VERSION 5.8 ;
BUSBITCHARS "[]" ;
DIVIDERCHAR "/" ;
UNITS
    DATABASE MICRONS 1000 ;
END UNITS

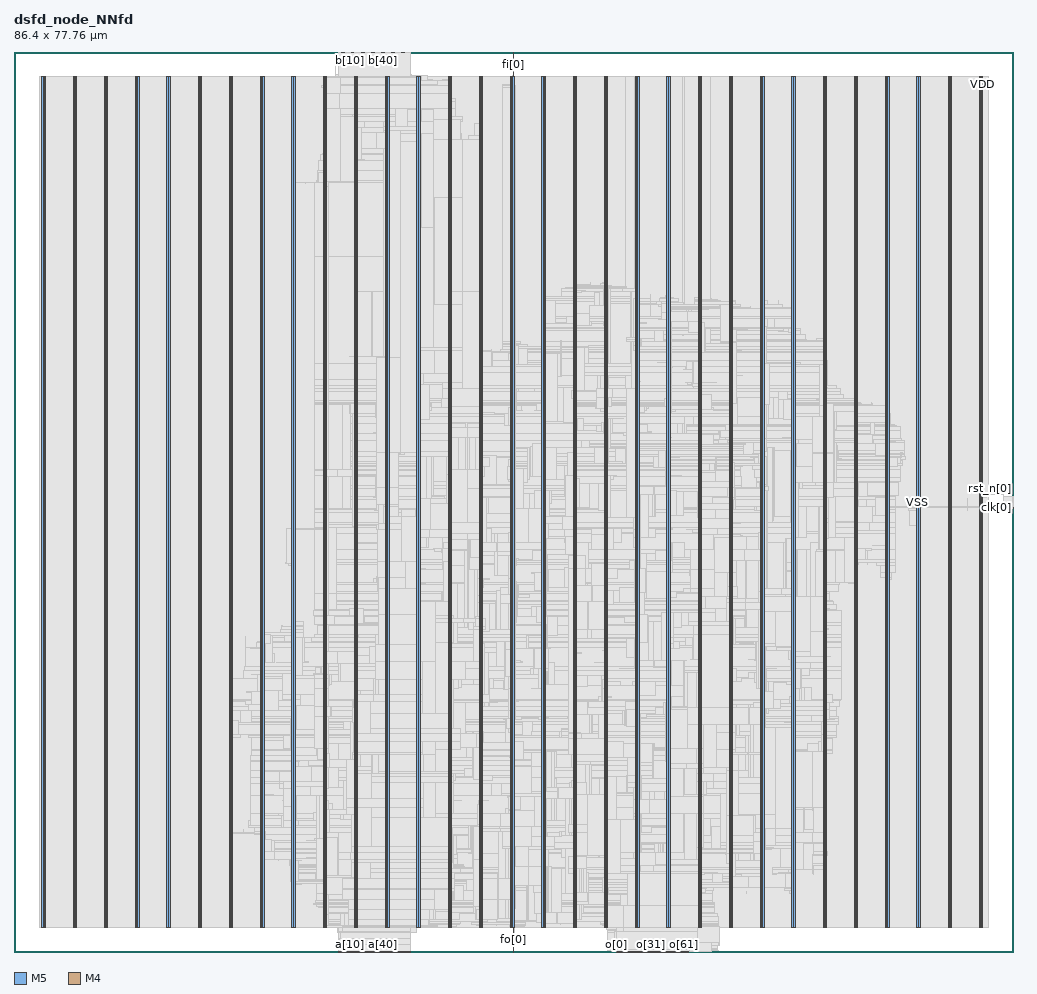
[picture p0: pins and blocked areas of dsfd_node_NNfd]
MACRO dsfd_node_NNfd
  FOREIGN dsfd_node_NNfd 0 0 ;
  CLASS BLOCK ;
  SIZE 86.4 BY 77.76 ;
  PIN a[0]
    DIRECTION INPUT ;
    USE SIGNAL ;
    PORT
      LAYER M5 ;
        RECT  28.032 0 28.056 0.084 ;
    END
  END a[0]
  PIN a[10]
    DIRECTION INPUT ;
    USE SIGNAL ;
    PORT
      LAYER M5 ;
        RECT  28.992 0 29.016 0.084 ;
    END
  END a[10]
  PIN a[11]
    DIRECTION INPUT ;
    USE SIGNAL ;
    PORT
      LAYER M5 ;
        RECT  29.088 0 29.112 0.084 ;
    END
  END a[11]
  PIN a[12]
    DIRECTION INPUT ;
    USE SIGNAL ;
    PORT
      LAYER M5 ;
        RECT  29.184 0 29.208 0.084 ;
    END
  END a[12]
  PIN a[13]
    DIRECTION INPUT ;
    USE SIGNAL ;
    PORT
      LAYER M5 ;
        RECT  29.28 0 29.304 0.084 ;
    END
  END a[13]
  PIN a[14]
    DIRECTION INPUT ;
    USE SIGNAL ;
    PORT
      LAYER M5 ;
        RECT  29.376 0 29.4 0.084 ;
    END
  END a[14]
  PIN a[15]
    DIRECTION INPUT ;
    USE SIGNAL ;
    PORT
      LAYER M5 ;
        RECT  29.472 0 29.496 0.084 ;
    END
  END a[15]
  PIN a[16]
    DIRECTION INPUT ;
    USE SIGNAL ;
    PORT
      LAYER M5 ;
        RECT  29.568 0 29.592 0.084 ;
    END
  END a[16]
  PIN a[17]
    DIRECTION INPUT ;
    USE SIGNAL ;
    PORT
      LAYER M5 ;
        RECT  29.664 0 29.688 0.084 ;
    END
  END a[17]
  PIN a[18]
    DIRECTION INPUT ;
    USE SIGNAL ;
    PORT
      LAYER M5 ;
        RECT  29.76 0 29.784 0.084 ;
    END
  END a[18]
  PIN a[19]
    DIRECTION INPUT ;
    USE SIGNAL ;
    PORT
      LAYER M5 ;
        RECT  29.856 0 29.88 0.084 ;
    END
  END a[19]
  PIN a[1]
    DIRECTION INPUT ;
    USE SIGNAL ;
    PORT
      LAYER M5 ;
        RECT  28.128 0 28.152 0.084 ;
    END
  END a[1]
  PIN a[20]
    DIRECTION INPUT ;
    USE SIGNAL ;
    PORT
      LAYER M5 ;
        RECT  29.952 0 29.976 0.084 ;
    END
  END a[20]
  PIN a[21]
    DIRECTION INPUT ;
    USE SIGNAL ;
    PORT
      LAYER M5 ;
        RECT  30.048 0 30.072 0.084 ;
    END
  END a[21]
  PIN a[22]
    DIRECTION INPUT ;
    USE SIGNAL ;
    PORT
      LAYER M5 ;
        RECT  30.144 0 30.168 0.084 ;
    END
  END a[22]
  PIN a[23]
    DIRECTION INPUT ;
    USE SIGNAL ;
    PORT
      LAYER M5 ;
        RECT  30.24 0 30.264 0.084 ;
    END
  END a[23]
  PIN a[24]
    DIRECTION INPUT ;
    USE SIGNAL ;
    PORT
      LAYER M5 ;
        RECT  30.336 0 30.36 0.084 ;
    END
  END a[24]
  PIN a[25]
    DIRECTION INPUT ;
    USE SIGNAL ;
    PORT
      LAYER M5 ;
        RECT  30.432 0 30.456 0.084 ;
    END
  END a[25]
  PIN a[26]
    DIRECTION INPUT ;
    USE SIGNAL ;
    PORT
      LAYER M5 ;
        RECT  30.528 0 30.552 0.084 ;
    END
  END a[26]
  PIN a[27]
    DIRECTION INPUT ;
    USE SIGNAL ;
    PORT
      LAYER M5 ;
        RECT  30.624 0 30.648 0.084 ;
    END
  END a[27]
  PIN a[28]
    DIRECTION INPUT ;
    USE SIGNAL ;
    PORT
      LAYER M5 ;
        RECT  30.72 0 30.744 0.084 ;
    END
  END a[28]
  PIN a[29]
    DIRECTION INPUT ;
    USE SIGNAL ;
    PORT
      LAYER M5 ;
        RECT  30.816 0 30.84 0.084 ;
    END
  END a[29]
  PIN a[2]
    DIRECTION INPUT ;
    USE SIGNAL ;
    PORT
      LAYER M5 ;
        RECT  28.224 0 28.248 0.084 ;
    END
  END a[2]
  PIN a[30]
    DIRECTION INPUT ;
    USE SIGNAL ;
    PORT
      LAYER M5 ;
        RECT  30.912 0 30.936 0.084 ;
    END
  END a[30]
  PIN a[31]
    DIRECTION INPUT ;
    USE SIGNAL ;
    PORT
      LAYER M5 ;
        RECT  31.008 0 31.032 0.084 ;
    END
  END a[31]
  PIN a[32]
    DIRECTION INPUT ;
    USE SIGNAL ;
    PORT
      LAYER M5 ;
        RECT  31.104 0 31.128 0.084 ;
    END
  END a[32]
  PIN a[33]
    DIRECTION INPUT ;
    USE SIGNAL ;
    PORT
      LAYER M5 ;
        RECT  31.2 0 31.224 0.084 ;
    END
  END a[33]
  PIN a[34]
    DIRECTION INPUT ;
    USE SIGNAL ;
    PORT
      LAYER M5 ;
        RECT  31.296 0 31.32 0.084 ;
    END
  END a[34]
  PIN a[35]
    DIRECTION INPUT ;
    USE SIGNAL ;
    PORT
      LAYER M5 ;
        RECT  31.392 0 31.416 0.084 ;
    END
  END a[35]
  PIN a[36]
    DIRECTION INPUT ;
    USE SIGNAL ;
    PORT
      LAYER M5 ;
        RECT  31.488 0 31.512 0.084 ;
    END
  END a[36]
  PIN a[37]
    DIRECTION INPUT ;
    USE SIGNAL ;
    PORT
      LAYER M5 ;
        RECT  31.584 0 31.608 0.084 ;
    END
  END a[37]
  PIN a[38]
    DIRECTION INPUT ;
    USE SIGNAL ;
    PORT
      LAYER M5 ;
        RECT  31.68 0 31.704 0.084 ;
    END
  END a[38]
  PIN a[39]
    DIRECTION INPUT ;
    USE SIGNAL ;
    PORT
      LAYER M5 ;
        RECT  31.776 0 31.8 0.084 ;
    END
  END a[39]
  PIN a[3]
    DIRECTION INPUT ;
    USE SIGNAL ;
    PORT
      LAYER M5 ;
        RECT  28.32 0 28.344 0.084 ;
    END
  END a[3]
  PIN a[40]
    DIRECTION INPUT ;
    USE SIGNAL ;
    PORT
      LAYER M5 ;
        RECT  31.872 0 31.896 0.084 ;
    END
  END a[40]
  PIN a[41]
    DIRECTION INPUT ;
    USE SIGNAL ;
    PORT
      LAYER M5 ;
        RECT  31.968 0 31.992 0.084 ;
    END
  END a[41]
  PIN a[42]
    DIRECTION INPUT ;
    USE SIGNAL ;
    PORT
      LAYER M5 ;
        RECT  32.064 0 32.088 0.084 ;
    END
  END a[42]
  PIN a[43]
    DIRECTION INPUT ;
    USE SIGNAL ;
    PORT
      LAYER M5 ;
        RECT  32.16 0 32.184 0.084 ;
    END
  END a[43]
  PIN a[44]
    DIRECTION INPUT ;
    USE SIGNAL ;
    PORT
      LAYER M5 ;
        RECT  32.256 0 32.28 0.084 ;
    END
  END a[44]
  PIN a[45]
    DIRECTION INPUT ;
    USE SIGNAL ;
    PORT
      LAYER M5 ;
        RECT  32.352 0 32.376 0.084 ;
    END
  END a[45]
  PIN a[46]
    DIRECTION INPUT ;
    USE SIGNAL ;
    PORT
      LAYER M5 ;
        RECT  32.448 0 32.472 0.084 ;
    END
  END a[46]
  PIN a[47]
    DIRECTION INPUT ;
    USE SIGNAL ;
    PORT
      LAYER M5 ;
        RECT  32.544 0 32.568 0.084 ;
    END
  END a[47]
  PIN a[48]
    DIRECTION INPUT ;
    USE SIGNAL ;
    PORT
      LAYER M5 ;
        RECT  32.64 0 32.664 0.084 ;
    END
  END a[48]
  PIN a[49]
    DIRECTION INPUT ;
    USE SIGNAL ;
    PORT
      LAYER M5 ;
        RECT  32.736 0 32.76 0.084 ;
    END
  END a[49]
  PIN a[4]
    DIRECTION INPUT ;
    USE SIGNAL ;
    PORT
      LAYER M5 ;
        RECT  28.416 0 28.44 0.084 ;
    END
  END a[4]
  PIN a[50]
    DIRECTION INPUT ;
    USE SIGNAL ;
    PORT
      LAYER M5 ;
        RECT  32.832 0 32.856 0.084 ;
    END
  END a[50]
  PIN a[51]
    DIRECTION INPUT ;
    USE SIGNAL ;
    PORT
      LAYER M5 ;
        RECT  32.928 0 32.952 0.084 ;
    END
  END a[51]
  PIN a[52]
    DIRECTION INPUT ;
    USE SIGNAL ;
    PORT
      LAYER M5 ;
        RECT  33.024 0 33.048 0.084 ;
    END
  END a[52]
  PIN a[53]
    DIRECTION INPUT ;
    USE SIGNAL ;
    PORT
      LAYER M5 ;
        RECT  33.12 0 33.144 0.084 ;
    END
  END a[53]
  PIN a[54]
    DIRECTION INPUT ;
    USE SIGNAL ;
    PORT
      LAYER M5 ;
        RECT  33.216 0 33.24 0.084 ;
    END
  END a[54]
  PIN a[55]
    DIRECTION INPUT ;
    USE SIGNAL ;
    PORT
      LAYER M5 ;
        RECT  33.312 0 33.336 0.084 ;
    END
  END a[55]
  PIN a[56]
    DIRECTION INPUT ;
    USE SIGNAL ;
    PORT
      LAYER M5 ;
        RECT  33.408 0 33.432 0.084 ;
    END
  END a[56]
  PIN a[57]
    DIRECTION INPUT ;
    USE SIGNAL ;
    PORT
      LAYER M5 ;
        RECT  33.504 0 33.528 0.084 ;
    END
  END a[57]
  PIN a[58]
    DIRECTION INPUT ;
    USE SIGNAL ;
    PORT
      LAYER M5 ;
        RECT  33.6 0 33.624 0.084 ;
    END
  END a[58]
  PIN a[59]
    DIRECTION INPUT ;
    USE SIGNAL ;
    PORT
      LAYER M5 ;
        RECT  33.696 0 33.72 0.084 ;
    END
  END a[59]
  PIN a[5]
    DIRECTION INPUT ;
    USE SIGNAL ;
    PORT
      LAYER M5 ;
        RECT  28.512 0 28.536 0.084 ;
    END
  END a[5]
  PIN a[60]
    DIRECTION INPUT ;
    USE SIGNAL ;
    PORT
      LAYER M5 ;
        RECT  33.792 0 33.816 0.084 ;
    END
  END a[60]
  PIN a[61]
    DIRECTION INPUT ;
    USE SIGNAL ;
    PORT
      LAYER M5 ;
        RECT  33.888 0 33.912 0.084 ;
    END
  END a[61]
  PIN a[62]
    DIRECTION INPUT ;
    USE SIGNAL ;
    PORT
      LAYER M5 ;
        RECT  33.984 0 34.008 0.084 ;
    END
  END a[62]
  PIN a[63]
    DIRECTION INPUT ;
    USE SIGNAL ;
    PORT
      LAYER M5 ;
        RECT  34.08 0 34.104 0.084 ;
    END
  END a[63]
  PIN a[64]
    DIRECTION INPUT ;
    USE SIGNAL ;
    PORT
      LAYER M5 ;
        RECT  34.176 0 34.2 0.084 ;
    END
  END a[64]
  PIN a[65]
    DIRECTION INPUT ;
    USE SIGNAL ;
    PORT
      LAYER M5 ;
        RECT  34.272 0 34.296 0.084 ;
    END
  END a[65]
  PIN a[6]
    DIRECTION INPUT ;
    USE SIGNAL ;
    PORT
      LAYER M5 ;
        RECT  28.608 0 28.632 0.084 ;
    END
  END a[6]
  PIN a[7]
    DIRECTION INPUT ;
    USE SIGNAL ;
    PORT
      LAYER M5 ;
        RECT  28.704 0 28.728 0.084 ;
    END
  END a[7]
  PIN a[8]
    DIRECTION INPUT ;
    USE SIGNAL ;
    PORT
      LAYER M5 ;
        RECT  28.8 0 28.824 0.084 ;
    END
  END a[8]
  PIN a[9]
    DIRECTION INPUT ;
    USE SIGNAL ;
    PORT
      LAYER M5 ;
        RECT  28.896 0 28.92 0.084 ;
    END
  END a[9]
  PIN b[0]
    DIRECTION INPUT ;
    USE SIGNAL ;
    PORT
      LAYER M5 ;
        RECT  28.032 77.676 28.056 77.76 ;
    END
  END b[0]
  PIN b[10]
    DIRECTION INPUT ;
    USE SIGNAL ;
    PORT
      LAYER M5 ;
        RECT  28.992 77.676 29.016 77.76 ;
    END
  END b[10]
  PIN b[11]
    DIRECTION INPUT ;
    USE SIGNAL ;
    PORT
      LAYER M5 ;
        RECT  29.088 77.676 29.112 77.76 ;
    END
  END b[11]
  PIN b[12]
    DIRECTION INPUT ;
    USE SIGNAL ;
    PORT
      LAYER M5 ;
        RECT  29.184 77.676 29.208 77.76 ;
    END
  END b[12]
  PIN b[13]
    DIRECTION INPUT ;
    USE SIGNAL ;
    PORT
      LAYER M5 ;
        RECT  29.28 77.676 29.304 77.76 ;
    END
  END b[13]
  PIN b[14]
    DIRECTION INPUT ;
    USE SIGNAL ;
    PORT
      LAYER M5 ;
        RECT  29.376 77.676 29.4 77.76 ;
    END
  END b[14]
  PIN b[15]
    DIRECTION INPUT ;
    USE SIGNAL ;
    PORT
      LAYER M5 ;
        RECT  29.472 77.676 29.496 77.76 ;
    END
  END b[15]
  PIN b[16]
    DIRECTION INPUT ;
    USE SIGNAL ;
    PORT
      LAYER M5 ;
        RECT  29.568 77.676 29.592 77.76 ;
    END
  END b[16]
  PIN b[17]
    DIRECTION INPUT ;
    USE SIGNAL ;
    PORT
      LAYER M5 ;
        RECT  29.664 77.676 29.688 77.76 ;
    END
  END b[17]
  PIN b[18]
    DIRECTION INPUT ;
    USE SIGNAL ;
    PORT
      LAYER M5 ;
        RECT  29.76 77.676 29.784 77.76 ;
    END
  END b[18]
  PIN b[19]
    DIRECTION INPUT ;
    USE SIGNAL ;
    PORT
      LAYER M5 ;
        RECT  29.856 77.676 29.88 77.76 ;
    END
  END b[19]
  PIN b[1]
    DIRECTION INPUT ;
    USE SIGNAL ;
    PORT
      LAYER M5 ;
        RECT  28.128 77.676 28.152 77.76 ;
    END
  END b[1]
  PIN b[20]
    DIRECTION INPUT ;
    USE SIGNAL ;
    PORT
      LAYER M5 ;
        RECT  29.952 77.676 29.976 77.76 ;
    END
  END b[20]
  PIN b[21]
    DIRECTION INPUT ;
    USE SIGNAL ;
    PORT
      LAYER M5 ;
        RECT  30.048 77.676 30.072 77.76 ;
    END
  END b[21]
  PIN b[22]
    DIRECTION INPUT ;
    USE SIGNAL ;
    PORT
      LAYER M5 ;
        RECT  30.144 77.676 30.168 77.76 ;
    END
  END b[22]
  PIN b[23]
    DIRECTION INPUT ;
    USE SIGNAL ;
    PORT
      LAYER M5 ;
        RECT  30.24 77.676 30.264 77.76 ;
    END
  END b[23]
  PIN b[24]
    DIRECTION INPUT ;
    USE SIGNAL ;
    PORT
      LAYER M5 ;
        RECT  30.336 77.676 30.36 77.76 ;
    END
  END b[24]
  PIN b[25]
    DIRECTION INPUT ;
    USE SIGNAL ;
    PORT
      LAYER M5 ;
        RECT  30.432 77.676 30.456 77.76 ;
    END
  END b[25]
  PIN b[26]
    DIRECTION INPUT ;
    USE SIGNAL ;
    PORT
      LAYER M5 ;
        RECT  30.528 77.676 30.552 77.76 ;
    END
  END b[26]
  PIN b[27]
    DIRECTION INPUT ;
    USE SIGNAL ;
    PORT
      LAYER M5 ;
        RECT  30.624 77.676 30.648 77.76 ;
    END
  END b[27]
  PIN b[28]
    DIRECTION INPUT ;
    USE SIGNAL ;
    PORT
      LAYER M5 ;
        RECT  30.72 77.676 30.744 77.76 ;
    END
  END b[28]
  PIN b[29]
    DIRECTION INPUT ;
    USE SIGNAL ;
    PORT
      LAYER M5 ;
        RECT  30.816 77.676 30.84 77.76 ;
    END
  END b[29]
  PIN b[2]
    DIRECTION INPUT ;
    USE SIGNAL ;
    PORT
      LAYER M5 ;
        RECT  28.224 77.676 28.248 77.76 ;
    END
  END b[2]
  PIN b[30]
    DIRECTION INPUT ;
    USE SIGNAL ;
    PORT
      LAYER M5 ;
        RECT  30.912 77.676 30.936 77.76 ;
    END
  END b[30]
  PIN b[31]
    DIRECTION INPUT ;
    USE SIGNAL ;
    PORT
      LAYER M5 ;
        RECT  31.008 77.676 31.032 77.76 ;
    END
  END b[31]
  PIN b[32]
    DIRECTION INPUT ;
    USE SIGNAL ;
    PORT
      LAYER M5 ;
        RECT  31.104 77.676 31.128 77.76 ;
    END
  END b[32]
  PIN b[33]
    DIRECTION INPUT ;
    USE SIGNAL ;
    PORT
      LAYER M5 ;
        RECT  31.2 77.676 31.224 77.76 ;
    END
  END b[33]
  PIN b[34]
    DIRECTION INPUT ;
    USE SIGNAL ;
    PORT
      LAYER M5 ;
        RECT  31.296 77.676 31.32 77.76 ;
    END
  END b[34]
  PIN b[35]
    DIRECTION INPUT ;
    USE SIGNAL ;
    PORT
      LAYER M5 ;
        RECT  31.392 77.676 31.416 77.76 ;
    END
  END b[35]
  PIN b[36]
    DIRECTION INPUT ;
    USE SIGNAL ;
    PORT
      LAYER M5 ;
        RECT  31.488 77.676 31.512 77.76 ;
    END
  END b[36]
  PIN b[37]
    DIRECTION INPUT ;
    USE SIGNAL ;
    PORT
      LAYER M5 ;
        RECT  31.584 77.676 31.608 77.76 ;
    END
  END b[37]
  PIN b[38]
    DIRECTION INPUT ;
    USE SIGNAL ;
    PORT
      LAYER M5 ;
        RECT  31.68 77.676 31.704 77.76 ;
    END
  END b[38]
  PIN b[39]
    DIRECTION INPUT ;
    USE SIGNAL ;
    PORT
      LAYER M5 ;
        RECT  31.776 77.676 31.8 77.76 ;
    END
  END b[39]
  PIN b[3]
    DIRECTION INPUT ;
    USE SIGNAL ;
    PORT
      LAYER M5 ;
        RECT  28.32 77.676 28.344 77.76 ;
    END
  END b[3]
  PIN b[40]
    DIRECTION INPUT ;
    USE SIGNAL ;
    PORT
      LAYER M5 ;
        RECT  31.872 77.676 31.896 77.76 ;
    END
  END b[40]
  PIN b[41]
    DIRECTION INPUT ;
    USE SIGNAL ;
    PORT
      LAYER M5 ;
        RECT  31.968 77.676 31.992 77.76 ;
    END
  END b[41]
  PIN b[42]
    DIRECTION INPUT ;
    USE SIGNAL ;
    PORT
      LAYER M5 ;
        RECT  32.064 77.676 32.088 77.76 ;
    END
  END b[42]
  PIN b[43]
    DIRECTION INPUT ;
    USE SIGNAL ;
    PORT
      LAYER M5 ;
        RECT  32.16 77.676 32.184 77.76 ;
    END
  END b[43]
  PIN b[44]
    DIRECTION INPUT ;
    USE SIGNAL ;
    PORT
      LAYER M5 ;
        RECT  32.256 77.676 32.28 77.76 ;
    END
  END b[44]
  PIN b[45]
    DIRECTION INPUT ;
    USE SIGNAL ;
    PORT
      LAYER M5 ;
        RECT  32.352 77.676 32.376 77.76 ;
    END
  END b[45]
  PIN b[46]
    DIRECTION INPUT ;
    USE SIGNAL ;
    PORT
      LAYER M5 ;
        RECT  32.448 77.676 32.472 77.76 ;
    END
  END b[46]
  PIN b[47]
    DIRECTION INPUT ;
    USE SIGNAL ;
    PORT
      LAYER M5 ;
        RECT  32.544 77.676 32.568 77.76 ;
    END
  END b[47]
  PIN b[48]
    DIRECTION INPUT ;
    USE SIGNAL ;
    PORT
      LAYER M5 ;
        RECT  32.64 77.676 32.664 77.76 ;
    END
  END b[48]
  PIN b[49]
    DIRECTION INPUT ;
    USE SIGNAL ;
    PORT
      LAYER M5 ;
        RECT  32.736 77.676 32.76 77.76 ;
    END
  END b[49]
  PIN b[4]
    DIRECTION INPUT ;
    USE SIGNAL ;
    PORT
      LAYER M5 ;
        RECT  28.416 77.676 28.44 77.76 ;
    END
  END b[4]
  PIN b[50]
    DIRECTION INPUT ;
    USE SIGNAL ;
    PORT
      LAYER M5 ;
        RECT  32.832 77.676 32.856 77.76 ;
    END
  END b[50]
  PIN b[51]
    DIRECTION INPUT ;
    USE SIGNAL ;
    PORT
      LAYER M5 ;
        RECT  32.928 77.676 32.952 77.76 ;
    END
  END b[51]
  PIN b[52]
    DIRECTION INPUT ;
    USE SIGNAL ;
    PORT
      LAYER M5 ;
        RECT  33.024 77.676 33.048 77.76 ;
    END
  END b[52]
  PIN b[53]
    DIRECTION INPUT ;
    USE SIGNAL ;
    PORT
      LAYER M5 ;
        RECT  33.12 77.676 33.144 77.76 ;
    END
  END b[53]
  PIN b[54]
    DIRECTION INPUT ;
    USE SIGNAL ;
    PORT
      LAYER M5 ;
        RECT  33.216 77.676 33.24 77.76 ;
    END
  END b[54]
  PIN b[55]
    DIRECTION INPUT ;
    USE SIGNAL ;
    PORT
      LAYER M5 ;
        RECT  33.312 77.676 33.336 77.76 ;
    END
  END b[55]
  PIN b[56]
    DIRECTION INPUT ;
    USE SIGNAL ;
    PORT
      LAYER M5 ;
        RECT  33.408 77.676 33.432 77.76 ;
    END
  END b[56]
  PIN b[57]
    DIRECTION INPUT ;
    USE SIGNAL ;
    PORT
      LAYER M5 ;
        RECT  33.504 77.676 33.528 77.76 ;
    END
  END b[57]
  PIN b[58]
    DIRECTION INPUT ;
    USE SIGNAL ;
    PORT
      LAYER M5 ;
        RECT  33.6 77.676 33.624 77.76 ;
    END
  END b[58]
  PIN b[59]
    DIRECTION INPUT ;
    USE SIGNAL ;
    PORT
      LAYER M5 ;
        RECT  33.696 77.676 33.72 77.76 ;
    END
  END b[59]
  PIN b[5]
    DIRECTION INPUT ;
    USE SIGNAL ;
    PORT
      LAYER M5 ;
        RECT  28.512 77.676 28.536 77.76 ;
    END
  END b[5]
  PIN b[60]
    DIRECTION INPUT ;
    USE SIGNAL ;
    PORT
      LAYER M5 ;
        RECT  33.792 77.676 33.816 77.76 ;
    END
  END b[60]
  PIN b[61]
    DIRECTION INPUT ;
    USE SIGNAL ;
    PORT
      LAYER M5 ;
        RECT  33.888 77.676 33.912 77.76 ;
    END
  END b[61]
  PIN b[62]
    DIRECTION INPUT ;
    USE SIGNAL ;
    PORT
      LAYER M5 ;
        RECT  33.984 77.676 34.008 77.76 ;
    END
  END b[62]
  PIN b[63]
    DIRECTION INPUT ;
    USE SIGNAL ;
    PORT
      LAYER M5 ;
        RECT  34.08 77.676 34.104 77.76 ;
    END
  END b[63]
  PIN b[64]
    DIRECTION INPUT ;
    USE SIGNAL ;
    PORT
      LAYER M5 ;
        RECT  34.176 77.676 34.2 77.76 ;
    END
  END b[64]
  PIN b[65]
    DIRECTION INPUT ;
    USE SIGNAL ;
    PORT
      LAYER M5 ;
        RECT  34.272 77.676 34.296 77.76 ;
    END
  END b[65]
  PIN b[6]
    DIRECTION INPUT ;
    USE SIGNAL ;
    PORT
      LAYER M5 ;
        RECT  28.608 77.676 28.632 77.76 ;
    END
  END b[6]
  PIN b[7]
    DIRECTION INPUT ;
    USE SIGNAL ;
    PORT
      LAYER M5 ;
        RECT  28.704 77.676 28.728 77.76 ;
    END
  END b[7]
  PIN b[8]
    DIRECTION INPUT ;
    USE SIGNAL ;
    PORT
      LAYER M5 ;
        RECT  28.8 77.676 28.824 77.76 ;
    END
  END b[8]
  PIN b[9]
    DIRECTION INPUT ;
    USE SIGNAL ;
    PORT
      LAYER M5 ;
        RECT  28.896 77.676 28.92 77.76 ;
    END
  END b[9]
  PIN clk[0]
    DIRECTION INPUT ;
    USE SIGNAL ;
    PORT
      LAYER M4 ;
        RECT  86.316 38.352 86.4 38.376 ;
    END
    PORT
      LAYER M4 ;
        RECT  86.321 38.352 86.364 38.376 ;
    END
  END clk[0]
  PIN fi[0]
    DIRECTION INPUT ;
    USE SIGNAL ;
    PORT
      LAYER M5 ;
        RECT  43.152 77.676 43.176 77.76 ;
    END
    PORT
      LAYER M5 ;
        RECT  43.152 75.623 43.176 77.712 ;
    END
  END fi[0]
  PIN fo[0]
    DIRECTION OUTPUT ;
    USE SIGNAL ;
    PORT
      LAYER M5 ;
        RECT  43.152 0 43.176 0.084 ;
    END
    PORT
      LAYER M5 ;
        RECT  43.152 0.016 43.176 2.137 ;
    END
  END fo[0]
  PIN o[0]
    DIRECTION OUTPUT ;
    USE SIGNAL ;
    PORT
      LAYER M5 ;
        RECT  52.032 0 52.056 0.084 ;
    END
  END o[0]
  PIN o[10]
    DIRECTION OUTPUT ;
    USE SIGNAL ;
    PORT
      LAYER M5 ;
        RECT  52.992 0 53.016 0.084 ;
    END
  END o[10]
  PIN o[11]
    DIRECTION OUTPUT ;
    USE SIGNAL ;
    PORT
      LAYER M5 ;
        RECT  53.088 0 53.112 0.084 ;
    END
  END o[11]
  PIN o[12]
    DIRECTION OUTPUT ;
    USE SIGNAL ;
    PORT
      LAYER M5 ;
        RECT  53.184 0 53.208 0.084 ;
    END
  END o[12]
  PIN o[13]
    DIRECTION OUTPUT ;
    USE SIGNAL ;
    PORT
      LAYER M5 ;
        RECT  53.28 0 53.304 0.084 ;
    END
  END o[13]
  PIN o[14]
    DIRECTION OUTPUT ;
    USE SIGNAL ;
    PORT
      LAYER M5 ;
        RECT  53.376 0 53.4 0.084 ;
    END
  END o[14]
  PIN o[15]
    DIRECTION OUTPUT ;
    USE SIGNAL ;
    PORT
      LAYER M5 ;
        RECT  53.472 0 53.496 0.084 ;
    END
  END o[15]
  PIN o[16]
    DIRECTION OUTPUT ;
    USE SIGNAL ;
    PORT
      LAYER M5 ;
        RECT  53.568 0 53.592 0.084 ;
    END
  END o[16]
  PIN o[17]
    DIRECTION OUTPUT ;
    USE SIGNAL ;
    PORT
      LAYER M5 ;
        RECT  53.664 0 53.688 0.084 ;
    END
  END o[17]
  PIN o[18]
    DIRECTION OUTPUT ;
    USE SIGNAL ;
    PORT
      LAYER M5 ;
        RECT  53.76 0 53.784 0.084 ;
    END
  END o[18]
  PIN o[19]
    DIRECTION OUTPUT ;
    USE SIGNAL ;
    PORT
      LAYER M5 ;
        RECT  53.856 0 53.88 0.084 ;
    END
  END o[19]
  PIN o[1]
    DIRECTION OUTPUT ;
    USE SIGNAL ;
    PORT
      LAYER M5 ;
        RECT  52.128 0 52.152 0.084 ;
    END
  END o[1]
  PIN o[20]
    DIRECTION OUTPUT ;
    USE SIGNAL ;
    PORT
      LAYER M5 ;
        RECT  53.952 0 53.976 0.084 ;
    END
  END o[20]
  PIN o[21]
    DIRECTION OUTPUT ;
    USE SIGNAL ;
    PORT
      LAYER M5 ;
        RECT  54.048 0 54.072 0.084 ;
    END
  END o[21]
  PIN o[22]
    DIRECTION OUTPUT ;
    USE SIGNAL ;
    PORT
      LAYER M5 ;
        RECT  54.144 0 54.168 0.084 ;
    END
  END o[22]
  PIN o[23]
    DIRECTION OUTPUT ;
    USE SIGNAL ;
    PORT
      LAYER M5 ;
        RECT  54.24 0 54.264 0.084 ;
    END
  END o[23]
  PIN o[24]
    DIRECTION OUTPUT ;
    USE SIGNAL ;
    PORT
      LAYER M5 ;
        RECT  54.336 0 54.36 0.084 ;
    END
  END o[24]
  PIN o[25]
    DIRECTION OUTPUT ;
    USE SIGNAL ;
    PORT
      LAYER M5 ;
        RECT  54.432 0 54.456 0.084 ;
    END
  END o[25]
  PIN o[26]
    DIRECTION OUTPUT ;
    USE SIGNAL ;
    PORT
      LAYER M5 ;
        RECT  54.528 0 54.552 0.084 ;
    END
  END o[26]
  PIN o[27]
    DIRECTION OUTPUT ;
    USE SIGNAL ;
    PORT
      LAYER M5 ;
        RECT  54.624 0 54.648 0.084 ;
    END
  END o[27]
  PIN o[28]
    DIRECTION OUTPUT ;
    USE SIGNAL ;
    PORT
      LAYER M5 ;
        RECT  54.72 0 54.744 0.084 ;
    END
  END o[28]
  PIN o[29]
    DIRECTION OUTPUT ;
    USE SIGNAL ;
    PORT
      LAYER M5 ;
        RECT  54.816 0 54.84 0.084 ;
    END
  END o[29]
  PIN o[2]
    DIRECTION OUTPUT ;
    USE SIGNAL ;
    PORT
      LAYER M5 ;
        RECT  52.224 0 52.248 0.084 ;
    END
  END o[2]
  PIN o[30]
    DIRECTION OUTPUT ;
    USE SIGNAL ;
    PORT
      LAYER M5 ;
        RECT  54.912 0 54.936 0.084 ;
    END
  END o[30]
  PIN o[31]
    DIRECTION OUTPUT ;
    USE SIGNAL ;
    PORT
      LAYER M5 ;
        RECT  55.008 0 55.032 0.084 ;
    END
  END o[31]
  PIN o[32]
    DIRECTION OUTPUT ;
    USE SIGNAL ;
    PORT
      LAYER M5 ;
        RECT  55.104 0 55.128 0.084 ;
    END
  END o[32]
  PIN o[33]
    DIRECTION OUTPUT ;
    USE SIGNAL ;
    PORT
      LAYER M5 ;
        RECT  55.2 0 55.224 0.084 ;
    END
  END o[33]
  PIN o[34]
    DIRECTION OUTPUT ;
    USE SIGNAL ;
    PORT
      LAYER M5 ;
        RECT  55.296 0 55.32 0.084 ;
    END
  END o[34]
  PIN o[35]
    DIRECTION OUTPUT ;
    USE SIGNAL ;
    PORT
      LAYER M5 ;
        RECT  55.392 0 55.416 0.084 ;
    END
  END o[35]
  PIN o[36]
    DIRECTION OUTPUT ;
    USE SIGNAL ;
    PORT
      LAYER M5 ;
        RECT  55.488 0 55.512 0.084 ;
    END
  END o[36]
  PIN o[37]
    DIRECTION OUTPUT ;
    USE SIGNAL ;
    PORT
      LAYER M5 ;
        RECT  55.584 0 55.608 0.084 ;
    END
  END o[37]
  PIN o[38]
    DIRECTION OUTPUT ;
    USE SIGNAL ;
    PORT
      LAYER M5 ;
        RECT  55.68 0 55.704 0.084 ;
    END
  END o[38]
  PIN o[39]
    DIRECTION OUTPUT ;
    USE SIGNAL ;
    PORT
      LAYER M5 ;
        RECT  55.776 0 55.8 0.084 ;
    END
  END o[39]
  PIN o[3]
    DIRECTION OUTPUT ;
    USE SIGNAL ;
    PORT
      LAYER M5 ;
        RECT  52.32 0 52.344 0.084 ;
    END
  END o[3]
  PIN o[40]
    DIRECTION OUTPUT ;
    USE SIGNAL ;
    PORT
      LAYER M5 ;
        RECT  55.872 0 55.896 0.084 ;
    END
  END o[40]
  PIN o[41]
    DIRECTION OUTPUT ;
    USE SIGNAL ;
    PORT
      LAYER M5 ;
        RECT  55.968 0 55.992 0.084 ;
    END
  END o[41]
  PIN o[42]
    DIRECTION OUTPUT ;
    USE SIGNAL ;
    PORT
      LAYER M5 ;
        RECT  56.064 0 56.088 0.084 ;
    END
  END o[42]
  PIN o[43]
    DIRECTION OUTPUT ;
    USE SIGNAL ;
    PORT
      LAYER M5 ;
        RECT  56.16 0 56.184 0.084 ;
    END
  END o[43]
  PIN o[44]
    DIRECTION OUTPUT ;
    USE SIGNAL ;
    PORT
      LAYER M5 ;
        RECT  56.256 0 56.28 0.084 ;
    END
  END o[44]
  PIN o[45]
    DIRECTION OUTPUT ;
    USE SIGNAL ;
    PORT
      LAYER M5 ;
        RECT  56.352 0 56.376 0.084 ;
    END
  END o[45]
  PIN o[46]
    DIRECTION OUTPUT ;
    USE SIGNAL ;
    PORT
      LAYER M5 ;
        RECT  56.448 0 56.472 0.084 ;
    END
  END o[46]
  PIN o[47]
    DIRECTION OUTPUT ;
    USE SIGNAL ;
    PORT
      LAYER M5 ;
        RECT  56.544 0 56.568 0.084 ;
    END
  END o[47]
  PIN o[48]
    DIRECTION OUTPUT ;
    USE SIGNAL ;
    PORT
      LAYER M5 ;
        RECT  56.64 0 56.664 0.084 ;
    END
  END o[48]
  PIN o[49]
    DIRECTION OUTPUT ;
    USE SIGNAL ;
    PORT
      LAYER M5 ;
        RECT  56.736 0 56.76 0.084 ;
    END
  END o[49]
  PIN o[4]
    DIRECTION OUTPUT ;
    USE SIGNAL ;
    PORT
      LAYER M5 ;
        RECT  52.416 0 52.44 0.084 ;
    END
  END o[4]
  PIN o[50]
    DIRECTION OUTPUT ;
    USE SIGNAL ;
    PORT
      LAYER M5 ;
        RECT  56.832 0 56.856 0.084 ;
    END
  END o[50]
  PIN o[51]
    DIRECTION OUTPUT ;
    USE SIGNAL ;
    PORT
      LAYER M5 ;
        RECT  56.928 0 56.952 0.084 ;
    END
  END o[51]
  PIN o[52]
    DIRECTION OUTPUT ;
    USE SIGNAL ;
    PORT
      LAYER M5 ;
        RECT  57.024 0 57.048 0.084 ;
    END
  END o[52]
  PIN o[53]
    DIRECTION OUTPUT ;
    USE SIGNAL ;
    PORT
      LAYER M5 ;
        RECT  57.12 0 57.144 0.084 ;
    END
  END o[53]
  PIN o[54]
    DIRECTION OUTPUT ;
    USE SIGNAL ;
    PORT
      LAYER M5 ;
        RECT  57.216 0 57.24 0.084 ;
    END
  END o[54]
  PIN o[55]
    DIRECTION OUTPUT ;
    USE SIGNAL ;
    PORT
      LAYER M5 ;
        RECT  57.312 0 57.336 0.084 ;
    END
  END o[55]
  PIN o[56]
    DIRECTION OUTPUT ;
    USE SIGNAL ;
    PORT
      LAYER M5 ;
        RECT  57.408 0 57.432 0.084 ;
    END
  END o[56]
  PIN o[57]
    DIRECTION OUTPUT ;
    USE SIGNAL ;
    PORT
      LAYER M5 ;
        RECT  57.504 0 57.528 0.084 ;
    END
  END o[57]
  PIN o[58]
    DIRECTION OUTPUT ;
    USE SIGNAL ;
    PORT
      LAYER M5 ;
        RECT  57.6 0 57.624 0.084 ;
    END
  END o[58]
  PIN o[59]
    DIRECTION OUTPUT ;
    USE SIGNAL ;
    PORT
      LAYER M5 ;
        RECT  57.696 0 57.72 0.084 ;
    END
  END o[59]
  PIN o[5]
    DIRECTION OUTPUT ;
    USE SIGNAL ;
    PORT
      LAYER M5 ;
        RECT  52.512 0 52.536 0.084 ;
    END
  END o[5]
  PIN o[60]
    DIRECTION OUTPUT ;
    USE SIGNAL ;
    PORT
      LAYER M5 ;
        RECT  57.792 0 57.816 0.084 ;
    END
  END o[60]
  PIN o[61]
    DIRECTION OUTPUT ;
    USE SIGNAL ;
    PORT
      LAYER M5 ;
        RECT  57.888 0 57.912 0.084 ;
    END
  END o[61]
  PIN o[62]
    DIRECTION OUTPUT ;
    USE SIGNAL ;
    PORT
      LAYER M5 ;
        RECT  57.984 0 58.008 0.084 ;
    END
  END o[62]
  PIN o[63]
    DIRECTION OUTPUT ;
    USE SIGNAL ;
    PORT
      LAYER M5 ;
        RECT  58.08 0 58.104 0.084 ;
    END
  END o[63]
  PIN o[64]
    DIRECTION OUTPUT ;
    USE SIGNAL ;
    PORT
      LAYER M5 ;
        RECT  58.176 0 58.2 0.084 ;
    END
  END o[64]
  PIN o[65]
    DIRECTION OUTPUT ;
    USE SIGNAL ;
    PORT
      LAYER M5 ;
        RECT  58.272 0 58.296 0.084 ;
    END
  END o[65]
  PIN o[6]
    DIRECTION OUTPUT ;
    USE SIGNAL ;
    PORT
      LAYER M5 ;
        RECT  52.608 0 52.632 0.084 ;
    END
  END o[6]
  PIN o[7]
    DIRECTION OUTPUT ;
    USE SIGNAL ;
    PORT
      LAYER M5 ;
        RECT  52.704 0 52.728 0.084 ;
    END
  END o[7]
  PIN o[8]
    DIRECTION OUTPUT ;
    USE SIGNAL ;
    PORT
      LAYER M5 ;
        RECT  52.8 0 52.824 0.084 ;
    END
  END o[8]
  PIN o[9]
    DIRECTION OUTPUT ;
    USE SIGNAL ;
    PORT
      LAYER M5 ;
        RECT  52.896 0 52.92 0.084 ;
    END
  END o[9]
  PIN rst_n[0]
    DIRECTION INPUT ;
    USE SIGNAL ;
    PORT
      LAYER M4 ;
        RECT  86.316 39.36 86.4 39.384 ;
    END
    PORT
      LAYER M4 ;
        RECT  86.321 39.36 86.364 39.384 ;
    END
  END rst_n[0]
  PIN VDD
    DIRECTION INOUT ;
    USE POWER ;
    PORT
      LAYER M5 ;
        RECT  83.592 2.151 83.712 75.609 ;
        RECT  80.892 2.151 81.012 75.609 ;
        RECT  78.192 2.151 78.312 75.609 ;
        RECT  75.492 2.151 75.612 75.609 ;
        RECT  72.792 2.151 72.912 75.609 ;
        RECT  70.092 2.151 70.212 75.609 ;
        RECT  67.392 2.151 67.512 75.609 ;
        RECT  64.692 2.151 64.812 75.609 ;
        RECT  61.992 2.151 62.112 75.609 ;
        RECT  59.292 2.151 59.412 75.609 ;
        RECT  56.592 2.151 56.712 75.609 ;
        RECT  53.892 2.151 54.012 75.609 ;
        RECT  51.192 2.151 51.312 75.609 ;
        RECT  48.492 2.151 48.612 75.609 ;
        RECT  45.792 2.151 45.912 75.609 ;
        RECT  43.092 2.151 43.212 75.609 ;
        RECT  40.392 2.151 40.512 75.609 ;
        RECT  37.692 2.151 37.812 75.609 ;
        RECT  34.992 2.151 35.112 75.609 ;
        RECT  32.292 2.151 32.412 75.609 ;
        RECT  29.592 2.151 29.712 75.609 ;
        RECT  26.892 2.151 27.012 75.609 ;
        RECT  24.192 2.151 24.312 75.609 ;
        RECT  21.492 2.151 21.612 75.609 ;
        RECT  18.792 2.151 18.912 75.609 ;
        RECT  16.092 2.151 16.212 75.609 ;
        RECT  13.392 2.151 13.512 75.609 ;
        RECT  10.692 2.151 10.812 75.609 ;
        RECT  7.992 2.151 8.112 75.609 ;
        RECT  5.292 2.151 5.412 75.609 ;
        RECT  2.592 2.151 2.712 75.609 ;
    END
  END VDD
  PIN VSS
    DIRECTION INOUT ;
    USE GROUND ;
    PORT
      LAYER M5 ;
        RECT  83.4 2.137 83.52 75.623 ;
        RECT  80.7 2.137 80.82 75.623 ;
        RECT  78 2.137 78.12 75.623 ;
        RECT  75.3 2.137 75.42 75.623 ;
        RECT  72.6 2.137 72.72 75.623 ;
        RECT  69.9 2.137 70.02 75.623 ;
        RECT  67.2 2.137 67.32 75.623 ;
        RECT  64.5 2.137 64.62 75.623 ;
        RECT  61.8 2.137 61.92 75.623 ;
        RECT  59.1 2.137 59.22 75.623 ;
        RECT  56.4 2.137 56.52 75.623 ;
        RECT  53.7 2.137 53.82 75.623 ;
        RECT  51 2.137 51.12 75.623 ;
        RECT  48.3 2.137 48.42 75.623 ;
        RECT  45.6 2.137 45.72 75.623 ;
        RECT  42.9 2.137 43.02 75.623 ;
        RECT  40.2 2.137 40.32 75.623 ;
        RECT  37.5 2.137 37.62 75.623 ;
        RECT  34.8 2.137 34.92 75.623 ;
        RECT  32.1 2.137 32.22 75.623 ;
        RECT  29.4 2.137 29.52 75.623 ;
        RECT  26.7 2.137 26.82 75.623 ;
        RECT  24 2.137 24.12 75.623 ;
        RECT  21.3 2.137 21.42 75.623 ;
        RECT  18.6 2.137 18.72 75.623 ;
        RECT  15.9 2.137 16.02 75.623 ;
        RECT  13.2 2.137 13.32 75.623 ;
        RECT  10.5 2.137 10.62 75.623 ;
        RECT  7.8 2.137 7.92 75.623 ;
        RECT  5.1 2.137 5.22 75.623 ;
        RECT  2.4 2.137 2.52 75.623 ;
    END
  END VSS
  # OT_OBS_CLOSED layer=M5 d_um=1.536 added=231
  OBS
    LAYER RVTN ;
     RECT  2.16 2.16 84.24 2.295 ;
     RECT  2.16 2.565 84.24 2.835 ;
     RECT  2.16 3.105 84.24 3.375 ;
     RECT  2.16 3.645 84.24 3.915 ;
     RECT  2.16 4.185 84.24 4.455 ;
     RECT  2.16 4.725 84.24 4.995 ;
     RECT  2.16 5.265 84.24 5.535 ;
     RECT  2.16 5.805 84.24 6.075 ;
     RECT  2.16 6.345 84.24 6.615 ;
     RECT  2.16 6.885 84.24 7.155 ;
     RECT  2.16 7.425 84.24 7.695 ;
     RECT  2.16 7.965 84.24 8.235 ;
     RECT  2.16 8.505 84.24 8.775 ;
     RECT  2.16 9.045 84.24 9.315 ;
     RECT  2.16 9.585 84.24 9.855 ;
     RECT  2.16 10.125 84.24 10.395 ;
     RECT  2.16 10.665 84.24 10.935 ;
     RECT  2.16 11.205 84.24 11.475 ;
     RECT  2.16 11.745 84.24 12.015 ;
     RECT  2.16 12.285 84.24 12.555 ;
     RECT  2.16 12.825 84.24 13.095 ;
     RECT  2.16 13.365 84.24 13.635 ;
     RECT  2.16 13.905 84.24 14.175 ;
     RECT  2.16 14.445 84.24 14.715 ;
     RECT  2.16 14.985 84.24 15.255 ;
     RECT  2.16 15.525 84.24 15.795 ;
     RECT  2.16 16.065 84.24 16.335 ;
     RECT  2.16 16.605 84.24 16.875 ;
     RECT  2.16 17.145 84.24 17.415 ;
     RECT  2.16 17.685 84.24 17.955 ;
     RECT  2.16 18.225 84.24 18.495 ;
     RECT  2.16 18.765 84.24 19.035 ;
     RECT  2.16 19.305 84.24 19.575 ;
     RECT  2.16 19.845 84.24 20.115 ;
     RECT  2.16 20.385 84.24 20.655 ;
     RECT  2.16 20.925 84.24 21.195 ;
     RECT  2.16 21.465 84.24 21.735 ;
     RECT  2.16 22.005 84.24 22.275 ;
     RECT  2.16 22.545 84.24 22.815 ;
     RECT  2.16 23.085 84.24 23.355 ;
     RECT  2.16 23.625 84.24 23.895 ;
     RECT  2.16 24.165 84.24 24.435 ;
     RECT  2.16 24.705 84.24 24.975 ;
     RECT  2.16 25.245 84.24 25.515 ;
     RECT  2.16 25.785 84.24 26.055 ;
     RECT  2.16 26.325 84.24 26.595 ;
     RECT  2.16 26.865 84.24 27.135 ;
     RECT  2.16 27.405 84.24 27.675 ;
     RECT  2.16 27.945 84.24 28.215 ;
     RECT  2.16 28.485 84.24 28.755 ;
     RECT  2.16 29.025 84.24 29.295 ;
     RECT  2.16 29.565 84.24 29.835 ;
     RECT  2.16 30.105 84.24 30.375 ;
     RECT  2.16 30.645 84.24 30.915 ;
     RECT  2.16 31.185 84.24 31.455 ;
     RECT  2.16 31.725 84.24 31.995 ;
     RECT  2.16 32.265 84.24 32.535 ;
     RECT  2.16 32.805 84.24 33.075 ;
     RECT  2.16 33.345 84.24 33.615 ;
     RECT  2.16 33.885 84.24 34.155 ;
     RECT  2.16 34.425 84.24 34.695 ;
     RECT  2.16 34.965 84.24 35.235 ;
     RECT  2.16 35.505 84.24 35.775 ;
     RECT  2.16 36.045 84.24 36.315 ;
     RECT  2.16 36.585 84.24 36.855 ;
     RECT  2.16 37.125 84.24 37.395 ;
     RECT  2.16 37.665 84.24 37.935 ;
     RECT  2.16 38.205 84.24 38.475 ;
     RECT  2.16 38.745 84.24 39.015 ;
     RECT  2.16 39.285 84.24 39.555 ;
     RECT  2.16 39.825 84.24 40.095 ;
     RECT  2.16 40.365 84.24 40.635 ;
     RECT  2.16 40.905 84.24 41.175 ;
     RECT  2.16 41.445 84.24 41.715 ;
     RECT  2.16 41.985 84.24 42.255 ;
     RECT  2.16 42.525 84.24 42.795 ;
     RECT  2.16 43.065 84.24 43.335 ;
     RECT  2.16 43.605 84.24 43.875 ;
     RECT  2.16 44.145 84.24 44.415 ;
     RECT  2.16 44.685 84.24 44.955 ;
     RECT  2.16 45.225 84.24 45.495 ;
     RECT  2.16 45.765 84.24 46.035 ;
     RECT  2.16 46.305 84.24 46.575 ;
     RECT  2.16 46.845 84.24 47.115 ;
     RECT  2.16 47.385 84.24 47.655 ;
     RECT  2.16 47.925 84.24 48.195 ;
     RECT  2.16 48.465 84.24 48.735 ;
     RECT  2.16 49.005 84.24 49.275 ;
     RECT  2.16 49.545 84.24 49.815 ;
     RECT  2.16 50.085 84.24 50.355 ;
     RECT  2.16 50.625 84.24 50.895 ;
     RECT  2.16 51.165 84.24 51.435 ;
     RECT  2.16 51.705 84.24 51.975 ;
     RECT  2.16 52.245 84.24 52.515 ;
     RECT  2.16 52.785 84.24 53.055 ;
     RECT  2.16 53.325 84.24 53.595 ;
     RECT  2.16 53.865 84.24 54.135 ;
     RECT  2.16 54.405 84.24 54.675 ;
     RECT  2.16 54.945 84.24 55.215 ;
     RECT  2.16 55.485 84.24 55.755 ;
     RECT  2.16 56.025 84.24 56.295 ;
     RECT  2.16 56.565 84.24 56.835 ;
     RECT  2.16 57.105 84.24 57.375 ;
     RECT  2.16 57.645 84.24 57.915 ;
     RECT  2.16 58.185 84.24 58.455 ;
     RECT  2.16 58.725 84.24 58.995 ;
     RECT  2.16 59.265 84.24 59.535 ;
     RECT  2.16 59.805 84.24 60.075 ;
     RECT  2.16 60.345 84.24 60.615 ;
     RECT  2.16 60.885 84.24 61.155 ;
     RECT  2.16 61.425 84.24 61.695 ;
     RECT  2.16 61.965 84.24 62.235 ;
     RECT  2.16 62.505 84.24 62.775 ;
     RECT  2.16 63.045 84.24 63.315 ;
     RECT  2.16 63.585 84.24 63.855 ;
     RECT  2.16 64.125 84.24 64.395 ;
     RECT  2.16 64.665 84.24 64.935 ;
     RECT  2.16 65.205 84.24 65.475 ;
     RECT  2.16 65.745 84.24 66.015 ;
     RECT  2.16 66.285 84.24 66.555 ;
     RECT  2.16 66.825 84.24 67.095 ;
     RECT  2.16 67.365 84.24 67.635 ;
     RECT  2.16 67.905 84.24 68.175 ;
     RECT  2.16 68.445 84.24 68.715 ;
     RECT  2.16 68.985 84.24 69.255 ;
     RECT  2.16 69.525 84.24 69.795 ;
     RECT  2.16 70.065 84.24 70.335 ;
     RECT  2.16 70.605 84.24 70.875 ;
     RECT  2.16 71.145 84.24 71.415 ;
     RECT  2.16 71.685 84.24 71.955 ;
     RECT  2.16 72.225 84.24 72.495 ;
     RECT  2.16 72.765 84.24 73.035 ;
     RECT  2.16 73.305 84.24 73.575 ;
     RECT  2.16 73.845 84.24 74.115 ;
     RECT  2.16 74.385 84.24 74.655 ;
     RECT  2.16 74.925 84.24 75.195 ;
     RECT  2.16 75.465 84.24 75.6 ;
    LAYER RVTP ;
     RECT  2.16 2.295 84.24 2.565 ;
     RECT  2.16 2.835 84.24 3.105 ;
     RECT  2.16 3.375 84.24 3.645 ;
     RECT  2.16 3.915 84.24 4.185 ;
     RECT  2.16 4.455 84.24 4.725 ;
     RECT  2.16 4.995 84.24 5.265 ;
     RECT  2.16 5.535 84.24 5.805 ;
     RECT  2.16 6.075 84.24 6.345 ;
     RECT  2.16 6.615 84.24 6.885 ;
     RECT  2.16 7.155 84.24 7.425 ;
     RECT  2.16 7.695 84.24 7.965 ;
     RECT  2.16 8.235 84.24 8.505 ;
     RECT  2.16 8.775 84.24 9.045 ;
     RECT  2.16 9.315 84.24 9.585 ;
     RECT  2.16 9.855 84.24 10.125 ;
     RECT  2.16 10.395 84.24 10.665 ;
     RECT  2.16 10.935 84.24 11.205 ;
     RECT  2.16 11.475 84.24 11.745 ;
     RECT  2.16 12.015 84.24 12.285 ;
     RECT  2.16 12.555 84.24 12.825 ;
     RECT  2.16 13.095 84.24 13.365 ;
     RECT  2.16 13.635 84.24 13.905 ;
     RECT  2.16 14.175 84.24 14.445 ;
     RECT  2.16 14.715 84.24 14.985 ;
     RECT  2.16 15.255 84.24 15.525 ;
     RECT  2.16 15.795 84.24 16.065 ;
     RECT  2.16 16.335 84.24 16.605 ;
     RECT  2.16 16.875 84.24 17.145 ;
     RECT  2.16 17.415 84.24 17.685 ;
     RECT  2.16 17.955 84.24 18.225 ;
     RECT  2.16 18.495 84.24 18.765 ;
     RECT  2.16 19.035 84.24 19.305 ;
     RECT  2.16 19.575 84.24 19.845 ;
     RECT  2.16 20.115 84.24 20.385 ;
     RECT  2.16 20.655 84.24 20.925 ;
     RECT  2.16 21.195 84.24 21.465 ;
     RECT  2.16 21.735 84.24 22.005 ;
     RECT  2.16 22.275 84.24 22.545 ;
     RECT  2.16 22.815 84.24 23.085 ;
     RECT  2.16 23.355 84.24 23.625 ;
     RECT  2.16 23.895 84.24 24.165 ;
     RECT  2.16 24.435 84.24 24.705 ;
     RECT  2.16 24.975 84.24 25.245 ;
     RECT  2.16 25.515 84.24 25.785 ;
     RECT  2.16 26.055 84.24 26.325 ;
     RECT  2.16 26.595 84.24 26.865 ;
     RECT  2.16 27.135 84.24 27.405 ;
     RECT  2.16 27.675 84.24 27.945 ;
     RECT  2.16 28.215 84.24 28.485 ;
     RECT  2.16 28.755 84.24 29.025 ;
     RECT  2.16 29.295 84.24 29.565 ;
     RECT  2.16 29.835 84.24 30.105 ;
     RECT  2.16 30.375 84.24 30.645 ;
     RECT  2.16 30.915 84.24 31.185 ;
     RECT  2.16 31.455 84.24 31.725 ;
     RECT  2.16 31.995 84.24 32.265 ;
     RECT  2.16 32.535 84.24 32.805 ;
     RECT  2.16 33.075 84.24 33.345 ;
     RECT  2.16 33.615 84.24 33.885 ;
     RECT  2.16 34.155 84.24 34.425 ;
     RECT  2.16 34.695 84.24 34.965 ;
     RECT  2.16 35.235 84.24 35.505 ;
     RECT  2.16 35.775 84.24 36.045 ;
     RECT  2.16 36.315 84.24 36.585 ;
     RECT  2.16 36.855 84.24 37.125 ;
     RECT  2.16 37.395 84.24 37.665 ;
     RECT  2.16 37.935 84.24 38.205 ;
     RECT  2.16 38.475 84.24 38.745 ;
     RECT  2.16 39.015 84.24 39.285 ;
     RECT  2.16 39.555 84.24 39.825 ;
     RECT  2.16 40.095 84.24 40.365 ;
     RECT  2.16 40.635 84.24 40.905 ;
     RECT  2.16 41.175 84.24 41.445 ;
     RECT  2.16 41.715 84.24 41.985 ;
     RECT  2.16 42.255 84.24 42.525 ;
     RECT  2.16 42.795 84.24 43.065 ;
     RECT  2.16 43.335 84.24 43.605 ;
     RECT  2.16 43.875 84.24 44.145 ;
     RECT  2.16 44.415 84.24 44.685 ;
     RECT  2.16 44.955 84.24 45.225 ;
     RECT  2.16 45.495 84.24 45.765 ;
     RECT  2.16 46.035 84.24 46.305 ;
     RECT  2.16 46.575 84.24 46.845 ;
     RECT  2.16 47.115 84.24 47.385 ;
     RECT  2.16 47.655 84.24 47.925 ;
     RECT  2.16 48.195 84.24 48.465 ;
     RECT  2.16 48.735 84.24 49.005 ;
     RECT  2.16 49.275 84.24 49.545 ;
     RECT  2.16 49.815 84.24 50.085 ;
     RECT  2.16 50.355 84.24 50.625 ;
     RECT  2.16 50.895 84.24 51.165 ;
     RECT  2.16 51.435 84.24 51.705 ;
     RECT  2.16 51.975 84.24 52.245 ;
     RECT  2.16 52.515 84.24 52.785 ;
     RECT  2.16 53.055 84.24 53.325 ;
     RECT  2.16 53.595 84.24 53.865 ;
     RECT  2.16 54.135 84.24 54.405 ;
     RECT  2.16 54.675 84.24 54.945 ;
     RECT  2.16 55.215 84.24 55.485 ;
     RECT  2.16 55.755 84.24 56.025 ;
     RECT  2.16 56.295 84.24 56.565 ;
     RECT  2.16 56.835 84.24 57.105 ;
     RECT  2.16 57.375 84.24 57.645 ;
     RECT  2.16 57.915 84.24 58.185 ;
     RECT  2.16 58.455 84.24 58.725 ;
     RECT  2.16 58.995 84.24 59.265 ;
     RECT  2.16 59.535 84.24 59.805 ;
     RECT  2.16 60.075 84.24 60.345 ;
     RECT  2.16 60.615 84.24 60.885 ;
     RECT  2.16 61.155 84.24 61.425 ;
     RECT  2.16 61.695 84.24 61.965 ;
     RECT  2.16 62.235 84.24 62.505 ;
     RECT  2.16 62.775 84.24 63.045 ;
     RECT  2.16 63.315 84.24 63.585 ;
     RECT  2.16 63.855 84.24 64.125 ;
     RECT  2.16 64.395 84.24 64.665 ;
     RECT  2.16 64.935 84.24 65.205 ;
     RECT  2.16 65.475 84.24 65.745 ;
     RECT  2.16 66.015 84.24 66.285 ;
     RECT  2.16 66.555 84.24 66.825 ;
     RECT  2.16 67.095 84.24 67.365 ;
     RECT  2.16 67.635 84.24 67.905 ;
     RECT  2.16 68.175 84.24 68.445 ;
     RECT  2.16 68.715 84.24 68.985 ;
     RECT  2.16 69.255 84.24 69.525 ;
     RECT  2.16 69.795 84.24 70.065 ;
     RECT  2.16 70.335 84.24 70.605 ;
     RECT  2.16 70.875 84.24 71.145 ;
     RECT  2.16 71.415 84.24 71.685 ;
     RECT  2.16 71.955 84.24 72.225 ;
     RECT  2.16 72.495 84.24 72.765 ;
     RECT  2.16 73.035 84.24 73.305 ;
     RECT  2.16 73.575 84.24 73.845 ;
     RECT  2.16 74.115 84.24 74.385 ;
     RECT  2.16 74.655 84.24 74.925 ;
     RECT  2.16 75.195 84.24 75.465 ;
    LAYER M1 ;
     RECT  2.16 2.151 84.24 75.609 ;
    LAYER M2 ;
     RECT  2.16 2.151 51.151 75.609 ;
     RECT  51.151 1.962 52.835 75.609 ;
     RECT  52.835 2.034 53.591 75.609 ;
     RECT  56.551 0.216 56.659 0.234 ;
     RECT  56.659 0.216 57.703 0.549 ;
     RECT  53.591 2.151 57.739 75.609 ;
     RECT  57.703 0.18 57.811 0.549 ;
     RECT  57.739 1.728 57.947 75.609 ;
     RECT  57.947 2.151 59.287 75.609 ;
     RECT  57.811 0.108 59.639 0.549 ;
     RECT  59.639 0.108 60.035 0.279 ;
     RECT  59.287 2.106 60.215 75.609 ;
     RECT  60.035 0.108 60.827 0.126 ;
     RECT  60.215 2.151 84.24 75.609 ;
     RECT  84.24 39.528 85.487 39.546 ;
    LAYER M3 ;
     RECT  57.744 0.091 57.762 0.103 ;
     RECT  60.264 0.043 60.282 0.103 ;
     RECT  29.916 0.091 29.934 0.139 ;
     RECT  51.3 0.091 51.318 0.139 ;
     RECT  57.744 0.103 57.834 0.139 ;
     RECT  59.472 0.091 59.49 0.139 ;
     RECT  60.264 0.103 60.822 0.139 ;
     RECT  57.744 0.139 57.87 0.175 ;
     RECT  29.916 0.139 30.078 0.187 ;
     RECT  51.3 0.139 51.606 0.187 ;
     RECT  57.708 0.175 57.978 0.187 ;
     RECT  57.06 0.187 57.978 0.211 ;
     RECT  56.556 0.211 57.978 0.235 ;
     RECT  59.472 0.139 60.822 0.235 ;
     RECT  29.916 0.187 30.15 0.269 ;
     RECT  56.556 0.235 60.822 0.284 ;
     RECT  30.06 0.269 30.15 0.317 ;
     RECT  30.132 0.317 30.15 0.365 ;
     RECT  28.692 0.475 28.71 0.523 ;
     RECT  51.3 0.187 51.858 0.523 ;
     RECT  52.776 0.475 52.794 0.523 ;
     RECT  56.556 0.284 56.682 0.523 ;
     RECT  57.744 0.284 60.822 0.523 ;
     RECT  56.34 0.523 56.682 0.557 ;
     RECT  28.692 0.523 28.998 0.571 ;
     RECT  51.3 0.523 52.794 0.571 ;
     RECT  56.34 0.557 56.358 0.701 ;
     RECT  28.008 0.571 28.998 1.675 ;
     RECT  51.3 0.571 53.01 1.675 ;
     RECT  54.036 1.147 54.054 1.675 ;
     RECT  27.972 1.675 28.998 1.723 ;
     RECT  32.724 0.091 32.742 1.723 ;
     RECT  33.552 0.187 33.57 1.723 ;
     RECT  51.3 1.675 54.054 1.723 ;
     RECT  27.972 1.723 29.322 1.771 ;
     RECT  30.096 1.723 30.402 1.771 ;
     RECT  31.212 1.723 33.75 1.771 ;
     RECT  56.124 1.723 56.142 1.771 ;
     RECT  51.3 1.723 55.242 1.819 ;
     RECT  51.3 1.819 55.314 1.957 ;
     RECT  34.704 1.723 34.722 2.143 ;
     RECT  43.236 1.723 43.254 2.143 ;
     RECT  51.156 1.957 55.314 2.143 ;
     RECT  56.052 1.771 56.142 2.143 ;
     RECT  27.972 1.771 33.966 2.191 ;
     RECT  34.704 2.143 34.905 2.191 ;
     RECT  42.915 2.143 43.254 2.191 ;
     RECT  51.015 2.143 55.314 2.191 ;
     RECT  56.052 2.143 56.505 2.191 ;
     RECT  57.744 0.523 60.966 2.191 ;
     RECT  57.672 2.191 60.966 2.219 ;
     RECT  36.54 2.191 36.558 2.227 ;
     RECT  37.515 2.143 37.605 2.227 ;
     RECT  42.915 2.191 44.082 2.227 ;
     RECT  51.015 2.191 56.754 2.251 ;
     RECT  27.936 2.191 34.905 2.263 ;
     RECT  35.892 2.227 36.558 2.263 ;
     RECT  40.215 2.143 40.305 2.263 ;
     RECT  42.84 2.227 44.082 2.263 ;
     RECT  51.015 2.251 56.898 2.263 ;
     RECT  57.672 2.219 60.894 2.263 ;
     RECT  37.515 2.227 38.25 2.335 ;
     RECT  41.652 2.263 41.67 2.335 ;
     RECT  27.936 2.263 36.558 2.371 ;
     RECT  37.296 2.335 38.502 2.371 ;
     RECT  39.924 2.263 40.305 2.371 ;
     RECT  41.652 2.335 41.778 2.371 ;
     RECT  42.84 2.263 44.154 2.371 ;
     RECT  50.868 2.263 60.894 2.371 ;
     RECT  2.415 2.143 2.505 2.413 ;
     RECT  5.115 2.143 5.205 2.413 ;
     RECT  7.815 2.143 7.905 2.413 ;
     RECT  10.515 2.143 10.605 2.413 ;
     RECT  13.215 2.143 13.305 2.413 ;
     RECT  15.915 2.143 16.005 2.413 ;
     RECT  18.615 2.143 18.705 2.413 ;
     RECT  21.315 2.143 21.405 2.413 ;
     RECT  24.015 2.143 24.105 2.413 ;
     RECT  26.715 2.143 26.805 2.413 ;
     RECT  27.54 2.371 38.502 2.413 ;
     RECT  45.615 2.143 45.705 2.413 ;
     RECT  48.315 2.143 48.405 2.413 ;
     RECT  61.815 2.143 61.905 2.413 ;
     RECT  64.515 2.143 64.605 2.413 ;
     RECT  67.215 2.143 67.305 2.413 ;
     RECT  69.915 2.143 70.005 2.413 ;
     RECT  72.615 2.143 72.705 2.413 ;
     RECT  75.315 2.143 75.405 2.413 ;
     RECT  78.015 2.143 78.105 2.413 ;
     RECT  80.715 2.143 80.805 2.413 ;
     RECT  83.415 2.143 83.505 2.413 ;
     RECT  26.715 2.413 38.502 2.461 ;
     RECT  47.232 2.371 47.25 2.488 ;
     RECT  50.688 2.371 60.894 2.489 ;
     RECT  45.615 2.413 45.897 2.491 ;
     RECT  39.492 2.371 44.154 2.525 ;
     RECT  45.615 2.491 46.422 2.569 ;
     RECT  45.432 2.569 46.422 2.605 ;
     RECT  48.315 2.413 48.597 2.605 ;
     RECT  50.688 2.489 60.858 2.605 ;
     RECT  26.715 2.461 38.574 2.641 ;
     RECT  39.492 2.525 40.914 2.641 ;
     RECT  41.724 2.525 44.154 2.641 ;
     RECT  45.216 2.605 46.422 2.641 ;
     RECT  47.232 2.488 47.502 2.641 ;
     RECT  48.315 2.605 48.762 2.641 ;
     RECT  50.256 2.605 60.858 2.641 ;
     RECT  41.724 2.641 60.858 3.029 ;
     RECT  41.724 3.029 60.822 3.299 ;
     RECT  41.724 3.299 60.75 3.335 ;
     RECT  26.715 2.641 40.914 3.379 ;
     RECT  41.724 3.335 60.498 3.379 ;
     RECT  26.715 3.379 60.498 3.811 ;
     RECT  26.352 3.811 60.498 3.955 ;
     RECT  26.1 3.955 60.498 4.081 ;
     RECT  25.92 4.081 60.498 4.157 ;
     RECT  26.064 4.157 60.498 4.253 ;
     RECT  26.064 4.253 60.318 4.451 ;
     RECT  67.215 2.413 67.497 4.999 ;
     RECT  67.215 4.999 67.554 5.035 ;
     RECT  26.1 4.451 60.318 5.069 ;
     RECT  63.288 5.071 63.306 5.189 ;
     RECT  67.032 5.035 67.554 5.305 ;
     RECT  39.924 5.069 60.318 5.341 ;
     RECT  66.6 5.305 67.554 5.459 ;
     RECT  39.924 5.341 60.462 5.539 ;
     RECT  39.924 5.539 60.93 5.575 ;
     RECT  66.6 5.459 67.497 5.597 ;
     RECT  39.924 5.575 61.002 5.611 ;
     RECT  61.815 2.413 62.097 5.611 ;
     RECT  39.924 5.611 62.097 5.809 ;
     RECT  24.015 2.413 24.297 5.845 ;
     RECT  24.015 5.845 24.822 5.881 ;
     RECT  26.1 5.069 39.078 5.881 ;
     RECT  64.515 2.413 64.797 5.881 ;
     RECT  39.924 5.809 62.442 5.999 ;
     RECT  24.015 5.881 39.078 6.091 ;
     RECT  61.2 5.999 62.442 6.115 ;
     RECT  64.26 5.881 64.797 6.115 ;
     RECT  23.868 6.091 39.078 6.179 ;
     RECT  24.015 6.179 39.078 6.241 ;
     RECT  39.924 5.999 60.318 6.241 ;
     RECT  61.2 6.115 62.586 6.313 ;
     RECT  61.2 6.313 63.09 6.523 ;
     RECT  64.116 6.115 64.797 6.523 ;
     RECT  24.015 6.241 60.318 6.781 ;
     RECT  61.2 6.523 64.797 6.781 ;
     RECT  65.556 6.691 65.898 6.781 ;
     RECT  66.636 5.597 67.497 6.781 ;
     RECT  69.048 6.691 69.066 6.817 ;
     RECT  65.556 6.781 67.497 7.087 ;
     RECT  24.015 6.781 64.797 7.123 ;
     RECT  65.556 7.087 68.022 7.133 ;
     RECT  23.904 7.123 64.797 7.259 ;
     RECT  65.556 7.133 67.497 7.259 ;
     RECT  23.904 7.259 38.934 7.421 ;
     RECT  23.904 7.421 38.826 7.435 ;
     RECT  68.976 6.817 69.066 7.501 ;
     RECT  69.915 2.413 70.197 7.501 ;
     RECT  23.832 7.435 38.826 7.529 ;
     RECT  68.976 7.501 70.197 7.619 ;
     RECT  22.86 7.897 22.878 8.041 ;
     RECT  23.832 7.529 38.358 8.041 ;
     RECT  69.012 7.619 70.197 8.311 ;
     RECT  69.012 8.311 70.254 8.429 ;
     RECT  21.315 2.413 21.597 8.437 ;
     RECT  39.672 7.259 64.797 8.491 ;
     RECT  21.315 8.437 21.87 8.509 ;
     RECT  22.86 8.041 38.358 8.509 ;
     RECT  39.564 8.491 64.797 8.545 ;
     RECT  21.315 8.509 38.358 8.581 ;
     RECT  39.312 8.545 64.797 8.581 ;
     RECT  69.084 8.429 70.254 8.699 ;
     RECT  21.315 8.581 64.797 8.815 ;
     RECT  21.315 8.815 65.322 8.851 ;
     RECT  21.315 8.851 65.43 8.941 ;
     RECT  66.204 7.259 67.497 8.941 ;
     RECT  21.315 8.941 67.497 8.969 ;
     RECT  61.02 8.969 67.497 9.239 ;
     RECT  68.22 7.231 68.238 9.391 ;
     RECT  69.084 8.699 70.197 9.391 ;
     RECT  21.315 8.969 60.282 9.419 ;
     RECT  61.02 9.239 64.962 9.419 ;
     RECT  65.772 9.239 67.497 9.451 ;
     RECT  68.22 9.391 70.197 9.451 ;
     RECT  58.716 9.419 60.282 10.049 ;
     RECT  61.815 9.419 64.962 10.049 ;
     RECT  65.772 9.451 70.197 10.049 ;
     RECT  21.315 9.419 57.978 10.165 ;
     RECT  58.716 10.049 59.454 10.165 ;
     RECT  68.22 10.049 70.197 10.589 ;
     RECT  19.8 10.267 19.818 10.625 ;
     RECT  20.772 10.165 59.454 10.741 ;
     RECT  69.048 10.589 70.197 10.829 ;
     RECT  60.192 10.049 60.282 10.831 ;
     RECT  61.02 9.419 61.038 10.831 ;
     RECT  20.268 10.741 59.454 10.895 ;
     RECT  20.268 10.895 20.466 11.399 ;
     RECT  21.315 10.895 59.454 11.551 ;
     RECT  60.192 10.831 61.038 11.551 ;
     RECT  20.448 11.399 20.466 11.947 ;
     RECT  21.315 11.551 61.038 11.947 ;
     RECT  69.084 10.829 70.197 12.187 ;
     RECT  68.22 10.589 68.274 12.28 ;
     RECT  69.012 12.187 70.197 12.28 ;
     RECT  68.22 12.28 70.197 12.317 ;
     RECT  69.012 12.317 70.197 12.557 ;
     RECT  20.448 11.947 61.038 13.559 ;
     RECT  42.084 13.559 61.038 13.711 ;
     RECT  61.815 10.049 64.797 13.711 ;
     RECT  20.448 13.559 41.274 14.521 ;
     RECT  42.084 13.711 64.797 14.521 ;
     RECT  20.448 14.521 64.797 15.061 ;
     RECT  65.772 10.049 67.497 15.061 ;
     RECT  20.448 15.061 67.497 15.719 ;
     RECT  25.452 15.719 67.497 16.105 ;
     RECT  68.22 12.317 68.274 16.105 ;
     RECT  20.448 15.719 24.606 16.501 ;
     RECT  20.448 16.501 24.678 16.573 ;
     RECT  25.452 16.105 68.274 16.573 ;
     RECT  20.448 16.573 68.274 16.979 ;
     RECT  69.084 12.557 70.197 17.113 ;
     RECT  20.556 16.979 68.274 17.383 ;
     RECT  69.084 17.113 70.686 17.383 ;
     RECT  20.556 17.383 70.686 17.491 ;
     RECT  20.556 17.491 70.722 18.499 ;
     RECT  18.615 2.413 18.897 18.535 ;
     RECT  20.34 18.499 70.722 18.535 ;
     RECT  18.615 18.535 19.386 18.571 ;
     RECT  20.34 18.535 71.046 18.571 ;
     RECT  20.268 18.571 71.046 18.689 ;
     RECT  18.615 18.571 19.53 18.763 ;
     RECT  20.268 18.689 43.902 18.763 ;
     RECT  44.748 18.689 71.046 19.031 ;
     RECT  44.784 19.031 71.046 19.615 ;
     RECT  18.615 18.763 43.902 19.651 ;
     RECT  18.615 19.651 43.938 19.805 ;
     RECT  20.34 19.805 43.938 19.841 ;
     RECT  20.484 19.841 43.938 19.921 ;
     RECT  44.784 19.615 71.226 19.921 ;
     RECT  20.484 19.921 71.226 20.147 ;
     RECT  20.52 20.147 71.226 20.345 ;
     RECT  18.615 19.805 19.602 20.875 ;
     RECT  20.52 20.345 71.046 20.875 ;
     RECT  18.615 20.875 71.046 21.235 ;
     RECT  18.615 21.235 71.334 21.739 ;
     RECT  18.615 21.739 71.442 21.775 ;
     RECT  18.615 21.775 71.478 23.657 ;
     RECT  19.836 23.657 71.478 24.359 ;
     RECT  19.908 24.359 71.478 24.629 ;
     RECT  20.016 24.629 71.478 26.291 ;
     RECT  20.952 26.291 71.478 26.699 ;
     RECT  21.06 26.699 71.478 26.789 ;
     RECT  21.315 26.789 71.478 27.203 ;
     RECT  20.016 26.291 20.034 27.239 ;
     RECT  25.92 27.203 71.478 27.473 ;
     RECT  21.315 27.203 25.002 27.599 ;
     RECT  21.315 27.599 22.194 27.635 ;
     RECT  22.968 27.599 25.002 27.635 ;
     RECT  23.04 27.635 25.002 27.905 ;
     RECT  23.148 27.905 25.002 28.139 ;
     RECT  23.148 28.139 23.166 28.175 ;
     RECT  26.208 27.473 71.478 28.175 ;
     RECT  23.94 28.139 25.002 28.211 ;
     RECT  26.208 28.175 68.058 28.255 ;
     RECT  68.796 28.175 71.478 28.493 ;
     RECT  24.015 28.211 25.002 28.517 ;
     RECT  24.015 28.517 24.39 28.553 ;
     RECT  25.992 28.255 68.058 28.957 ;
     RECT  25.992 28.957 68.274 29.035 ;
     RECT  69.012 28.493 71.478 29.489 ;
     RECT  25.848 29.035 68.274 29.525 ;
     RECT  25.992 29.525 68.274 29.561 ;
     RECT  27.864 29.561 68.274 29.605 ;
     RECT  69.012 29.489 71.046 29.605 ;
     RECT  27.864 29.605 71.046 30.029 ;
     RECT  27.864 30.029 70.83 30.299 ;
     RECT  27.864 30.299 70.722 30.335 ;
     RECT  27.864 30.335 70.506 30.407 ;
     RECT  25.992 29.561 26.997 30.955 ;
     RECT  27.864 30.407 70.434 30.955 ;
     RECT  25.992 30.955 70.434 30.992 ;
     RECT  27.864 30.992 70.434 31.153 ;
     RECT  27.864 31.153 70.83 31.189 ;
     RECT  27.864 31.189 71.226 31.765 ;
     RECT  72.615 2.413 72.897 31.801 ;
     RECT  27.864 31.765 71.334 31.963 ;
     RECT  72.108 31.801 72.897 31.963 ;
     RECT  75.315 2.413 75.597 32.161 ;
     RECT  75.315 32.161 75.834 32.341 ;
     RECT  74.844 32.341 75.834 32.773 ;
     RECT  74.844 32.773 76.122 33.385 ;
     RECT  24.015 28.553 24.354 33.421 ;
     RECT  27.864 31.963 72.897 33.511 ;
     RECT  23.688 33.421 24.354 33.539 ;
     RECT  23.688 33.539 24.297 33.583 ;
     RECT  73.728 33.511 73.746 33.619 ;
     RECT  74.52 33.385 76.122 33.619 ;
     RECT  23.508 33.583 24.297 33.629 ;
     RECT  27.864 33.511 72.99 33.655 ;
     RECT  73.728 33.619 76.122 33.655 ;
     RECT  27.864 33.655 76.122 33.917 ;
     RECT  27.864 33.917 72.897 34.795 ;
     RECT  73.728 33.917 76.122 34.795 ;
     RECT  27.864 34.795 76.122 36.121 ;
     RECT  25.992 30.992 26.997 36.523 ;
     RECT  25.992 36.523 27.018 36.661 ;
     RECT  27.864 36.121 76.158 36.661 ;
     RECT  78.015 2.413 78.297 36.859 ;
     RECT  25.992 36.661 76.158 37.085 ;
     RECT  25.992 37.085 72.954 38.011 ;
     RECT  73.728 37.085 76.158 38.011 ;
     RECT  77.364 36.859 78.297 38.173 ;
     RECT  25.992 38.011 76.158 38.201 ;
     RECT  25.992 38.201 72.954 38.309 ;
     RECT  77.292 38.173 78.297 38.309 ;
     RECT  86.292 38.347 86.31 38.477 ;
     RECT  29.088 38.309 72.954 39.091 ;
     RECT  73.692 38.201 76.158 39.091 ;
     RECT  82.404 38.137 82.422 39.209 ;
     RECT  83.415 2.413 83.697 39.289 ;
     RECT  29.088 39.091 76.158 39.389 ;
     RECT  73.728 39.389 76.158 39.451 ;
     RECT  83.415 39.289 84.042 39.479 ;
     RECT  85.464 39.355 85.482 39.551 ;
     RECT  29.088 39.389 72.954 40.019 ;
     RECT  29.088 40.019 62.874 40.289 ;
     RECT  64.116 40.019 72.954 40.531 ;
     RECT  73.728 39.451 76.446 40.531 ;
     RECT  64.116 40.531 76.446 40.675 ;
     RECT  64.116 40.675 76.626 40.981 ;
     RECT  29.088 40.289 62.838 41.099 ;
     RECT  25.992 38.309 28.35 41.605 ;
     RECT  29.088 41.099 62.73 41.605 ;
     RECT  25.992 41.605 62.73 41.645 ;
     RECT  64.008 40.981 76.626 41.683 ;
     RECT  29.088 41.645 62.73 41.989 ;
     RECT  29.088 41.989 62.946 42.061 ;
     RECT  63.792 41.683 76.626 42.061 ;
     RECT  29.088 42.061 76.77 42.179 ;
     RECT  29.088 42.179 52.542 42.359 ;
     RECT  53.28 42.179 76.77 42.485 ;
     RECT  53.316 42.485 76.77 42.565 ;
     RECT  53.316 42.565 76.986 42.791 ;
     RECT  29.088 42.359 52.002 42.827 ;
     RECT  53.316 42.791 76.95 42.989 ;
     RECT  63.792 42.989 76.95 43.061 ;
     RECT  29.088 42.827 51.966 43.277 ;
     RECT  53.316 42.989 63.054 43.291 ;
     RECT  63.936 43.061 76.95 43.367 ;
     RECT  52.884 43.291 63.054 43.531 ;
     RECT  49.752 43.277 51.966 43.645 ;
     RECT  52.848 43.531 63.054 43.645 ;
     RECT  49.752 43.645 63.054 43.879 ;
     RECT  49.752 43.879 63.162 43.943 ;
     RECT  61.668 43.943 63.162 44.041 ;
     RECT  63.936 43.367 76.914 44.041 ;
     RECT  61.668 44.041 76.914 44.213 ;
     RECT  29.088 43.277 49.014 44.221 ;
     RECT  49.752 43.943 60.894 44.221 ;
     RECT  61.668 44.213 76.698 44.339 ;
     RECT  29.088 44.221 60.894 44.789 ;
     RECT  58.104 44.789 60.894 45.019 ;
     RECT  61.668 44.339 76.554 45.019 ;
     RECT  58.104 45.019 76.554 45.419 ;
     RECT  58.104 45.419 76.23 45.491 ;
     RECT  58.104 45.491 76.086 45.563 ;
     RECT  58.716 45.563 76.086 45.599 ;
     RECT  29.088 44.789 57.33 45.661 ;
     RECT  29.088 45.661 57.942 46.309 ;
     RECT  58.716 45.599 75.69 46.309 ;
     RECT  29.088 46.309 75.69 46.499 ;
     RECT  29.088 46.499 75.597 47.183 ;
     RECT  29.088 47.183 74.214 47.309 ;
     RECT  25.992 41.645 28.35 47.323 ;
     RECT  29.088 47.309 74.178 47.323 ;
     RECT  25.992 47.323 74.178 47.345 ;
     RECT  74.088 47.345 74.178 47.381 ;
     RECT  25.992 47.345 73.242 47.417 ;
     RECT  25.992 47.417 73.17 47.453 ;
     RECT  74.088 47.381 74.106 47.453 ;
     RECT  25.992 47.453 72.897 47.687 ;
     RECT  66.816 47.687 72.897 47.849 ;
     RECT  66.816 47.849 71.694 48.155 ;
     RECT  25.992 47.687 66.078 48.469 ;
     RECT  66.816 48.155 71.442 48.469 ;
     RECT  25.992 48.469 71.442 48.659 ;
     RECT  25.992 48.659 71.082 48.929 ;
     RECT  25.992 48.929 70.29 48.965 ;
     RECT  25.992 48.965 38.43 49.469 ;
     RECT  39.24 48.965 70.29 50.045 ;
     RECT  39.24 50.045 70.254 50.621 ;
     RECT  25.992 49.469 38.394 50.819 ;
     RECT  41.364 50.621 70.254 51.089 ;
     RECT  41.364 51.089 70.197 51.835 ;
     RECT  41.22 51.835 70.197 51.899 ;
     RECT  41.22 51.899 41.238 52.013 ;
     RECT  42.012 51.899 70.197 52.043 ;
     RECT  42.192 52.043 70.197 52.349 ;
     RECT  42.192 52.349 44.334 52.475 ;
     RECT  42.192 52.475 43.794 52.547 ;
     RECT  42.192 52.547 43.722 52.709 ;
     RECT  45.615 52.349 70.197 52.709 ;
     RECT  56.124 52.709 70.197 52.853 ;
     RECT  56.124 52.853 68.454 52.889 ;
     RECT  69.3 52.853 70.197 53.015 ;
     RECT  56.124 52.889 68.382 53.321 ;
     RECT  56.124 53.321 68.094 53.393 ;
     RECT  45.615 52.709 55.314 53.671 ;
     RECT  56.124 53.393 67.95 53.671 ;
     RECT  45.615 53.671 67.95 53.897 ;
     RECT  45.615 53.897 67.554 53.933 ;
     RECT  65.736 53.933 67.554 53.969 ;
     RECT  45.615 53.933 64.926 54.715 ;
     RECT  65.736 53.969 67.497 54.715 ;
     RECT  45.615 54.715 67.497 54.905 ;
     RECT  55.944 54.905 67.497 55.589 ;
     RECT  34.632 50.819 38.394 55.679 ;
     RECT  64.515 55.589 67.497 55.679 ;
     RECT  55.944 55.589 63.666 55.715 ;
     RECT  55.944 55.715 62.73 55.759 ;
     RECT  63.648 55.715 63.666 55.787 ;
     RECT  55.908 55.759 62.73 55.795 ;
     RECT  55.728 55.795 62.73 55.949 ;
     RECT  64.515 55.679 66.438 55.949 ;
     RECT  64.515 55.949 66.042 55.985 ;
     RECT  55.728 55.949 57.834 56.129 ;
     RECT  45.615 54.905 54.99 56.191 ;
     RECT  55.728 56.129 57.438 56.191 ;
     RECT  58.824 55.949 62.298 56.219 ;
     RECT  45.615 56.191 57.438 56.237 ;
     RECT  58.824 56.219 61.074 56.327 ;
     RECT  61.815 56.219 62.298 56.327 ;
     RECT  64.515 55.985 65.07 56.327 ;
     RECT  66.024 55.985 66.042 56.327 ;
     RECT  58.824 56.327 60.786 56.363 ;
     RECT  45.615 56.237 54.99 56.489 ;
     RECT  55.8 56.237 57.438 56.489 ;
     RECT  60.264 56.363 60.282 56.489 ;
     RECT  55.872 56.489 56.97 56.525 ;
     RECT  58.824 56.363 59.397 56.525 ;
     RECT  45.615 56.489 54.054 56.633 ;
     RECT  56.304 56.525 56.697 56.759 ;
     RECT  54.972 56.489 54.99 56.795 ;
     RECT  34.632 55.679 38.286 56.875 ;
     RECT  39.24 50.621 40.497 56.875 ;
     RECT  47.268 56.633 54.054 57.065 ;
     RECT  47.268 57.065 53.997 57.299 ;
     RECT  47.664 57.299 52.902 57.371 ;
     RECT  53.676 57.299 53.997 57.371 ;
     RECT  34.632 56.875 40.497 57.389 ;
     RECT  48.315 57.371 52.902 57.479 ;
     RECT  48.315 57.479 51.606 57.569 ;
     RECT  48.315 57.569 51.354 57.605 ;
     RECT  48.315 57.605 49.842 57.641 ;
     RECT  48.315 57.641 49.806 57.713 ;
     RECT  50.688 57.605 51.297 57.749 ;
     RECT  49.788 57.713 49.806 57.839 ;
     RECT  50.832 57.749 51.297 57.839 ;
     RECT  25.992 50.819 33.894 60.115 ;
     RECT  34.632 57.389 38.178 60.115 ;
     RECT  25.2 66.361 25.218 66.451 ;
     RECT  25.056 66.451 25.218 66.479 ;
     RECT  25.992 60.115 38.178 66.479 ;
     RECT  25.056 66.479 25.074 66.509 ;
     RECT  26.136 66.479 38.178 66.659 ;
     RECT  26.208 66.659 38.178 67.559 ;
     RECT  26.316 67.559 38.178 68.369 ;
     RECT  26.496 68.369 38.178 68.909 ;
     RECT  26.676 68.909 38.178 68.981 ;
     RECT  26.715 68.981 38.178 70.367 ;
     RECT  27.756 70.367 38.178 70.403 ;
     RECT  39.24 57.389 40.497 70.529 ;
     RECT  39.78 70.529 40.497 71.609 ;
     RECT  28.26 70.403 38.178 71.645 ;
     RECT  33.552 71.645 38.178 71.725 ;
     RECT  33.552 71.725 38.538 71.761 ;
     RECT  28.26 71.645 32.814 71.803 ;
     RECT  33.552 71.761 38.718 72.149 ;
     RECT  28.188 71.803 32.814 72.265 ;
     RECT  28.008 72.265 32.814 72.841 ;
     RECT  33.552 72.149 38.178 72.841 ;
     RECT  28.008 72.841 38.178 73.471 ;
     RECT  26.715 70.367 26.997 73.483 ;
     RECT  27.9 73.471 38.178 73.483 ;
     RECT  26.715 73.483 38.178 73.769 ;
     RECT  26.715 73.769 37.797 74.683 ;
     RECT  42.192 52.709 43.197 74.683 ;
     RECT  26.568 74.683 37.797 74.849 ;
     RECT  42.192 74.683 43.29 74.849 ;
     RECT  42.192 74.849 43.254 74.921 ;
     RECT  26.715 74.849 37.797 75.155 ;
     RECT  27.792 75.155 37.797 75.227 ;
     RECT  2.415 2.413 2.697 75.347 ;
     RECT  5.115 2.413 5.397 75.347 ;
     RECT  7.815 2.413 8.097 75.347 ;
     RECT  10.515 2.413 10.797 75.347 ;
     RECT  13.215 2.413 13.497 75.347 ;
     RECT  15.915 2.413 16.197 75.347 ;
     RECT  18.615 23.657 18.897 75.347 ;
     RECT  21.315 27.635 21.597 75.347 ;
     RECT  24.015 33.629 24.297 75.347 ;
     RECT  26.715 75.155 26.997 75.347 ;
     RECT  27.792 75.227 36.162 75.347 ;
     RECT  37.008 75.227 37.797 75.347 ;
     RECT  40.215 71.609 40.497 75.347 ;
     RECT  45.615 56.633 45.897 75.347 ;
     RECT  48.315 57.713 48.597 75.347 ;
     RECT  51.015 57.839 51.297 75.347 ;
     RECT  53.715 57.371 53.997 75.347 ;
     RECT  56.415 56.759 56.697 75.347 ;
     RECT  59.115 56.525 59.397 75.347 ;
     RECT  61.815 56.327 62.097 75.347 ;
     RECT  64.515 56.327 64.797 75.347 ;
     RECT  67.215 55.679 67.497 75.347 ;
     RECT  69.915 53.015 70.197 75.347 ;
     RECT  72.615 47.849 72.897 75.347 ;
     RECT  75.315 47.183 75.597 75.347 ;
     RECT  78.015 38.309 78.297 75.347 ;
     RECT  80.715 2.413 80.997 75.347 ;
     RECT  83.415 39.479 83.697 75.347 ;
     RECT  26.715 75.347 26.874 75.389 ;
     RECT  27.792 75.347 34.905 75.389 ;
     RECT  35.676 75.347 36.162 75.389 ;
     RECT  37.008 75.347 37.605 75.389 ;
     RECT  42.915 74.921 43.254 75.389 ;
     RECT  35.676 75.389 36.018 75.425 ;
     RECT  33.768 75.389 34.905 75.569 ;
     RECT  2.415 75.347 2.505 75.617 ;
     RECT  5.115 75.347 5.205 75.617 ;
     RECT  7.815 75.347 7.905 75.617 ;
     RECT  10.515 75.347 10.605 75.617 ;
     RECT  13.215 75.347 13.305 75.617 ;
     RECT  15.915 75.347 16.005 75.617 ;
     RECT  18.615 75.347 18.705 75.617 ;
     RECT  21.315 75.347 21.405 75.617 ;
     RECT  24.015 75.347 24.105 75.617 ;
     RECT  26.715 75.389 26.805 75.617 ;
     RECT  33.948 75.569 34.905 75.617 ;
     RECT  37.515 75.389 37.605 75.617 ;
     RECT  40.215 75.347 40.305 75.617 ;
     RECT  42.915 75.389 43.074 75.617 ;
     RECT  45.615 75.347 45.705 75.617 ;
     RECT  48.315 75.347 48.405 75.617 ;
     RECT  51.015 75.347 51.105 75.617 ;
     RECT  53.715 75.347 53.805 75.617 ;
     RECT  56.415 75.347 56.505 75.617 ;
     RECT  59.115 75.347 59.205 75.617 ;
     RECT  61.815 75.347 61.905 75.617 ;
     RECT  64.515 75.347 64.605 75.617 ;
     RECT  67.215 75.347 67.305 75.617 ;
     RECT  69.915 75.347 70.005 75.617 ;
     RECT  72.615 75.347 72.705 75.617 ;
     RECT  75.315 75.347 75.405 75.617 ;
     RECT  78.015 75.347 78.105 75.617 ;
     RECT  80.715 75.347 80.805 75.617 ;
     RECT  83.415 75.347 83.505 75.617 ;
     RECT  35.676 75.425 35.694 75.725 ;
     RECT  43.056 75.617 43.074 75.725 ;
     RECT  27.792 75.389 32.922 75.773 ;
     RECT  27.792 75.773 29.214 75.821 ;
     RECT  29.988 75.773 31.698 75.821 ;
     RECT  32.436 75.773 32.922 75.821 ;
     RECT  33.948 75.617 34.29 75.821 ;
     RECT  32.472 75.821 32.922 75.917 ;
     RECT  27.792 75.821 27.81 77.645 ;
     RECT  32.904 75.917 32.922 77.645 ;
     RECT  33.984 75.821 34.002 77.645 ;
    LAYER M4 ;
     RECT  2.408 2.148 2.512 75.612 ;
     RECT  2.512 2.418 2.704 75.342 ;
     RECT  5.108 2.148 5.212 75.612 ;
     RECT  5.212 2.418 5.404 75.342 ;
     RECT  7.808 2.148 7.912 75.612 ;
     RECT  7.912 2.418 8.104 75.342 ;
     RECT  10.508 2.148 10.612 75.612 ;
     RECT  10.612 2.418 10.804 75.342 ;
     RECT  13.208 2.148 13.312 75.612 ;
     RECT  13.312 2.418 13.504 75.342 ;
     RECT  15.908 2.148 16.012 75.612 ;
     RECT  16.012 2.418 16.204 75.342 ;
     RECT  18.608 2.148 18.712 75.612 ;
     RECT  18.712 2.418 18.904 75.342 ;
     RECT  18.904 19.968 19.397 19.992 ;
     RECT  18.904 21.648 19.969 21.672 ;
     RECT  19.969 21.36 20.009 21.672 ;
     RECT  20.009 21.36 20.293 21.384 ;
     RECT  18.904 10.272 20.761 10.296 ;
     RECT  20.761 10.272 21.308 10.392 ;
     RECT  18.904 18.768 21.308 18.792 ;
     RECT  20.293 20.88 21.308 21.384 ;
     RECT  20.113 22.464 21.308 22.488 ;
     RECT  20.545 23.952 21.308 23.976 ;
     RECT  20.437 26.256 21.308 26.28 ;
     RECT  21.308 2.148 21.412 75.612 ;
     RECT  21.412 2.418 21.604 75.342 ;
     RECT  21.604 7.968 21.737 10.392 ;
     RECT  21.604 25.056 22.313 27.384 ;
     RECT  21.604 13.584 22.421 13.608 ;
     RECT  22.313 25.056 22.529 25.752 ;
     RECT  21.737 7.968 22.547 9.672 ;
     RECT  21.604 20.88 22.817 22.584 ;
     RECT  21.604 15.552 22.844 15.576 ;
     RECT  21.604 11.808 22.853 11.928 ;
     RECT  22.817 21.696 22.885 22.584 ;
     RECT  22.547 7.968 22.889 7.992 ;
     RECT  22.844 14.784 22.921 15.576 ;
     RECT  22.921 14.112 22.931 15.576 ;
     RECT  22.669 10.752 23.137 10.776 ;
     RECT  22.853 11.808 23.137 11.832 ;
     RECT  21.604 23.808 23.18 24.024 ;
     RECT  21.604 18.24 23.281 18.264 ;
     RECT  22.313 27.36 23.353 27.384 ;
     RECT  23.281 17.616 23.852 18.696 ;
     RECT  23.857 6.096 23.893 6.12 ;
     RECT  23.821 7.44 23.893 7.464 ;
     RECT  23.852 17.568 23.893 18.696 ;
     RECT  23.893 20.064 24.001 20.088 ;
     RECT  22.885 21.696 24.001 22.632 ;
     RECT  23.893 6.096 24.008 7.464 ;
     RECT  23.785 8.448 24.008 8.472 ;
     RECT  22.547 9.648 24.008 9.672 ;
     RECT  23.137 10.752 24.008 11.832 ;
     RECT  23.173 13.056 24.008 13.08 ;
     RECT  22.931 14.112 24.008 14.136 ;
     RECT  22.931 15.552 24.008 15.576 ;
     RECT  23.893 17.472 24.008 18.696 ;
     RECT  24.001 20.064 24.008 22.632 ;
     RECT  23.18 23.76 24.008 24.024 ;
     RECT  22.705 25.008 24.008 25.032 ;
     RECT  23.353 26.832 24.008 27.384 ;
     RECT  23.497 33.6 24.008 33.624 ;
     RECT  23.557 36.528 24.008 36.552 ;
     RECT  24.008 2.148 24.112 75.612 ;
     RECT  24.112 2.418 24.304 75.342 ;
     RECT  24.304 12.576 24.419 14.136 ;
     RECT  24.304 19.248 24.419 22.248 ;
     RECT  24.304 6.096 24.545 7.944 ;
     RECT  24.545 6.096 24.581 6.888 ;
     RECT  24.304 10.896 24.581 11.4 ;
     RECT  24.419 20.064 24.725 22.248 ;
     RECT  24.725 21.312 24.803 22.248 ;
     RECT  24.545 7.92 24.833 7.944 ;
     RECT  24.725 20.064 24.833 20.088 ;
     RECT  24.304 23.904 24.941 27.192 ;
     RECT  24.941 25.056 25.085 27.192 ;
     RECT  25.085 25.056 25.409 25.08 ;
     RECT  24.419 13.536 25.573 14.136 ;
     RECT  25.573 13.536 25.669 14.328 ;
     RECT  25.085 26.736 25.697 27.192 ;
     RECT  24.304 15.984 25.715 16.008 ;
     RECT  24.581 11.376 25.909 11.4 ;
     RECT  25.729 19.296 25.909 19.32 ;
     RECT  24.941 23.904 25.909 23.928 ;
     RECT  25.297 9.6 25.945 9.624 ;
     RECT  24.803 22.224 26.053 22.248 ;
     RECT  25.909 23.904 26.053 24.072 ;
     RECT  24.581 6.864 26.089 6.888 ;
     RECT  25.945 9.6 26.125 9.768 ;
     RECT  25.909 11.376 26.125 12.024 ;
     RECT  25.669 13.536 26.125 14.808 ;
     RECT  24.304 16.992 26.125 17.64 ;
     RECT  24.304 66.48 26.125 66.504 ;
     RECT  26.089 6.24 26.149 6.888 ;
     RECT  25.297 8.16 26.149 8.184 ;
     RECT  26.125 9.6 26.149 14.808 ;
     RECT  26.125 16.992 26.233 17.976 ;
     RECT  26.125 66.48 26.305 66.6 ;
     RECT  25.909 19.248 26.341 19.32 ;
     RECT  25.909 20.592 26.341 20.616 ;
     RECT  26.149 9.504 26.377 14.808 ;
     RECT  26.053 22.128 26.449 22.248 ;
     RECT  26.053 23.904 26.485 24.6 ;
     RECT  26.449 21.84 26.593 22.248 ;
     RECT  26.485 23.904 26.593 24.696 ;
     RECT  25.909 4.128 26.708 4.152 ;
     RECT  26.149 6.24 26.708 8.184 ;
     RECT  26.377 9.504 26.708 15.336 ;
     RECT  26.233 16.608 26.708 17.976 ;
     RECT  26.341 19.248 26.708 20.616 ;
     RECT  26.593 21.84 26.708 24.696 ;
     RECT  25.697 26.832 26.708 26.856 ;
     RECT  25.837 29.04 26.708 29.064 ;
     RECT  24.304 36.528 26.708 36.552 ;
     RECT  26.089 41.136 26.708 41.16 ;
     RECT  26.305 66.48 26.708 67.32 ;
     RECT  26.557 74.688 26.708 74.712 ;
     RECT  26.708 2.148 26.812 75.612 ;
     RECT  26.812 2.418 27.004 75.342 ;
     RECT  27.004 36.528 27.029 36.936 ;
     RECT  27.004 9.936 27.065 10.632 ;
     RECT  27.004 66.144 27.065 67.32 ;
     RECT  27.004 2.832 27.155 8.76 ;
     RECT  27.004 14.112 27.155 17.976 ;
     RECT  27.004 24.96 27.155 26.856 ;
     RECT  27.065 66.144 27.155 66.6 ;
     RECT  27.004 12.288 27.173 13.08 ;
     RECT  27.004 22.224 27.209 23.976 ;
     RECT  27.155 24.96 27.209 26.808 ;
     RECT  27.209 23.04 27.245 23.976 ;
     RECT  27.004 20.352 27.395 21.192 ;
     RECT  27.245 23.136 27.461 23.976 ;
     RECT  27.173 12.288 27.533 12.792 ;
     RECT  27.004 28.272 27.731 29.064 ;
     RECT  27.209 24.96 27.923 25.944 ;
     RECT  27.004 41.136 27.923 41.64 ;
     RECT  27.004 74.688 27.925 75.342 ;
     RECT  27.155 4.944 27.997 8.76 ;
     RECT  27.065 9.936 27.997 10.296 ;
     RECT  27.925 74.688 28.033 75.576 ;
     RECT  27.155 14.208 28.037 17.976 ;
     RECT  27.997 4.944 28.045 10.296 ;
     RECT  27.461 23.376 28.069 23.976 ;
     RECT  27.923 24.96 28.069 25.56 ;
     RECT  27.004 73.488 28.076 73.512 ;
     RECT  27.997 0.576 28.105 0.6 ;
     RECT  27.961 1.68 28.105 1.704 ;
     RECT  28.076 72.912 28.117 73.512 ;
     RECT  28.033 74.688 28.117 75.624 ;
     RECT  28.117 72.912 28.124 75.624 ;
     RECT  28.124 72.576 28.133 75.624 ;
     RECT  28.105 0.576 28.141 1.704 ;
     RECT  27.781 77.616 28.163 77.64 ;
     RECT  28.141 0.576 28.177 1.752 ;
     RECT  27.155 2.832 28.177 3.288 ;
     RECT  28.069 23.376 28.181 25.56 ;
     RECT  28.133 71.808 28.205 75.624 ;
     RECT  27.155 66.576 28.211 66.6 ;
     RECT  28.045 4.944 28.213 10.2 ;
     RECT  28.205 71.808 28.217 75.816 ;
     RECT  27.533 12.288 28.249 12.312 ;
     RECT  28.213 4.752 28.253 10.2 ;
     RECT  28.253 4.752 28.364 10.152 ;
     RECT  28.037 14.208 28.429 14.856 ;
     RECT  27.004 19.248 28.465 19.368 ;
     RECT  28.249 11.424 28.501 12.312 ;
     RECT  28.429 13.296 28.501 14.856 ;
     RECT  28.177 0.576 28.585 3.288 ;
     RECT  27.923 41.136 28.933 41.256 ;
     RECT  27.731 29.04 28.969 29.064 ;
     RECT  28.681 0.48 29.027 0.552 ;
     RECT  28.609 47.328 29.029 47.352 ;
     RECT  28.037 15.984 29.077 17.976 ;
     RECT  28.465 19.248 29.077 19.896 ;
     RECT  28.585 1.728 29.113 3.288 ;
     RECT  28.364 4.512 29.113 10.152 ;
     RECT  29.125 77.52 29.221 77.544 ;
     RECT  28.501 21.696 29.269 21.72 ;
     RECT  27.029 36.912 29.269 36.936 ;
     RECT  28.217 72.336 29.269 75.816 ;
     RECT  29.077 15.984 29.365 19.896 ;
     RECT  29.269 21.12 29.365 21.72 ;
     RECT  29.113 1.728 29.408 10.152 ;
     RECT  28.501 11.424 29.408 14.856 ;
     RECT  29.365 15.984 29.408 21.72 ;
     RECT  28.181 23.376 29.408 24.936 ;
     RECT  29.329 27.168 29.408 27.192 ;
     RECT  28.969 29.04 29.408 29.64 ;
     RECT  27.004 30.96 29.408 30.984 ;
     RECT  29.269 36.816 29.408 36.936 ;
     RECT  28.933 41.136 29.408 41.64 ;
     RECT  29.029 46.512 29.408 47.352 ;
     RECT  29.005 51.456 29.408 51.48 ;
     RECT  27.004 68.88 29.408 68.904 ;
     RECT  28.825 70.656 29.408 70.68 ;
     RECT  29.269 72.24 29.408 75.816 ;
     RECT  29.221 77.52 29.507 77.592 ;
     RECT  29.027 0.48 29.699 0.504 ;
     RECT  29.408 1.728 29.704 75.816 ;
     RECT  29.704 27.168 29.765 27.432 ;
     RECT  29.704 75.696 29.795 75.816 ;
     RECT  29.749 0.288 29.845 0.36 ;
     RECT  29.845 0.192 29.89 0.36 ;
     RECT  29.704 16.032 29.945 22.584 ;
     RECT  29.89 0.096 29.989 0.36 ;
     RECT  29.704 69.744 30.089 69.864 ;
     RECT  29.989 0.144 30.122 0.36 ;
     RECT  30.122 0.192 30.161 0.36 ;
     RECT  30.161 0.192 30.179 0.312 ;
     RECT  30.179 0.192 30.205 0.216 ;
     RECT  29.704 28.416 30.233 29.64 ;
     RECT  29.704 68.448 30.269 68.472 ;
     RECT  29.704 70.992 30.275 74.616 ;
     RECT  30.233 28.416 30.305 28.968 ;
     RECT  29.507 77.568 30.563 77.592 ;
     RECT  29.704 24.912 30.697 25.656 ;
     RECT  29.704 11.328 30.701 14.808 ;
     RECT  30.275 71.76 30.757 74.616 ;
     RECT  30.757 71.76 30.809 74.712 ;
     RECT  30.701 11.328 30.845 14.136 ;
     RECT  29.945 16.032 30.869 19.416 ;
     RECT  30.86 56.112 30.901 56.136 ;
     RECT  30.901 56.112 30.947 57.048 ;
     RECT  30.809 71.808 30.949 74.712 ;
     RECT  29.795 75.744 30.949 75.816 ;
     RECT  29.704 1.728 30.985 10.296 ;
     RECT  30.845 11.328 30.985 13.656 ;
     RECT  30.869 15.408 30.995 19.416 ;
     RECT  29.945 20.64 31.021 22.584 ;
     RECT  29.704 23.616 31.021 23.64 ;
     RECT  29.704 31.92 31.057 31.944 ;
     RECT  30.995 18.768 31.061 19.416 ;
     RECT  31.021 20.64 31.065 23.64 ;
     RECT  30.697 70.272 31.093 70.296 ;
     RECT  29.704 35.328 31.165 35.352 ;
     RECT  30.697 24.912 31.237 26.376 ;
     RECT  29.765 27.408 31.237 27.432 ;
     RECT  31.093 39.312 31.237 39.336 ;
     RECT  29.704 41.136 31.237 41.256 ;
     RECT  29.704 46.512 31.237 47.304 ;
     RECT  31.093 69.456 31.285 70.296 ;
     RECT  31.129 38.16 31.333 38.184 ;
     RECT  31.237 39.312 31.333 41.256 ;
     RECT  29.704 36.816 31.34 36.936 ;
     RECT  31.057 31.92 31.343 32.28 ;
     RECT  31.333 38.16 31.345 41.256 ;
     RECT  31.343 31.92 31.381 32.424 ;
     RECT  31.165 35.328 31.417 35.4 ;
     RECT  30.305 28.416 31.453 28.488 ;
     RECT  31.417 34.368 31.453 35.4 ;
     RECT  31.34 36.48 31.484 36.936 ;
     RECT  31.484 36.48 31.489 37.032 ;
     RECT  31.345 38.16 31.489 41.4 ;
     RECT  31.381 31.152 31.561 32.424 ;
     RECT  31.237 24.912 31.717 27.432 ;
     RECT  31.453 28.416 31.717 29.16 ;
     RECT  30.985 1.728 31.813 13.656 ;
     RECT  31.621 0.144 31.909 0.168 ;
     RECT  31.285 69.456 31.909 70.776 ;
     RECT  30.949 71.808 31.909 75.816 ;
     RECT  31.561 31.152 31.957 32.52 ;
     RECT  31.021 44.784 31.957 44.904 ;
     RECT  31.237 46.176 31.957 47.304 ;
     RECT  31.453 34.176 32.029 35.4 ;
     RECT  31.813 1.728 32.108 14.04 ;
     RECT  30.995 15.408 32.108 17.688 ;
     RECT  31.061 18.768 32.108 19.32 ;
     RECT  31.065 20.544 32.108 23.64 ;
     RECT  31.717 24.912 32.108 29.16 ;
     RECT  31.957 30.576 32.108 32.52 ;
     RECT  32.029 33.552 32.108 35.4 ;
     RECT  31.489 36.48 32.108 41.4 ;
     RECT  31.957 42.816 32.108 42.84 ;
     RECT  31.957 43.824 32.108 44.904 ;
     RECT  31.957 46.032 32.108 47.304 ;
     RECT  31.633 49.008 32.108 49.032 ;
     RECT  31.909 50.304 32.108 50.328 ;
     RECT  29.704 51.456 32.108 51.48 ;
     RECT  30.947 57.024 32.108 57.048 ;
     RECT  31.909 69.456 32.108 75.816 ;
     RECT  32.108 1.728 32.149 75.816 ;
     RECT  31.909 0.144 32.195 0.264 ;
     RECT  32.195 0.144 32.341 0.216 ;
     RECT  31.909 77.568 32.341 77.592 ;
     RECT  32.149 1.728 32.404 75.912 ;
     RECT  32.404 15.456 32.465 19.368 ;
     RECT  32.404 36.528 32.465 43.032 ;
     RECT  32.404 69.984 32.465 75.912 ;
     RECT  32.465 70.992 32.501 75.912 ;
     RECT  32.465 36.528 32.537 41.16 ;
     RECT  32.404 20.64 32.609 31.8 ;
     RECT  32.465 69.984 32.609 70.008 ;
     RECT  32.609 29.76 32.681 31.8 ;
     RECT  32.537 38.64 32.681 41.16 ;
     RECT  32.341 0.096 32.753 0.216 ;
     RECT  32.681 29.76 32.753 30.6 ;
     RECT  32.609 20.64 32.789 28.44 ;
     RECT  32.404 33.072 32.897 35.304 ;
     RECT  32.681 39.312 32.915 41.16 ;
     RECT  32.465 42.192 33.005 43.032 ;
     RECT  32.465 15.504 33.011 19.368 ;
     RECT  32.897 33.072 33.077 34.776 ;
     RECT  32.341 77.568 33.109 77.64 ;
     RECT  32.915 39.312 33.149 39.336 ;
     RECT  32.404 14.16 33.221 14.184 ;
     RECT  32.404 50.832 33.229 51.336 ;
     RECT  33.077 34.752 33.293 34.776 ;
     RECT  32.404 45.792 33.293 46.056 ;
     RECT  33.109 77.424 33.347 77.64 ;
     RECT  33.347 77.568 33.395 77.64 ;
     RECT  33.005 43.008 33.397 43.032 ;
     RECT  33.011 15.504 33.437 19.32 ;
     RECT  33.437 15.504 33.469 17.688 ;
     RECT  32.537 36.528 33.505 37.656 ;
     RECT  32.753 0.144 33.581 0.216 ;
     RECT  33.581 0.144 33.683 0.168 ;
     RECT  32.501 70.992 33.685 75.288 ;
     RECT  33.469 15.456 33.689 17.688 ;
     RECT  33.397 43.008 33.725 43.176 ;
     RECT  32.789 20.976 33.781 28.44 ;
     RECT  33.781 20.976 33.829 29.064 ;
     RECT  32.753 30.576 33.829 30.6 ;
     RECT  32.404 1.728 33.833 13.08 ;
     RECT  33.685 70.992 33.932 75.576 ;
     RECT  33.077 33.072 33.937 33.768 ;
     RECT  33.932 70.416 33.937 75.576 ;
     RECT  33.689 15.456 33.973 17.64 ;
     RECT  33.395 77.616 34.013 77.64 ;
     RECT  33.829 20.976 34.021 30.6 ;
     RECT  32.681 31.728 34.021 31.8 ;
     RECT  33.937 70.416 34.076 75.816 ;
     RECT  33.437 18.864 34.117 19.32 ;
     RECT  34.021 20.976 34.117 31.8 ;
     RECT  34.117 18.864 34.261 19.944 ;
     RECT  34.117 20.928 34.261 31.8 ;
     RECT  34.076 70.08 34.345 75.816 ;
     RECT  34.261 18.864 34.405 31.8 ;
     RECT  33.973 14.64 34.453 17.64 ;
     RECT  33.505 36.528 34.657 38.232 ;
     RECT  33.725 43.152 34.657 43.176 ;
     RECT  34.453 14.208 34.729 17.64 ;
     RECT  33.833 1.728 34.733 11.448 ;
     RECT  34.733 2.148 34.808 11.448 ;
     RECT  33.833 12.48 34.808 13.08 ;
     RECT  34.729 14.208 34.808 17.688 ;
     RECT  34.405 18.816 34.808 31.8 ;
     RECT  33.937 33.024 34.808 33.768 ;
     RECT  34.657 36.336 34.808 38.232 ;
     RECT  32.915 41.136 34.808 41.16 ;
     RECT  34.657 43.152 34.808 44.184 ;
     RECT  33.293 46.032 34.808 46.056 ;
     RECT  34.477 47.904 34.808 48.456 ;
     RECT  33.229 50.832 34.808 50.856 ;
     RECT  33.829 65.184 34.808 65.208 ;
     RECT  34.345 70.08 34.808 75.72 ;
     RECT  34.808 2.148 34.912 75.72 ;
     RECT  34.912 2.256 35.104 75.72 ;
     RECT  35.104 33.024 35.129 33.288 ;
     RECT  35.104 62.64 35.219 62.664 ;
     RECT  35.104 70.704 35.219 75.72 ;
     RECT  35.104 2.256 35.273 12.792 ;
     RECT  35.104 25.104 35.273 26.808 ;
     RECT  35.273 2.256 35.309 12.312 ;
     RECT  35.104 48.432 35.363 49.608 ;
     RECT  35.104 50.736 35.363 50.856 ;
     RECT  35.104 52.176 35.363 52.2 ;
     RECT  35.104 27.888 35.417 28.488 ;
     RECT  35.104 20.544 35.453 23.688 ;
     RECT  35.104 14.64 35.489 19.512 ;
     RECT  35.273 25.392 35.489 26.808 ;
     RECT  35.309 2.256 35.525 11.928 ;
     RECT  35.104 31.776 35.525 31.8 ;
     RECT  35.129 33.024 35.525 33.144 ;
     RECT  35.525 2.256 35.555 10.344 ;
     RECT  35.104 34.944 35.633 42.792 ;
     RECT  35.219 71.04 35.705 75.72 ;
     RECT  35.705 71.04 35.795 75.288 ;
     RECT  35.633 34.944 35.813 38.088 ;
     RECT  35.104 44.16 35.813 44.184 ;
     RECT  35.104 46.032 35.891 47.112 ;
     RECT  35.363 49.008 35.891 49.608 ;
     RECT  35.555 2.256 35.921 8.616 ;
     RECT  35.891 46.128 35.932 47.112 ;
     RECT  35.555 9.696 35.957 10.344 ;
     RECT  35.489 14.64 35.957 16.392 ;
     RECT  35.813 35.856 35.957 38.088 ;
     RECT  35.957 36.528 35.987 38.088 ;
     RECT  35.489 17.616 36.029 19.512 ;
     RECT  35.987 36.816 36.029 38.088 ;
     RECT  35.633 39.168 36.029 42.792 ;
     RECT  35.932 46.752 36.097 47.112 ;
     RECT  35.957 16.32 36.101 16.392 ;
     RECT  36.097 46.752 36.101 47.448 ;
     RECT  35.921 2.832 36.209 8.616 ;
     RECT  36.029 39.456 36.245 42.792 ;
     RECT  35.891 49.584 36.277 49.608 ;
     RECT  35.795 71.04 36.323 72.408 ;
     RECT  36.277 34.8 36.349 34.824 ;
     RECT  35.957 14.64 36.353 14.664 ;
     RECT  36.209 2.832 36.389 7.8 ;
     RECT  36.349 30.24 36.457 30.264 ;
     RECT  35.957 9.696 36.467 9.72 ;
     RECT  35.489 25.392 36.493 26.76 ;
     RECT  36.493 25.392 36.529 26.856 ;
     RECT  36.593 66.72 36.62 66.744 ;
     RECT  36.62 52.944 36.661 52.968 ;
     RECT  35.104 54.624 36.661 54.648 ;
     RECT  35.453 20.544 36.673 23.64 ;
     RECT  36.529 25.344 36.673 26.856 ;
     RECT  36.101 16.368 36.805 16.392 ;
     RECT  36.029 17.616 36.805 19.32 ;
     RECT  35.525 11.616 36.853 11.928 ;
     RECT  36.457 29.52 36.925 30.264 ;
     RECT  36.349 34.608 36.925 34.824 ;
     RECT  35.417 28.464 36.961 28.488 ;
     RECT  36.925 29.52 36.961 31.176 ;
     RECT  36.101 47.088 36.961 47.448 ;
     RECT  36.277 49.584 37.004 50.04 ;
     RECT  36.673 20.544 37.033 26.856 ;
     RECT  36.961 28.464 37.033 31.176 ;
     RECT  35.525 33.024 37.045 33.048 ;
     RECT  36.925 34.56 37.045 34.824 ;
     RECT  37.045 33.024 37.093 34.824 ;
     RECT  36.853 10.704 37.105 11.928 ;
     RECT  36.805 16.368 37.141 19.32 ;
     RECT  37.033 20.544 37.141 31.176 ;
     RECT  37.093 33.024 37.141 35.4 ;
     RECT  36.245 39.456 37.177 39.48 ;
     RECT  35.104 55.92 37.249 55.944 ;
     RECT  36.457 13.296 37.321 13.32 ;
     RECT  36.853 9.072 37.357 9.24 ;
     RECT  37.177 38.736 37.381 39.48 ;
     RECT  36.245 40.656 37.381 42.792 ;
     RECT  37.093 15.072 37.465 15.096 ;
     RECT  36.389 2.832 37.508 3.48 ;
     RECT  36.389 4.512 37.508 7.8 ;
     RECT  37.357 9.024 37.508 9.24 ;
     RECT  37.105 10.704 37.508 11.976 ;
     RECT  37.321 13.056 37.508 13.32 ;
     RECT  37.465 14.4 37.508 15.096 ;
     RECT  37.141 16.368 37.508 31.176 ;
     RECT  37.141 32.208 37.508 35.4 ;
     RECT  36.029 36.816 37.508 37.08 ;
     RECT  37.381 38.736 37.508 42.792 ;
     RECT  36.961 47.088 37.508 47.88 ;
     RECT  37.004 49.152 37.508 50.04 ;
     RECT  36.661 51.984 37.508 52.968 ;
     RECT  36.661 54.336 37.508 54.648 ;
     RECT  37.249 55.92 37.508 56.904 ;
     RECT  35.104 65.184 37.508 65.208 ;
     RECT  36.62 66.72 37.508 66.936 ;
     RECT  36.323 71.04 37.508 72.12 ;
     RECT  35.795 73.488 37.508 75.288 ;
     RECT  37.508 2.148 37.612 75.612 ;
     RECT  37.612 2.418 37.804 75.342 ;
     RECT  37.804 4.416 37.865 10.728 ;
     RECT  37.865 4.416 37.955 10.056 ;
     RECT  37.804 11.952 37.955 11.976 ;
     RECT  37.804 12.96 37.955 13.08 ;
     RECT  37.804 14.4 37.973 15.432 ;
     RECT  37.804 18.768 38.009 25.08 ;
     RECT  37.955 4.416 38.051 7.368 ;
     RECT  38.051 6.864 38.153 7.368 ;
     RECT  37.973 14.832 38.153 15.432 ;
     RECT  37.955 8.448 38.189 10.056 ;
     RECT  37.804 26.64 38.297 31.848 ;
     RECT  38.009 22.8 38.369 25.08 ;
     RECT  37.804 38.256 38.369 44.472 ;
     RECT  38.369 38.256 38.441 38.28 ;
     RECT  37.804 36.144 38.483 37.08 ;
     RECT  37.804 2.832 38.513 3.432 ;
     RECT  37.804 70.128 38.627 70.68 ;
     RECT  37.804 71.904 38.627 71.928 ;
     RECT  38.153 6.864 38.657 7.224 ;
     RECT  37.955 13.056 38.657 13.08 ;
     RECT  38.369 22.848 38.657 25.08 ;
     RECT  37.804 56.88 38.693 57.384 ;
     RECT  38.693 57.024 38.723 57.384 ;
     RECT  38.627 70.128 38.723 70.152 ;
     RECT  38.723 57.024 38.771 57.048 ;
     RECT  38.051 4.416 38.801 5.784 ;
     RECT  38.153 15.168 38.905 15.432 ;
     RECT  38.297 28.08 38.905 31.848 ;
     RECT  37.804 33.36 38.905 34.728 ;
     RECT  37.804 45.744 38.977 45.768 ;
     RECT  38.009 18.768 38.981 21.576 ;
     RECT  38.483 36.96 39.013 37.08 ;
     RECT  38.369 39.456 39.049 44.472 ;
     RECT  38.977 45.696 39.049 45.768 ;
     RECT  37.804 16.848 39.085 17.688 ;
     RECT  38.981 18.768 39.085 19.08 ;
     RECT  38.905 28.08 39.157 34.728 ;
     RECT  39.049 39.456 39.161 45.768 ;
     RECT  39.161 39.456 39.203 45.72 ;
     RECT  39.157 28.08 39.265 35.64 ;
     RECT  38.189 8.928 39.301 10.056 ;
     RECT  39.203 39.456 39.337 44.472 ;
     RECT  39.301 8.928 39.481 10.92 ;
     RECT  39.481 8.832 39.553 10.92 ;
     RECT  38.905 15.168 39.589 15.864 ;
     RECT  39.085 16.848 39.589 19.08 ;
     RECT  38.657 6.864 39.644 7.176 ;
     RECT  39.553 8.496 39.644 10.92 ;
     RECT  39.589 15.168 39.661 19.08 ;
     RECT  38.513 3.312 39.692 3.432 ;
     RECT  38.801 4.416 39.692 5.352 ;
     RECT  38.657 23.088 39.733 25.08 ;
     RECT  38.297 26.64 39.733 26.664 ;
     RECT  39.265 27.888 39.805 35.64 ;
     RECT  39.013 36.96 39.877 37.656 ;
     RECT  39.337 38.736 39.877 44.472 ;
     RECT  39.692 3.312 39.887 5.352 ;
     RECT  39.887 2.832 39.973 5.352 ;
     RECT  39.644 6.864 40.021 10.92 ;
     RECT  40.021 6.864 40.049 10.968 ;
     RECT  40.049 12.72 40.093 12.744 ;
     RECT  39.973 2.832 40.208 5.784 ;
     RECT  40.049 6.864 40.208 11.4 ;
     RECT  40.093 12.72 40.208 13.128 ;
     RECT  39.661 14.928 40.208 19.08 ;
     RECT  38.981 20.064 40.208 21.576 ;
     RECT  39.733 23.088 40.208 26.664 ;
     RECT  39.805 27.888 40.208 35.736 ;
     RECT  39.877 36.96 40.208 44.472 ;
     RECT  39.203 45.696 40.208 45.72 ;
     RECT  37.804 47.136 40.208 48.696 ;
     RECT  37.804 51.984 40.208 52.008 ;
     RECT  40.208 2.148 40.312 75.612 ;
     RECT  40.312 2.418 40.504 75.342 ;
     RECT  40.504 31.488 40.565 32.232 ;
     RECT  40.504 18.144 40.601 19.08 ;
     RECT  40.504 21.216 40.673 26.664 ;
     RECT  40.504 35.328 40.781 39.288 ;
     RECT  40.781 37.872 40.961 39.288 ;
     RECT  40.504 13.104 40.997 13.128 ;
     RECT  40.673 21.216 41.033 25.896 ;
     RECT  41.033 21.216 41.069 23.64 ;
     RECT  40.504 27.696 41.069 30.12 ;
     RECT  40.565 32.208 41.069 32.232 ;
     RECT  41.069 21.552 41.113 23.64 ;
     RECT  40.781 35.328 41.213 36.6 ;
     RECT  40.504 51.84 41.249 52.008 ;
     RECT  40.504 50.592 41.267 50.616 ;
     RECT  40.504 14.784 41.357 15.288 ;
     RECT  41.113 22.8 41.393 23.64 ;
     RECT  40.504 33.552 41.497 34.248 ;
     RECT  41.213 35.328 41.497 36.12 ;
     RECT  41.497 33.552 41.533 36.12 ;
     RECT  40.504 46.464 41.537 46.632 ;
     RECT  41.069 27.888 41.569 30.12 ;
     RECT  41.569 27.888 41.677 30.36 ;
     RECT  41.249 51.84 41.681 51.864 ;
     RECT  41.033 24.672 41.713 25.896 ;
     RECT  40.504 40.368 41.717 42.888 ;
     RECT  41.533 32.496 41.747 36.12 ;
     RECT  40.504 2.832 41.753 5.496 ;
     RECT  41.113 21.552 41.753 21.672 ;
     RECT  41.753 2.88 41.797 5.496 ;
     RECT  40.504 6.816 41.797 6.84 ;
     RECT  41.797 2.88 41.857 6.84 ;
     RECT  40.504 8.496 41.857 10.92 ;
     RECT  41.785 11.952 41.857 11.976 ;
     RECT  41.677 27.888 42.001 31.224 ;
     RECT  41.393 22.8 42.253 23.448 ;
     RECT  41.537 46.464 42.397 46.536 ;
     RECT  42.253 22.704 42.408 23.448 ;
     RECT  41.713 24.672 42.408 26.808 ;
     RECT  41.857 2.88 42.433 11.976 ;
     RECT  40.601 18.144 42.476 18.984 ;
     RECT  42.325 20.112 42.476 20.136 ;
     RECT  41.747 35.328 42.685 36.12 ;
     RECT  42.613 51.12 42.721 51.144 ;
     RECT  42.433 2.88 42.757 12.36 ;
     RECT  42.649 13.392 42.757 13.416 ;
     RECT  42.001 27.888 42.757 31.512 ;
     RECT  41.747 32.496 42.757 34.248 ;
     RECT  42.397 45.504 42.757 46.536 ;
     RECT  40.504 16.896 42.793 16.92 ;
     RECT  42.757 2.88 42.908 13.416 ;
     RECT  41.357 15.264 42.908 15.288 ;
     RECT  42.793 16.8 42.908 16.92 ;
     RECT  42.476 18.144 42.908 20.136 ;
     RECT  41.753 21.648 42.908 21.672 ;
     RECT  42.408 22.704 42.908 26.808 ;
     RECT  42.757 27.888 42.908 34.248 ;
     RECT  42.685 35.328 42.908 36.216 ;
     RECT  40.961 37.872 42.908 39.24 ;
     RECT  41.717 40.368 42.908 42.744 ;
     RECT  42.757 45.504 42.908 47.064 ;
     RECT  40.504 48.672 42.908 48.696 ;
     RECT  42.721 51.12 42.908 51.672 ;
     RECT  42.908 2.148 43.045 75.612 ;
     RECT  43.045 2.148 43.141 75.72 ;
     RECT  43.141 1.728 43.187 75.72 ;
     RECT  43.187 1.728 43.204 75.342 ;
     RECT  43.204 23.28 43.229 23.976 ;
     RECT  43.204 1.728 43.265 5.304 ;
     RECT  43.204 20.112 43.331 21.672 ;
     RECT  43.204 74.688 43.345 74.712 ;
     RECT  43.204 28.464 43.373 32.04 ;
     RECT  43.204 6.816 43.379 12.264 ;
     RECT  43.204 46.752 43.379 48.696 ;
     RECT  43.373 28.944 43.409 31.752 ;
     RECT  43.204 33.36 43.409 33.96 ;
     RECT  43.409 28.992 43.517 31.752 ;
     RECT  43.409 33.84 43.553 33.96 ;
     RECT  43.204 50.784 43.553 52.44 ;
     RECT  43.331 21.648 43.589 21.672 ;
     RECT  43.517 30.672 43.589 31.704 ;
     RECT  43.379 48.432 43.625 48.696 ;
     RECT  43.204 25.056 43.733 25.224 ;
     RECT  43.204 13.392 43.763 13.656 ;
     RECT  43.379 8.832 43.805 12.264 ;
     RECT  43.331 20.112 43.877 20.328 ;
     RECT  43.379 46.752 43.877 47.256 ;
     RECT  43.733 25.056 43.913 25.08 ;
     RECT  43.877 46.752 43.949 46.776 ;
     RECT  43.204 38.16 43.985 41.736 ;
     RECT  43.204 16.656 44.021 18.216 ;
     RECT  43.379 6.816 44.197 7.704 ;
     RECT  43.265 2.688 44.305 5.304 ;
     RECT  44.197 6.528 44.305 7.704 ;
     RECT  43.204 26.208 44.305 26.808 ;
     RECT  43.204 35.424 44.341 35.88 ;
     RECT  43.204 37.008 44.341 37.08 ;
     RECT  44.305 2.688 44.345 7.704 ;
     RECT  43.985 40.608 44.377 41.736 ;
     RECT  43.204 43.536 44.377 43.56 ;
     RECT  44.345 2.688 44.381 7.416 ;
     RECT  44.377 40.608 44.381 43.56 ;
     RECT  43.553 50.784 44.381 52.152 ;
     RECT  43.204 15.264 44.413 15.288 ;
     RECT  44.381 2.688 44.483 7.224 ;
     RECT  44.341 35.424 44.483 37.08 ;
     RECT  43.763 13.488 44.489 13.656 ;
     RECT  44.305 26.208 44.489 27.336 ;
     RECT  44.483 35.712 44.521 37.08 ;
     RECT  43.985 38.16 44.521 39.624 ;
     RECT  43.589 30.672 44.525 30.888 ;
     RECT  44.381 40.848 44.525 43.56 ;
     RECT  43.229 23.952 44.629 23.976 ;
     RECT  44.525 41.088 44.665 43.56 ;
     RECT  44.413 15.264 44.677 15.432 ;
     RECT  44.021 16.656 44.677 17.208 ;
     RECT  43.517 28.992 44.701 29.64 ;
     RECT  43.553 33.84 44.809 33.864 ;
     RECT  44.665 41.088 44.809 43.704 ;
     RECT  44.629 23.952 44.917 24.504 ;
     RECT  44.489 26.208 44.917 26.232 ;
     RECT  44.737 32.736 44.953 32.76 ;
     RECT  44.521 35.712 44.989 39.624 ;
     RECT  43.625 48.672 44.989 48.696 ;
     RECT  44.483 2.688 45.157 7.176 ;
     RECT  44.489 13.488 45.169 13.512 ;
     RECT  44.701 28.992 45.169 29.88 ;
     RECT  44.953 46.8 45.169 46.824 ;
     RECT  43.877 20.304 45.313 20.328 ;
     RECT  44.737 22.752 45.313 22.776 ;
     RECT  44.917 23.952 45.313 26.232 ;
     RECT  43.805 8.832 45.349 11.976 ;
     RECT  45.169 13.008 45.349 13.512 ;
     RECT  44.489 27.312 45.601 27.336 ;
     RECT  45.169 28.512 45.601 29.88 ;
     RECT  45.157 2.592 45.608 7.176 ;
     RECT  45.349 8.832 45.608 13.512 ;
     RECT  44.677 15.264 45.608 17.208 ;
     RECT  45.313 20.112 45.608 20.328 ;
     RECT  45.313 22.752 45.608 26.232 ;
     RECT  45.601 27.312 45.608 29.88 ;
     RECT  44.953 31.2 45.608 32.76 ;
     RECT  44.809 33.84 45.608 34.728 ;
     RECT  44.989 35.712 45.608 39.864 ;
     RECT  44.809 41.088 45.608 43.896 ;
     RECT  45.169 46.8 45.608 47.352 ;
     RECT  44.989 48.432 45.608 48.696 ;
     RECT  44.381 50.784 45.608 50.952 ;
     RECT  44.381 52.128 45.608 52.152 ;
     RECT  45.608 2.148 45.712 75.612 ;
     RECT  45.712 2.418 45.904 75.342 ;
     RECT  45.904 2.496 45.965 17.352 ;
     RECT  45.904 23.136 46.019 29.016 ;
     RECT  45.904 35.376 46.045 35.928 ;
     RECT  45.965 2.496 46.109 10.344 ;
     RECT  46.019 23.136 46.109 28.968 ;
     RECT  45.904 31.2 46.109 34.344 ;
     RECT  46.045 35.712 46.163 35.928 ;
     RECT  46.109 2.496 46.181 9 ;
     RECT  46.109 23.136 46.181 26.232 ;
     RECT  46.109 31.2 46.181 33.048 ;
     RECT  45.904 20.304 46.217 20.328 ;
     RECT  45.904 37.008 46.253 39.864 ;
     RECT  46.181 26.208 46.325 26.232 ;
     RECT  46.181 2.496 46.397 7.416 ;
     RECT  46.253 38.784 46.433 39.864 ;
     RECT  45.965 11.376 46.469 17.352 ;
     RECT  46.469 11.376 46.721 17.304 ;
     RECT  46.181 23.136 46.721 24.984 ;
     RECT  46.181 8.832 46.739 9 ;
     RECT  45.904 54.336 46.757 56.328 ;
     RECT  46.721 15.984 46.829 17.304 ;
     RECT  46.721 11.376 46.865 14.952 ;
     RECT  45.904 40.848 46.865 43.56 ;
     RECT  46.109 27.312 46.937 28.968 ;
     RECT  45.904 45.84 46.937 51.72 ;
     RECT  46.109 9.984 47.113 10.344 ;
     RECT  46.937 49.728 47.221 51.72 ;
     RECT  47.185 52.848 47.221 52.872 ;
     RECT  47.149 18.576 47.261 19.032 ;
     RECT  47.221 49.728 47.261 52.872 ;
     RECT  46.397 2.496 47.297 7.176 ;
     RECT  47.261 49.776 47.297 52.872 ;
     RECT  46.739 8.832 47.329 8.904 ;
     RECT  47.261 19.008 47.329 19.032 ;
     RECT  47.113 9.984 47.333 10.392 ;
     RECT  47.329 19.008 47.333 19.272 ;
     RECT  47.297 49.776 47.333 52.296 ;
     RECT  46.163 35.808 47.413 35.928 ;
     RECT  46.253 37.008 47.413 37.704 ;
     RECT  46.937 45.84 47.437 48.744 ;
     RECT  46.181 31.488 47.545 33.048 ;
     RECT  46.433 39.504 47.545 39.864 ;
     RECT  46.865 40.848 47.545 42.024 ;
     RECT  47.545 39.504 47.581 42.024 ;
     RECT  47.413 35.808 47.605 37.704 ;
     RECT  47.297 5.04 47.617 7.176 ;
     RECT  47.329 8.16 47.617 8.904 ;
     RECT  47.333 10.08 47.617 10.392 ;
     RECT  46.865 11.376 47.617 14.232 ;
     RECT  47.605 35.376 47.689 37.704 ;
     RECT  46.757 54.336 47.725 54.36 ;
     RECT  47.689 35.376 47.845 38.232 ;
     RECT  47.581 39.36 47.845 42.024 ;
     RECT  47.545 31.488 47.869 33.24 ;
     RECT  46.721 23.136 47.941 24.36 ;
     RECT  47.617 10.08 48.013 14.232 ;
     RECT  47.833 20.256 48.121 20.28 ;
     RECT  48.013 10.08 48.157 14.664 ;
     RECT  46.829 15.984 48.181 17.064 ;
     RECT  47.333 19.248 48.181 19.272 ;
     RECT  48.121 20.256 48.181 20.904 ;
     RECT  48.181 19.248 48.265 20.904 ;
     RECT  48.265 19.248 48.301 21.192 ;
     RECT  47.297 2.496 48.308 3.96 ;
     RECT  47.617 5.04 48.308 8.904 ;
     RECT  48.157 10.08 48.308 14.856 ;
     RECT  48.181 15.984 48.308 18.024 ;
     RECT  48.301 19.248 48.308 21.528 ;
     RECT  47.941 23.04 48.308 24.36 ;
     RECT  46.937 28.224 48.308 28.968 ;
     RECT  47.869 30.96 48.308 33.24 ;
     RECT  46.109 34.32 48.308 34.344 ;
     RECT  47.845 35.376 48.308 42.024 ;
     RECT  46.865 43.056 48.308 43.56 ;
     RECT  47.437 45.792 48.308 48.744 ;
     RECT  47.333 49.776 48.308 51.24 ;
     RECT  47.333 52.224 48.308 52.296 ;
     RECT  47.725 54.336 48.308 54.888 ;
     RECT  46.757 56.064 48.308 56.328 ;
     RECT  48.308 2.148 48.412 75.612 ;
     RECT  48.412 2.418 48.604 75.342 ;
     RECT  48.604 45.024 48.665 46.104 ;
     RECT  48.604 38.448 48.845 40.872 ;
     RECT  48.604 2.784 48.899 7.224 ;
     RECT  48.899 2.832 48.989 7.224 ;
     RECT  48.604 42 48.989 42.024 ;
     RECT  48.604 57.024 48.989 57.144 ;
     RECT  48.604 25.824 49.025 25.848 ;
     RECT  48.989 3.36 49.169 7.224 ;
     RECT  48.665 45.024 49.169 46.056 ;
     RECT  49.169 45.024 49.205 45.816 ;
     RECT  48.604 48.48 49.277 52.248 ;
     RECT  48.989 57.12 49.385 57.144 ;
     RECT  49.169 4.128 49.475 7.224 ;
     RECT  48.604 8.208 49.493 11.976 ;
     RECT  48.604 22.944 49.565 23.928 ;
     RECT  48.604 27.072 49.573 29.736 ;
     RECT  48.604 30.96 49.573 31.8 ;
     RECT  49.475 4.128 49.601 6.84 ;
     RECT  49.601 4.128 49.637 5.16 ;
     RECT  49.601 6.384 49.637 6.84 ;
     RECT  48.604 33.12 49.637 35.4 ;
     RECT  49.277 50.832 49.637 52.248 ;
     RECT  49.637 52.224 49.669 52.248 ;
     RECT  49.637 4.128 49.673 4.968 ;
     RECT  48.845 38.448 49.705 40.44 ;
     RECT  48.604 54.096 49.705 55.128 ;
     RECT  48.604 13.584 49.744 21.672 ;
     RECT  49.705 54.096 49.745 55.896 ;
     RECT  49.673 4.752 49.853 4.968 ;
     RECT  49.573 27.072 49.853 31.8 ;
     RECT  49.745 54.096 49.853 54.456 ;
     RECT  49.637 34.752 49.885 35.4 ;
     RECT  48.604 36.48 49.885 36.552 ;
     RECT  49.853 28.944 49.921 31.8 ;
     RECT  49.637 33.12 49.921 33.576 ;
     RECT  49.744 13.584 49.925 21.72 ;
     RECT  49.885 34.752 49.925 36.552 ;
     RECT  49.925 16.224 49.997 21.72 ;
     RECT  48.604 43.056 50.137 43.56 ;
     RECT  49.745 55.872 50.137 55.896 ;
     RECT  48.604 47.136 50.252 47.16 ;
     RECT  49.205 45.024 50.353 45.528 ;
     RECT  50.252 46.944 50.389 47.16 ;
     RECT  49.277 48.48 50.389 49.848 ;
     RECT  49.493 8.208 50.461 8.712 ;
     RECT  49.493 9.744 50.461 11.976 ;
     RECT  49.997 19.632 50.497 21.72 ;
     RECT  49.705 38.352 50.497 40.44 ;
     RECT  50.461 8.208 50.569 11.976 ;
     RECT  49.925 13.584 50.569 15 ;
     RECT  50.137 55.872 50.605 56.952 ;
     RECT  50.389 46.944 50.713 49.848 ;
     RECT  50.353 44.976 50.749 45.528 ;
     RECT  50.497 19.632 50.785 22.056 ;
     RECT  49.565 23.04 50.785 23.928 ;
     RECT  49.853 4.944 50.857 4.968 ;
     RECT  49.637 6.384 50.857 6.408 ;
     RECT  49.853 54.336 50.893 54.456 ;
     RECT  50.605 55.872 50.893 57.096 ;
     RECT  50.749 44.976 50.965 45.72 ;
     RECT  50.857 4.944 51.008 6.408 ;
     RECT  50.569 8.208 51.008 15 ;
     RECT  49.997 16.224 51.008 18.408 ;
     RECT  50.785 19.632 51.008 23.928 ;
     RECT  50.137 25.008 51.008 25.032 ;
     RECT  50.857 26.064 51.008 26.088 ;
     RECT  49.853 27.072 51.008 27.912 ;
     RECT  49.921 28.944 51.008 33.576 ;
     RECT  49.925 34.752 51.008 34.776 ;
     RECT  49.925 36.096 51.008 36.552 ;
     RECT  50.497 38.16 51.008 40.44 ;
     RECT  50.137 42.192 51.008 43.56 ;
     RECT  50.965 44.88 51.008 45.72 ;
     RECT  50.713 46.704 51.008 49.848 ;
     RECT  49.637 50.832 51.008 51.24 ;
     RECT  49.669 52.224 51.008 52.44 ;
     RECT  50.893 54.096 51.008 54.456 ;
     RECT  50.893 55.872 51.008 57.336 ;
     RECT  51.008 2.148 51.112 75.612 ;
     RECT  51.112 2.148 51.304 75.342 ;
     RECT  51.304 42.192 51.329 46.104 ;
     RECT  51.304 50.832 51.329 57.432 ;
     RECT  51.304 4.944 51.365 5.496 ;
     RECT  51.304 8.544 51.401 9.384 ;
     RECT  51.304 47.136 51.401 49.8 ;
     RECT  51.401 9.072 51.473 9.384 ;
     RECT  51.329 50.832 51.509 57.336 ;
     RECT  51.304 37.584 51.545 41.16 ;
     RECT  51.329 42.192 51.545 42.216 ;
     RECT  51.329 43.536 51.545 46.104 ;
     RECT  51.289 0.096 51.577 0.12 ;
     RECT  51.304 22.032 51.581 22.056 ;
     RECT  51.401 47.136 51.581 48.696 ;
     RECT  51.581 47.904 51.683 48.696 ;
     RECT  51.577 0.096 51.685 0.168 ;
     RECT  51.683 48.432 51.689 48.696 ;
     RECT  51.545 44.832 51.725 46.104 ;
     RECT  51.545 40.848 51.761 41.16 ;
     RECT  51.304 30.048 51.833 31.224 ;
     RECT  51.304 34.752 51.833 36.552 ;
     RECT  51.685 0.096 51.901 1.128 ;
     RECT  51.761 41.136 52.049 41.16 ;
     RECT  51.304 10.368 52.085 15.192 ;
     RECT  51.304 32.304 52.157 33.096 ;
     RECT  51.833 30.192 52.333 31.224 ;
     RECT  51.365 4.944 52.369 4.968 ;
     RECT  51.304 23.04 52.373 23.352 ;
     RECT  51.304 7.392 52.405 7.416 ;
     RECT  51.833 35.424 52.445 36.552 ;
     RECT  52.405 6.816 52.481 7.416 ;
     RECT  52.481 6.816 52.489 6.84 ;
     RECT  51.473 9.312 52.553 9.384 ;
     RECT  51.509 57.072 52.553 57.336 ;
     RECT  51.304 19.632 52.585 20.616 ;
     RECT  51.901 0.096 52.643 1.752 ;
     RECT  51.304 16.8 52.661 18.168 ;
     RECT  51.725 46.08 52.661 46.104 ;
     RECT  51.725 44.832 52.693 44.856 ;
     RECT  51.304 28.944 52.729 28.968 ;
     RECT  52.585 19.632 52.765 20.904 ;
     RECT  52.765 19.536 52.796 20.904 ;
     RECT  52.796 19.536 52.837 21 ;
     RECT  51.545 43.536 52.844 43.56 ;
     RECT  51.689 48.624 52.873 48.696 ;
     RECT  51.401 49.68 52.873 49.8 ;
     RECT  52.085 13.824 52.909 15.192 ;
     RECT  52.837 19.536 52.909 21.672 ;
     RECT  51.304 27.072 52.909 27.096 ;
     RECT  52.643 1.728 52.981 1.752 ;
     RECT  52.369 3.984 52.981 4.968 ;
     RECT  52.909 13.824 53.017 15.288 ;
     RECT  52.643 0.096 53.123 0.6 ;
     RECT  52.157 33.024 53.197 33.096 ;
     RECT  52.885 46.608 53.233 46.824 ;
     RECT  51.509 50.832 53.233 55.992 ;
     RECT  52.553 57.072 53.233 57.096 ;
     RECT  52.981 3.984 53.269 5.208 ;
     RECT  52.873 48.624 53.377 49.8 ;
     RECT  53.233 50.832 53.377 57.096 ;
     RECT  53.123 0.144 53.411 0.6 ;
     RECT  52.373 23.04 53.449 23.064 ;
     RECT  52.693 44.592 53.449 44.856 ;
     RECT  52.445 36.288 53.485 36.552 ;
     RECT  52.981 1.728 53.549 2.712 ;
     RECT  53.269 3.888 53.549 5.208 ;
     RECT  53.017 13.824 53.549 15.672 ;
     RECT  52.981 8.016 53.557 8.04 ;
     RECT  52.553 9.312 53.557 9.336 ;
     RECT  53.557 8.016 53.593 9.336 ;
     RECT  52.297 24.48 53.593 24.504 ;
     RECT  52.909 25.488 53.593 27.096 ;
     RECT  52.333 30.192 53.629 31.464 ;
     RECT  53.197 33.024 53.629 33.864 ;
     RECT  53.549 1.728 53.665 5.208 ;
     RECT  52.085 10.368 53.665 12.504 ;
     RECT  53.549 13.776 53.665 15.672 ;
     RECT  53.485 34.992 53.665 36.552 ;
     RECT  51.545 37.584 53.665 39.864 ;
     RECT  53.665 1.68 53.708 5.208 ;
     RECT  53.593 8.016 53.708 9.384 ;
     RECT  53.665 10.368 53.708 15.672 ;
     RECT  52.661 16.8 53.708 18.024 ;
     RECT  52.909 19.488 53.708 21.672 ;
     RECT  53.449 23.04 53.708 23.4 ;
     RECT  53.593 24.48 53.708 27.096 ;
     RECT  52.729 28.512 53.708 28.968 ;
     RECT  53.629 30.192 53.708 33.864 ;
     RECT  53.665 34.992 53.708 39.864 ;
     RECT  53.269 42.288 53.708 42.312 ;
     RECT  52.844 43.296 53.708 43.56 ;
     RECT  53.449 44.592 53.708 45.528 ;
     RECT  53.233 46.608 53.708 47.352 ;
     RECT  53.377 48.624 53.708 57.096 ;
     RECT  53.708 1.68 53.812 75.612 ;
     RECT  53.812 1.68 54.004 75.342 ;
     RECT  54.004 1.68 54.025 5.736 ;
     RECT  54.004 52.416 54.029 53.064 ;
     RECT  54.004 16.368 54.101 20.568 ;
     RECT  54.025 1.152 54.109 5.736 ;
     RECT  53.411 0.144 54.131 0.168 ;
     RECT  54.004 30.576 54.131 39.864 ;
     RECT  54.004 49.296 54.137 49.32 ;
     RECT  54.004 6.864 54.145 7.464 ;
     RECT  54.101 16.368 54.145 19.08 ;
     RECT  54.004 8.64 54.173 9.336 ;
     RECT  54.004 10.368 54.173 15.288 ;
     RECT  54.173 11.952 54.179 15.288 ;
     RECT  54.029 52.416 54.179 53.016 ;
     RECT  54.179 52.848 54.217 53.016 ;
     RECT  54.109 1.728 54.461 5.736 ;
     RECT  54.004 46.608 54.461 47.16 ;
     RECT  54.461 5.088 54.604 5.736 ;
     RECT  54.004 54.336 54.605 54.36 ;
     RECT  54.101 20.304 54.641 20.568 ;
     RECT  54.461 46.8 54.641 47.16 ;
     RECT  54.131 30.576 54.649 34.392 ;
     RECT  54.004 44.928 54.749 45.576 ;
     RECT  54.131 35.808 54.785 39.864 ;
     RECT  54.004 25.008 54.796 29.112 ;
     RECT  54.641 46.944 54.857 47.16 ;
     RECT  54.179 11.952 54.94 13.896 ;
     RECT  54.145 6.864 54.965 6.984 ;
     RECT  54.749 44.928 55.073 44.952 ;
     RECT  54.173 10.368 55.109 10.872 ;
     RECT  54.179 14.976 55.177 15.288 ;
     RECT  54.145 16.368 55.177 18.024 ;
     RECT  54.785 37.632 55.177 39.864 ;
     RECT  54.796 25.008 55.213 28.536 ;
     RECT  55.177 14.976 55.253 18.024 ;
     RECT  54.004 42.288 55.285 42.792 ;
     RECT  54.94 12.48 55.325 13.896 ;
     RECT  54.217 52.992 55.325 53.016 ;
     RECT  55.177 37.632 55.331 40.248 ;
     RECT  54.173 9.312 55.357 9.336 ;
     RECT  55.253 17.616 55.361 18.024 ;
     RECT  54.641 20.544 55.393 20.568 ;
     RECT  54.649 33.84 55.393 34.392 ;
     RECT  54.785 35.808 55.397 36.552 ;
     RECT  55.331 37.632 55.397 39.864 ;
     RECT  54.004 22.128 55.433 23.4 ;
     RECT  55.397 36.432 55.433 36.552 ;
     RECT  54.461 1.728 55.537 4.008 ;
     RECT  54.004 55.968 55.537 55.992 ;
     RECT  55.237 7.44 55.717 7.464 ;
     RECT  55.357 8.544 55.717 9.336 ;
     RECT  55.285 41.904 55.717 42.792 ;
     RECT  55.093 0.096 55.765 0.12 ;
     RECT  54.604 5.136 55.813 5.736 ;
     RECT  55.717 7.44 55.825 9.336 ;
     RECT  55.537 1.728 55.861 4.056 ;
     RECT  55.645 54.672 55.933 54.696 ;
     RECT  55.537 55.968 55.933 56.232 ;
     RECT  55.861 1.248 55.957 4.056 ;
     RECT  55.213 24.624 55.969 28.536 ;
     RECT  55.813 5.136 56.041 6.312 ;
     RECT  55.825 7.44 56.041 9.384 ;
     RECT  55.957 1.152 56.053 4.056 ;
     RECT  56.041 5.136 56.053 9.384 ;
     RECT  55.393 20.544 56.077 21.096 ;
     RECT  55.765 0.096 56.149 0.168 ;
     RECT  56.053 1.152 56.149 9.384 ;
     RECT  56.149 0.096 56.153 9.384 ;
     RECT  55.325 12.48 56.185 13.848 ;
     RECT  54.857 47.136 56.221 47.16 ;
     RECT  55.361 17.616 56.293 17.64 ;
     RECT  54.145 19.056 56.293 19.08 ;
     RECT  56.077 20.544 56.293 21.528 ;
     RECT  55.717 41.904 56.293 43.368 ;
     RECT  56.153 2.148 56.408 9.384 ;
     RECT  55.109 10.848 56.408 10.872 ;
     RECT  56.185 11.952 56.408 13.848 ;
     RECT  55.253 14.976 56.408 16.536 ;
     RECT  56.293 17.568 56.408 17.64 ;
     RECT  56.293 19.056 56.408 21.528 ;
     RECT  55.433 23.04 56.408 23.4 ;
     RECT  55.969 24.624 56.408 29.352 ;
     RECT  54.649 30.576 56.408 32.856 ;
     RECT  55.393 33.84 56.408 34.728 ;
     RECT  55.433 36.528 56.408 36.552 ;
     RECT  55.397 38.256 56.408 39.864 ;
     RECT  56.293 41.424 56.408 43.368 ;
     RECT  56.221 47.136 56.408 47.784 ;
     RECT  55.609 50.928 56.408 50.952 ;
     RECT  55.933 54.672 56.408 56.232 ;
     RECT  56.408 2.148 56.512 75.612 ;
     RECT  56.512 2.256 56.704 75.342 ;
     RECT  56.704 44.448 56.801 44.472 ;
     RECT  56.704 50.544 56.801 51.48 ;
     RECT  56.704 20.976 56.819 22.056 ;
     RECT  56.704 46.56 56.819 47.16 ;
     RECT  56.704 23.04 56.837 25.224 ;
     RECT  56.819 46.56 56.837 46.872 ;
     RECT  56.801 50.544 56.837 50.952 ;
     RECT  56.704 54.144 56.845 55.512 ;
     RECT  56.704 32.832 56.909 35.352 ;
     RECT  56.704 36.528 56.909 36.552 ;
     RECT  56.837 50.544 56.909 50.568 ;
     RECT  56.704 26.256 57.011 29.352 ;
     RECT  56.704 19.776 57.017 19.8 ;
     RECT  56.704 2.256 57.059 9.384 ;
     RECT  56.704 11.424 57.089 13.608 ;
     RECT  56.837 46.704 57.125 46.872 ;
     RECT  56.704 30.672 57.197 31.128 ;
     RECT  56.704 37.68 57.197 39.912 ;
     RECT  57.011 26.256 57.521 26.856 ;
     RECT  56.704 42.768 57.521 42.792 ;
     RECT  57.089 11.424 57.539 13.416 ;
     RECT  57.011 28.08 57.629 29.352 ;
     RECT  56.704 41.184 57.629 41.208 ;
     RECT  56.704 15.36 57.773 16.152 ;
     RECT  57.197 31.104 57.805 31.128 ;
     RECT  57.197 37.68 57.809 39.816 ;
     RECT  57.059 2.832 57.817 9.384 ;
     RECT  57.817 5.088 57.836 9.384 ;
     RECT  56.819 21.216 57.841 22.056 ;
     RECT  56.837 23.04 57.841 25.176 ;
     RECT  57.809 38.16 57.881 39.816 ;
     RECT  57.769 53.232 57.881 53.256 ;
     RECT  56.704 17.616 57.913 18.792 ;
     RECT  57.841 21.216 57.917 25.176 ;
     RECT  57.836 5.088 57.923 10.296 ;
     RECT  56.909 34.08 57.953 35.352 ;
     RECT  57.817 2.832 58.021 4.104 ;
     RECT  58.021 2.256 58.025 4.104 ;
     RECT  57.521 26.496 58.057 26.856 ;
     RECT  57.877 50.304 58.057 50.328 ;
     RECT  57.917 25.152 58.061 25.176 ;
     RECT  58.025 2.256 58.108 4.008 ;
     RECT  57.773 15.84 58.117 16.152 ;
     RECT  56.845 54.672 58.124 55.512 ;
     RECT  58.057 50.304 58.129 50.568 ;
     RECT  57.917 21.216 58.165 24.12 ;
     RECT  57.985 49.2 58.165 49.224 ;
     RECT  58.124 54.48 58.309 55.512 ;
     RECT  56.909 32.832 58.345 33.048 ;
     RECT  56.153 0.096 58.357 0.84 ;
     RECT  57.805 31.104 58.417 31.416 ;
     RECT  58.345 32.496 58.417 33.048 ;
     RECT  58.417 31.104 58.453 33.048 ;
     RECT  57.953 34.08 58.453 34.776 ;
     RECT  57.539 11.424 58.525 13.128 ;
     RECT  58.165 49.056 58.561 49.224 ;
     RECT  58.561 48.96 58.605 49.224 ;
     RECT  58.489 25.248 58.633 25.272 ;
     RECT  58.057 26.496 58.633 27.144 ;
     RECT  58.129 36.48 58.633 36.504 ;
     RECT  58.605 48.912 58.633 49.224 ;
     RECT  58.129 50.304 58.633 51 ;
     RECT  58.633 25.248 58.693 27.144 ;
     RECT  57.629 28.224 58.693 29.352 ;
     RECT  58.633 48.912 58.741 51 ;
     RECT  58.604 19.968 58.981 19.992 ;
     RECT  58.165 21.12 58.981 24.12 ;
     RECT  57.881 38.448 59.065 39.816 ;
     RECT  58.108 2.688 59.108 4.008 ;
     RECT  57.923 5.088 59.108 8.904 ;
     RECT  58.525 11.424 59.108 13.608 ;
     RECT  57.949 14.832 59.108 14.856 ;
     RECT  58.117 15.84 59.108 16.248 ;
     RECT  57.913 17.472 59.108 18.792 ;
     RECT  58.981 19.968 59.108 24.12 ;
     RECT  58.693 25.248 59.108 29.352 ;
     RECT  58.453 31.104 59.108 34.776 ;
     RECT  58.633 36.288 59.108 36.504 ;
     RECT  59.065 37.584 59.108 39.816 ;
     RECT  57.125 46.848 59.108 46.872 ;
     RECT  58.741 48.672 59.108 51 ;
     RECT  58.309 53.52 59.108 55.512 ;
     RECT  59.108 2.148 59.212 75.612 ;
     RECT  59.212 2.418 59.404 75.342 ;
     RECT  59.404 9.072 59.555 9.096 ;
     RECT  59.404 6.672 59.645 6.84 ;
     RECT  59.404 51.84 59.681 54.36 ;
     RECT  59.681 51.84 59.717 53.832 ;
     RECT  59.404 5.184 59.753 5.496 ;
     RECT  59.753 5.472 59.825 5.496 ;
     RECT  59.404 13.584 59.825 16.296 ;
     RECT  59.404 11.952 59.897 11.976 ;
     RECT  59.404 55.488 60.041 55.512 ;
     RECT  59.717 52.56 60.185 53.832 ;
     RECT  59.404 46.848 60.257 48.168 ;
     RECT  58.357 0.048 60.293 0.84 ;
     RECT  60.257 48.144 60.293 48.168 ;
     RECT  59.404 18.192 60.365 25.464 ;
     RECT  60.365 18.192 60.397 20.568 ;
     RECT  59.404 37.584 60.397 39.816 ;
     RECT  60.257 46.848 60.397 47.016 ;
     RECT  60.397 46.752 60.401 47.016 ;
     RECT  60.397 17.904 60.419 20.568 ;
     RECT  59.404 31.104 60.428 34.776 ;
     RECT  60.397 37.584 60.433 39.912 ;
     RECT  60.433 37.584 60.437 40.056 ;
     RECT  59.404 43.872 60.437 44.712 ;
     RECT  59.825 14.112 60.467 16.296 ;
     RECT  60.428 31.104 60.469 35.352 ;
     RECT  59.404 36.528 60.469 36.552 ;
     RECT  60.365 21.696 60.505 25.464 ;
     RECT  59.404 26.544 60.505 29.496 ;
     RECT  60.419 17.904 60.509 19.944 ;
     RECT  60.469 30.72 60.515 36.552 ;
     RECT  60.437 39.888 60.524 40.056 ;
     RECT  59.404 41.28 60.524 42.216 ;
     RECT  60.515 35.856 60.572 36.552 ;
     RECT  60.437 37.584 60.572 38.472 ;
     RECT  60.467 15.984 60.577 16.296 ;
     RECT  60.524 39.888 60.581 42.216 ;
     RECT  60.505 21.696 60.611 29.688 ;
     RECT  60.581 40.032 60.611 42.216 ;
     RECT  60.611 41.52 60.649 42.216 ;
     RECT  60.611 21.696 60.653 29.496 ;
     RECT  60.572 35.856 60.659 38.472 ;
     RECT  60.653 21.936 60.689 29.496 ;
     RECT  60.649 41.52 60.689 42.744 ;
     RECT  60.577 15.984 60.707 16.68 ;
     RECT  60.689 21.936 60.707 22.968 ;
     RECT  59.404 49.2 60.725 49.224 ;
     RECT  59.645 6.816 60.761 6.84 ;
     RECT  60.293 0.528 60.869 0.84 ;
     RECT  60.869 0.528 60.977 0.552 ;
     RECT  60.437 44.304 60.997 44.712 ;
     RECT  60.997 44.304 61.513 45.048 ;
     RECT  61.441 8.448 61.549 8.472 ;
     RECT  60.467 14.112 61.549 14.808 ;
     RECT  60.509 17.904 61.549 19.848 ;
     RECT  61.549 7.632 61.573 8.472 ;
     RECT  60.515 30.72 61.573 34.824 ;
     RECT  60.707 16.272 61.669 16.68 ;
     RECT  61.549 17.664 61.669 19.848 ;
     RECT  60.707 21.936 61.669 22.536 ;
     RECT  60.689 24.24 61.669 29.496 ;
     RECT  60.659 38.208 61.669 38.472 ;
     RECT  60.611 40.032 61.669 40.152 ;
     RECT  61.573 7.632 61.808 8.52 ;
     RECT  61.549 14.112 61.808 14.952 ;
     RECT  61.669 16.272 61.808 19.848 ;
     RECT  61.669 21.936 61.808 29.496 ;
     RECT  61.573 30.576 61.808 34.824 ;
     RECT  60.659 35.856 61.808 36.552 ;
     RECT  61.669 38.208 61.808 40.152 ;
     RECT  60.689 41.52 61.808 41.592 ;
     RECT  60.689 42.72 61.808 42.744 ;
     RECT  61.513 44.304 61.808 45.576 ;
     RECT  60.401 46.752 61.808 46.872 ;
     RECT  60.185 52.56 61.808 52.872 ;
     RECT  60.901 54.72 61.808 54.744 ;
     RECT  60.997 55.872 61.808 55.896 ;
     RECT  61.808 2.148 61.912 75.612 ;
     RECT  61.912 2.418 62.104 75.342 ;
     RECT  62.104 26.544 62.165 28.968 ;
     RECT  62.104 38.208 62.165 40.152 ;
     RECT  62.104 43.296 62.237 43.32 ;
     RECT  62.104 42.288 62.243 42.312 ;
     RECT  62.104 6.528 62.309 8.472 ;
     RECT  62.165 38.208 62.309 40.104 ;
     RECT  62.165 26.544 62.345 28.824 ;
     RECT  62.104 51.888 62.381 53.784 ;
     RECT  62.104 18.672 62.417 21.384 ;
     RECT  62.104 23.376 62.417 24.456 ;
     RECT  62.381 51.888 62.435 52.728 ;
     RECT  62.104 45.552 62.531 47.928 ;
     RECT  62.309 7.92 62.597 8.472 ;
     RECT  62.104 14.112 62.627 14.664 ;
     RECT  62.435 51.888 62.669 52.008 ;
     RECT  62.417 18.672 62.705 19.896 ;
     RECT  62.345 26.544 62.705 26.712 ;
     RECT  62.104 35.904 62.777 36.072 ;
     RECT  62.104 37.056 62.777 37.08 ;
     RECT  62.309 6.528 62.813 6.696 ;
     RECT  62.417 23.376 62.813 23.688 ;
     RECT  62.669 51.984 62.849 52.008 ;
     RECT  62.104 49.776 62.921 49.8 ;
     RECT  62.777 35.904 62.957 36.024 ;
     RECT  62.345 28.08 63.133 28.824 ;
     RECT  62.104 15.648 63.205 17.688 ;
     RECT  62.705 18.672 63.205 18.696 ;
     RECT  63.133 28.08 63.205 29.016 ;
     RECT  62.104 30.192 63.205 34.776 ;
     RECT  63.205 28.08 63.277 34.776 ;
     RECT  62.957 35.904 63.277 35.928 ;
     RECT  62.381 53.76 63.353 53.784 ;
     RECT  63.205 15.648 63.421 18.696 ;
     RECT  62.813 23.664 63.421 23.688 ;
     RECT  62.813 6.528 63.445 6.552 ;
     RECT  63.445 5.568 63.491 6.552 ;
     RECT  62.705 19.68 63.493 19.896 ;
     RECT  62.417 21.072 63.493 21.384 ;
     RECT  62.597 7.92 63.601 7.944 ;
     RECT  63.421 15.12 63.673 18.696 ;
     RECT  63.493 19.68 63.673 21.384 ;
     RECT  63.673 15.12 63.853 21.384 ;
     RECT  62.705 26.544 63.853 26.664 ;
     RECT  63.601 42.72 63.889 42.744 ;
     RECT  63.601 7.92 63.925 8.52 ;
     RECT  63.925 7.92 63.961 10.344 ;
     RECT  62.309 38.208 63.961 38.472 ;
     RECT  63.889 42.528 63.961 42.744 ;
     RECT  63.421 23.664 63.997 24.12 ;
     RECT  63.421 25.248 63.997 25.272 ;
     RECT  63.997 25.152 64.033 25.272 ;
     RECT  63.853 26.544 64.033 26.808 ;
     RECT  63.961 38.16 64.141 38.472 ;
     RECT  63.997 23.328 64.177 24.12 ;
     RECT  64.033 25.152 64.177 26.808 ;
     RECT  63.961 42.192 64.285 42.744 ;
     RECT  64.177 22.8 64.321 26.808 ;
     RECT  63.277 28.08 64.321 35.928 ;
     RECT  64.321 22.8 64.357 35.928 ;
     RECT  62.309 40.032 64.429 40.104 ;
     RECT  64.141 38.112 64.465 38.472 ;
     RECT  63.491 5.568 64.508 5.592 ;
     RECT  63.961 7.92 64.508 10.728 ;
     RECT  62.104 11.808 64.508 11.832 ;
     RECT  63.853 15.12 64.508 21.528 ;
     RECT  64.357 22.752 64.508 36.264 ;
     RECT  64.465 37.968 64.508 38.472 ;
     RECT  64.429 40.032 64.508 40.584 ;
     RECT  64.285 42.192 64.508 43.032 ;
     RECT  62.531 46.272 64.508 47.928 ;
     RECT  64.508 2.148 64.612 75.612 ;
     RECT  64.612 2.418 64.804 75.342 ;
     RECT  64.804 8.976 64.931 9.624 ;
     RECT  64.804 16.08 64.973 16.344 ;
     RECT  64.804 26.016 64.973 29.448 ;
     RECT  64.804 20.592 65.009 24.504 ;
     RECT  64.804 30.576 65.053 44.424 ;
     RECT  65.053 30.576 65.117 43.608 ;
     RECT  64.804 54.096 65.123 54.744 ;
     RECT  65.123 54.72 65.153 54.744 ;
     RECT  64.804 45.6 65.189 47.928 ;
     RECT  65.009 20.592 65.225 23.352 ;
     RECT  65.117 37.104 65.549 43.608 ;
     RECT  64.931 8.976 65.585 9 ;
     RECT  65.549 37.296 65.585 43.608 ;
     RECT  64.973 16.08 65.657 16.296 ;
     RECT  65.225 21.072 65.657 23.352 ;
     RECT  65.189 46.08 65.657 47.928 ;
     RECT  65.585 37.632 65.729 43.608 ;
     RECT  64.804 17.904 65.797 19.032 ;
     RECT  65.009 24.48 65.837 24.504 ;
     RECT  64.804 10.704 65.843 10.728 ;
     RECT  65.657 16.272 65.843 16.296 ;
     RECT  64.973 26.064 65.843 29.448 ;
     RECT  65.797 17.904 65.945 19.416 ;
     RECT  65.843 27.36 65.945 29.064 ;
     RECT  65.945 17.904 66.013 18.84 ;
     RECT  65.657 46.08 66.053 47.88 ;
     RECT  65.657 21.072 66.197 21.816 ;
     RECT  66.013 53.616 66.373 53.64 ;
     RECT  66.373 53.616 66.445 53.688 ;
     RECT  66.053 46.08 66.481 47.736 ;
     RECT  65.117 30.576 66.517 35.352 ;
     RECT  66.517 30.048 66.697 35.352 ;
     RECT  65.657 23.328 66.769 23.352 ;
     RECT  65.945 28.128 66.841 29.064 ;
     RECT  66.697 30.048 66.841 35.736 ;
     RECT  66.013 6.864 66.913 6.888 ;
     RECT  65.843 26.064 66.913 26.088 ;
     RECT  66.445 53.616 66.949 53.832 ;
     RECT  66.197 21.504 66.985 21.816 ;
     RECT  65.729 37.632 67.057 43.368 ;
     RECT  66.913 25.248 67.129 26.088 ;
     RECT  67.057 37.392 67.129 43.368 ;
     RECT  64.804 5.568 67.208 5.592 ;
     RECT  66.913 6.864 67.208 7.128 ;
     RECT  65.797 12.288 67.208 12.312 ;
     RECT  66.013 16.896 67.208 18.84 ;
     RECT  66.589 19.872 67.208 19.896 ;
     RECT  66.985 21.504 67.208 22.056 ;
     RECT  66.769 23.088 67.208 23.352 ;
     RECT  67.129 24.432 67.208 26.088 ;
     RECT  66.841 28.128 67.208 35.736 ;
     RECT  67.129 37.152 67.208 43.368 ;
     RECT  66.373 44.4 67.208 44.424 ;
     RECT  66.481 46.032 67.208 47.736 ;
     RECT  64.804 50.832 67.208 50.952 ;
     RECT  66.949 53.52 67.208 53.832 ;
     RECT  67.208 2.148 67.312 75.612 ;
     RECT  67.312 2.418 67.504 75.342 ;
     RECT  67.504 28.944 67.637 34.776 ;
     RECT  67.637 29.04 67.673 34.776 ;
     RECT  67.504 35.856 67.745 44.424 ;
     RECT  67.745 35.856 67.781 41.448 ;
     RECT  67.781 39.792 67.817 41.448 ;
     RECT  67.817 40.08 67.853 41.448 ;
     RECT  67.504 21.696 67.907 26.088 ;
     RECT  67.745 42.432 67.925 44.424 ;
     RECT  67.504 16.896 67.961 17.352 ;
     RECT  67.504 50.736 67.961 50.952 ;
     RECT  67.504 47.424 67.997 47.448 ;
     RECT  67.907 21.696 68.003 25.08 ;
     RECT  67.853 40.08 68.105 40.92 ;
     RECT  67.925 42.432 68.249 42.744 ;
     RECT  68.003 21.696 68.321 22.872 ;
     RECT  67.673 29.616 68.429 34.776 ;
     RECT  67.781 35.856 68.429 38.472 ;
     RECT  67.961 17.328 68.569 17.352 ;
     RECT  67.925 44.4 68.573 44.424 ;
     RECT  68.003 23.904 68.753 25.08 ;
     RECT  68.429 30.576 68.785 34.776 ;
     RECT  68.753 24.48 68.905 25.08 ;
     RECT  68.497 27.744 68.929 27.768 ;
     RECT  68.321 21.744 68.933 22.872 ;
     RECT  67.504 46.032 68.965 46.056 ;
     RECT  67.504 12.288 68.972 12.312 ;
     RECT  68.972 12.288 69.001 12.552 ;
     RECT  67.504 9.456 69.013 9.48 ;
     RECT  69.013 9.456 69.037 10.344 ;
     RECT  68.929 27.744 69.109 28.488 ;
     RECT  68.105 40.32 69.253 40.92 ;
     RECT  68.905 25.008 69.289 25.08 ;
     RECT  67.907 26.064 69.289 26.088 ;
     RECT  69.109 27.312 69.325 28.488 ;
     RECT  68.569 17.328 69.505 18.024 ;
     RECT  68.785 30.576 69.505 35.352 ;
     RECT  68.429 36.336 69.505 38.472 ;
     RECT  69.325 27.312 69.577 29.064 ;
     RECT  69.505 30.576 69.577 38.472 ;
     RECT  69.325 47.76 69.589 47.784 ;
     RECT  69.505 17.328 69.733 18.216 ;
     RECT  68.965 46.032 69.757 46.248 ;
     RECT  69.589 47.232 69.757 48.792 ;
     RECT  69.733 17.328 69.781 18.792 ;
     RECT  68.885 19.92 69.781 20.424 ;
     RECT  69.577 27.312 69.901 38.472 ;
     RECT  67.504 7.104 69.908 7.128 ;
     RECT  69.037 9.456 69.908 10.824 ;
     RECT  69.001 12.192 69.908 12.552 ;
     RECT  69.781 17.328 69.908 20.424 ;
     RECT  68.933 21.744 69.908 21.768 ;
     RECT  69.289 25.008 69.908 26.088 ;
     RECT  69.901 27.312 69.908 39.24 ;
     RECT  69.253 40.32 69.908 41.448 ;
     RECT  68.249 42.432 69.908 42.6 ;
     RECT  69.757 46.032 69.908 48.792 ;
     RECT  67.961 50.736 69.908 50.76 ;
     RECT  69.908 2.148 70.012 75.612 ;
     RECT  70.012 2.418 70.204 75.342 ;
     RECT  70.204 48.768 70.265 48.792 ;
     RECT  70.204 27.888 70.337 27.912 ;
     RECT  70.204 35.76 70.373 39.336 ;
     RECT  70.204 20.064 70.451 22.248 ;
     RECT  70.204 29.616 70.481 29.64 ;
     RECT  70.204 25.536 70.553 25.56 ;
     RECT  70.204 18.432 70.661 18.552 ;
     RECT  70.451 21.552 70.691 22.248 ;
     RECT  70.691 21.552 70.805 21.576 ;
     RECT  70.204 40.56 70.835 47.352 ;
     RECT  70.835 40.608 70.841 47.352 ;
     RECT  70.841 40.608 70.877 46.68 ;
     RECT  70.451 20.064 70.913 20.088 ;
     RECT  70.204 31.92 70.949 34.728 ;
     RECT  70.373 35.808 70.949 39.336 ;
     RECT  70.877 45.12 71.021 46.68 ;
     RECT  70.877 40.608 71.057 44.04 ;
     RECT  71.057 40.608 71.093 43.8 ;
     RECT  71.093 42.576 71.165 43.8 ;
     RECT  71.165 42.576 71.273 43.32 ;
     RECT  71.273 42.576 71.489 42.6 ;
     RECT  70.949 31.968 71.737 34.728 ;
     RECT  70.949 35.808 71.737 35.832 ;
     RECT  71.737 31.968 72.608 35.832 ;
     RECT  70.949 37.2 72.608 39.336 ;
     RECT  71.093 40.608 72.608 41.016 ;
     RECT  71.021 45.456 72.608 46.68 ;
     RECT  72.608 2.148 72.712 75.612 ;
     RECT  72.712 2.418 72.904 75.342 ;
     RECT  72.904 43.008 73.397 43.032 ;
     RECT  72.904 33.888 73.571 34.824 ;
     RECT  72.904 44.592 73.897 44.76 ;
     RECT  73.897 43.92 73.969 44.76 ;
     RECT  72.904 45.744 73.969 45.768 ;
     RECT  73.571 34.704 74.045 34.824 ;
     RECT  72.904 36.432 74.189 38.472 ;
     RECT  73.969 43.92 74.333 45.768 ;
     RECT  74.189 37.68 74.473 38.472 ;
     RECT  74.333 43.92 74.473 44.664 ;
     RECT  74.149 35.136 75.308 35.16 ;
     RECT  74.581 36.144 75.308 36.168 ;
     RECT  74.473 37.68 75.308 39.24 ;
     RECT  74.689 41.664 75.308 41.688 ;
     RECT  74.473 42.912 75.308 44.664 ;
     RECT  74.333 45.744 75.308 45.768 ;
     RECT  75.308 2.148 75.412 75.612 ;
     RECT  75.412 2.418 75.604 75.342 ;
     RECT  75.604 44.112 76.133 44.136 ;
     RECT  75.604 41.952 76.349 42.744 ;
     RECT  76.349 42.192 76.565 42.744 ;
     RECT  76.565 42.72 76.597 42.744 ;
     RECT  76.597 42.72 76.673 43.176 ;
     RECT  76.673 43.152 76.745 43.176 ;
     RECT  75.604 38.448 78.008 38.472 ;
     RECT  78.008 2.148 78.112 75.612 ;
     RECT  78.112 2.418 78.304 75.342 ;
     RECT  78.304 38.448 80.708 38.472 ;
     RECT  80.708 2.148 80.812 75.612 ;
     RECT  80.812 2.418 81.004 75.342 ;
     RECT  81.004 38.448 83.408 38.472 ;
     RECT  83.408 2.148 83.512 75.612 ;
     RECT  83.512 2.418 83.704 75.342 ;
     RECT  83.704 38.448 85.453 38.472 ;
     RECT  85.453 38.448 86.281 39.384 ;
     RECT  86.281 38.352 86.321 39.384 ;
    LAYER M5 ;
     RECT  52.032 0.016 58.296 0.037 ;
     RECT  52.032 0.037 58.392 0.181 ;
     RECT  28.032 0.016 34.296 0.611 ;
     RECT  28.128 0.611 34.296 1.187 ;
     RECT  28.224 1.187 34.296 1.715 ;
     RECT  28.32 1.715 34.296 1.763 ;
     RECT  52.032 0.181 59.016 1.763 ;
     RECT  28.416 1.763 34.296 2.137 ;
     RECT  52.704 1.763 59.016 2.137 ;
     RECT  2.4 2.137 2.52 2.151 ;
     RECT  5.1 2.137 5.22 2.151 ;
     RECT  7.8 2.137 7.92 2.151 ;
     RECT  10.5 2.137 10.62 2.151 ;
     RECT  13.2 2.137 13.32 2.151 ;
     RECT  15.9 2.137 16.02 2.151 ;
     RECT  18.6 2.137 18.72 2.151 ;
     RECT  21.3 2.137 21.42 2.151 ;
     RECT  24 2.137 24.12 2.151 ;
     RECT  26.7 2.137 26.82 2.151 ;
     RECT  28.416 2.137 34.92 2.151 ;
     RECT  37.5 2.137 37.62 2.151 ;
     RECT  40.2 2.137 40.32 2.151 ;
     RECT  42.9 2.137 43.176 2.151 ;
     RECT  45.6 2.137 45.72 2.151 ;
     RECT  48.3 2.137 48.42 2.151 ;
     RECT  52.704 2.137 59.22 2.151 ;
     RECT  61.8 2.137 61.92 2.151 ;
     RECT  64.5 2.137 64.62 2.151 ;
     RECT  67.2 2.137 67.32 2.151 ;
     RECT  69.9 2.137 70.02 2.151 ;
     RECT  72.6 2.137 72.72 2.151 ;
     RECT  75.3 2.137 75.42 2.151 ;
     RECT  78 2.137 78.12 2.151 ;
     RECT  80.7 2.137 80.82 2.151 ;
     RECT  83.4 2.137 83.52 2.151 ;
     RECT  28.416 2.151 35.112 2.245 ;
     RECT  28.416 2.245 35.832 2.291 ;
     RECT  45.6 2.151 45.912 2.581 ;
     RECT  48.3 2.151 48.612 2.773 ;
     RECT  28.896 2.291 35.832 2.821 ;
     RECT  40.2 2.151 40.512 2.821 ;
     RECT  26.7 2.151 27.012 3.253 ;
     RECT  45.168 2.581 45.912 3.349 ;
     RECT  46.896 2.485 46.92 3.443 ;
     RECT  28.896 2.821 35.88 3.637 ;
     RECT  39.936 2.821 40.512 3.685 ;
     RECT  42.9 2.151 43.212 3.781 ;
     RECT  39.888 3.685 40.512 3.925 ;
     RECT  52.704 2.151 59.412 4.019 ;
     RECT  48.3 2.773 48.888 4.117 ;
     RECT  48.3 4.117 49.608 4.403 ;
     RECT  28.896 3.637 36.312 4.501 ;
     RECT  42.9 3.781 43.368 4.691 ;
     RECT  26.7 3.253 27.144 4.979 ;
     RECT  49.584 4.403 49.608 5.171 ;
     RECT  44.976 3.349 45.912 5.173 ;
     RECT  37.5 2.151 37.812 5.269 ;
     RECT  28.416 4.501 36.312 5.365 ;
     RECT  28.416 5.365 36.408 5.461 ;
     RECT  37.5 5.269 38.04 5.461 ;
     RECT  44.928 5.173 45.912 5.749 ;
     RECT  26.7 4.979 27.012 6.229 ;
     RECT  28.416 5.461 38.04 6.323 ;
     RECT  41.808 4.501 41.832 6.323 ;
     RECT  28.416 6.323 29.712 6.419 ;
     RECT  63.456 5.557 63.48 6.563 ;
     RECT  48.3 4.403 48.612 6.805 ;
     RECT  52.992 4.019 59.412 6.805 ;
     RECT  24 2.151 24.312 6.853 ;
     RECT  30.816 6.323 38.04 6.853 ;
     RECT  30.816 6.853 38.472 6.901 ;
     RECT  52.416 6.805 59.412 6.995 ;
     RECT  30.816 6.901 38.568 7.187 ;
     RECT  47.904 6.805 48.612 7.189 ;
     RECT  42.9 4.691 43.212 7.381 ;
     RECT  44.448 5.749 45.912 7.381 ;
     RECT  23.904 6.853 24.312 7.475 ;
     RECT  52.416 6.995 54.12 7.475 ;
     RECT  55.248 6.995 59.412 7.475 ;
     RECT  55.392 7.475 59.412 7.523 ;
     RECT  30.816 7.187 37.944 7.763 ;
     RECT  29.136 6.419 29.712 7.765 ;
     RECT  30.816 7.763 37.812 7.765 ;
     RECT  21.3 2.151 21.612 7.957 ;
     RECT  29.136 7.765 37.812 7.957 ;
     RECT  39.744 3.925 40.512 7.957 ;
     RECT  56.4 7.523 59.412 8.003 ;
     RECT  52.416 7.475 54.012 8.051 ;
     RECT  47.904 7.189 49.464 8.243 ;
     RECT  48.3 8.243 49.464 8.341 ;
     RECT  61.8 2.151 62.112 8.485 ;
     RECT  64.5 2.151 64.812 8.485 ;
     RECT  29.088 7.957 37.812 8.579 ;
     RECT  53.568 8.051 54.012 8.579 ;
     RECT  55.392 7.523 55.416 8.579 ;
     RECT  56.4 8.003 57.912 8.579 ;
     RECT  21.3 7.957 22.536 8.723 ;
     RECT  44.448 7.381 46.152 8.869 ;
     RECT  42.9 7.381 43.368 8.965 ;
     RECT  53.7 8.579 54.012 9.061 ;
     RECT  58.992 8.003 59.412 9.061 ;
     RECT  29.136 8.579 37.812 9.107 ;
     RECT  42.192 8.965 43.368 9.107 ;
     RECT  30.816 9.107 37.812 9.155 ;
     RECT  44.448 8.869 46.728 9.155 ;
     RECT  69.9 2.151 70.212 9.445 ;
     RECT  63.936 8.485 64.812 9.589 ;
     RECT  21.3 8.723 22.248 9.683 ;
     RECT  26.16 6.229 27.012 9.779 ;
     RECT  26.7 9.779 27.012 9.925 ;
     RECT  27.984 6.613 28.008 9.925 ;
     RECT  44.688 9.155 46.728 10.019 ;
     RECT  26.7 9.925 28.008 10.307 ;
     RECT  63.936 9.589 64.92 10.355 ;
     RECT  69.024 9.445 70.212 10.355 ;
     RECT  48.3 8.341 49.56 10.357 ;
     RECT  42.9 9.107 43.212 10.453 ;
     RECT  42 10.453 43.212 10.645 ;
     RECT  64.08 10.355 64.92 10.693 ;
     RECT  24 7.475 24.312 10.741 ;
     RECT  41.904 10.645 43.212 10.835 ;
     RECT  44.688 10.019 45.912 10.835 ;
     RECT  39.696 7.957 40.512 10.883 ;
     RECT  40.032 10.883 40.512 10.979 ;
     RECT  47.904 10.357 49.56 10.979 ;
     RECT  23.328 10.741 24.312 11.365 ;
     RECT  52.416 8.051 52.44 11.459 ;
     RECT  30.912 9.155 37.812 11.651 ;
     RECT  53.7 9.061 54.12 11.749 ;
     RECT  61.584 8.485 62.112 11.797 ;
     RECT  64.08 10.693 65.832 11.843 ;
     RECT  29.136 9.107 29.712 11.893 ;
     RECT  42 10.835 43.212 11.939 ;
     RECT  36.384 11.651 37.812 11.941 ;
     RECT  53.568 11.749 54.12 11.941 ;
     RECT  56.4 8.579 56.712 11.941 ;
     RECT  57.888 8.579 57.912 11.941 ;
     RECT  58.992 9.061 59.544 11.941 ;
     RECT  42.768 11.939 43.212 12.229 ;
     RECT  26.7 10.307 27.24 12.323 ;
     RECT  42.768 12.229 43.752 12.323 ;
     RECT  28.752 11.893 29.712 12.517 ;
     RECT  30.912 11.651 35.352 12.517 ;
     RECT  69.072 10.355 70.212 12.517 ;
     RECT  23.328 11.365 24.408 12.611 ;
     RECT  40.08 10.979 40.512 12.755 ;
     RECT  53.568 11.941 54.888 13.187 ;
     RECT  28.752 12.517 35.352 13.235 ;
     RECT  56.4 11.941 59.544 13.427 ;
     RECT  42.9 12.323 43.752 13.477 ;
     RECT  44.976 10.835 45.912 13.477 ;
     RECT  48.3 10.979 49.56 13.619 ;
     RECT  57.888 13.427 59.544 13.619 ;
     RECT  42.9 13.477 45.912 13.667 ;
     RECT  44.688 13.667 45.912 13.909 ;
     RECT  26.7 12.323 27.012 14.101 ;
     RECT  23.328 12.611 24.312 14.147 ;
     RECT  53.568 13.187 54.12 14.197 ;
     RECT  46.992 13.285 47.016 14.243 ;
     RECT  25.584 13.525 25.608 14.339 ;
     RECT  30.912 13.235 35.352 14.629 ;
     RECT  36.384 11.941 37.944 14.629 ;
     RECT  53.04 14.197 54.12 14.629 ;
     RECT  48.3 13.619 49.464 14.675 ;
     RECT  58.992 13.619 59.544 14.773 ;
     RECT  44.688 13.909 46.008 15.059 ;
     RECT  30.912 14.629 37.944 15.203 ;
     RECT  53.04 14.629 54.168 15.251 ;
     RECT  30.912 15.203 37.812 15.443 ;
     RECT  58.992 14.773 60.456 15.443 ;
     RECT  22.896 14.773 22.92 15.587 ;
     RECT  31.488 15.443 37.812 15.587 ;
     RECT  61.584 11.797 62.616 15.683 ;
     RECT  57.888 13.619 57.912 15.829 ;
     RECT  58.992 15.443 59.544 15.829 ;
     RECT  57.888 15.829 59.544 15.875 ;
     RECT  26.7 14.101 27.144 15.925 ;
     RECT  61.584 15.683 62.112 15.973 ;
     RECT  25.68 14.773 25.704 16.019 ;
     RECT  44.688 15.059 45.912 16.019 ;
     RECT  48.3 14.675 49.416 16.213 ;
     RECT  58.128 15.875 59.544 16.259 ;
     RECT  48.3 16.213 49.848 16.501 ;
     RECT  51 2.137 51.312 16.501 ;
     RECT  56.4 13.427 56.712 16.501 ;
     RECT  28.752 13.235 29.712 16.595 ;
     RECT  45.6 16.019 45.912 16.789 ;
     RECT  53.04 15.251 54.12 16.835 ;
     RECT  31.488 15.587 35.352 17.027 ;
     RECT  31.488 17.027 35.256 17.029 ;
     RECT  48.3 16.501 51.312 17.029 ;
     RECT  45.6 16.789 46.008 17.075 ;
     RECT  29.232 16.595 29.712 17.077 ;
     RECT  30.816 17.029 35.256 17.077 ;
     RECT  26.7 15.925 27.24 17.171 ;
     RECT  29.232 17.077 35.256 17.219 ;
     RECT  63.408 17.077 63.432 17.219 ;
     RECT  69.024 12.517 70.212 17.363 ;
     RECT  24 14.147 24.312 17.461 ;
     RECT  60.672 15.973 62.112 17.461 ;
     RECT  36.384 15.587 37.812 17.509 ;
     RECT  26.7 17.171 27.144 17.605 ;
     RECT  58.992 16.259 59.544 17.605 ;
     RECT  40.2 12.755 40.512 17.653 ;
     RECT  29.4 17.219 35.256 18.181 ;
     RECT  36.384 17.509 38.568 18.181 ;
     RECT  47.952 17.029 51.312 18.419 ;
     RECT  18.6 2.151 18.912 18.757 ;
     RECT  69.744 17.363 70.212 18.803 ;
     RECT  29.4 18.181 38.568 18.851 ;
     RECT  39.984 17.653 40.512 18.851 ;
     RECT  47.952 18.419 49.032 18.851 ;
     RECT  53.7 16.835 54.12 18.851 ;
     RECT  47.952 18.851 48.984 18.947 ;
     RECT  60.672 17.461 62.376 18.947 ;
     RECT  42.9 13.667 43.212 18.949 ;
     RECT  23.904 17.461 24.312 19.237 ;
     RECT  30.816 18.851 38.568 19.283 ;
     RECT  42.768 18.949 43.212 19.333 ;
     RECT  64.5 11.843 65.832 19.427 ;
     RECT  58.176 17.605 59.544 19.621 ;
     RECT  60.672 18.947 62.112 19.621 ;
     RECT  56.304 16.501 56.712 19.811 ;
     RECT  29.4 18.851 29.712 19.861 ;
     RECT  69.792 18.803 70.212 19.909 ;
     RECT  18.6 18.757 19.368 20.003 ;
     RECT  23.904 19.237 24.408 20.099 ;
     RECT  42.528 19.333 43.212 20.147 ;
     RECT  25.92 17.605 27.144 20.341 ;
     RECT  68.928 19.909 70.212 20.435 ;
     RECT  50.544 18.419 51.312 20.485 ;
     RECT  30.816 19.283 37.812 20.579 ;
     RECT  42.768 20.147 43.212 20.869 ;
     RECT  53.7 18.851 54.012 20.965 ;
     RECT  56.4 19.811 56.712 20.965 ;
     RECT  69.9 20.435 70.212 20.965 ;
     RECT  64.5 19.427 64.92 21.061 ;
     RECT  29.28 19.861 29.712 21.155 ;
     RECT  49.584 20.485 51.312 21.155 ;
     RECT  58.176 19.621 62.112 21.155 ;
     RECT  63.504 19.669 63.528 21.155 ;
     RECT  25.92 20.341 27.384 21.203 ;
     RECT  24 20.099 24.408 21.301 ;
     RECT  21.3 9.683 21.612 21.349 ;
     RECT  40.2 18.851 40.512 21.541 ;
     RECT  69.9 20.965 70.44 21.541 ;
     RECT  30.816 20.579 35.256 21.683 ;
     RECT  49.584 21.155 49.608 21.683 ;
     RECT  52.848 20.965 54.012 21.683 ;
     RECT  56.4 20.965 56.808 21.731 ;
     RECT  24 21.301 24.792 21.781 ;
     RECT  31.104 21.683 35.256 22.211 ;
     RECT  23.232 21.781 24.792 22.259 ;
     RECT  40.2 21.541 41.064 22.259 ;
     RECT  69.9 21.541 70.68 22.259 ;
     RECT  20.496 21.349 21.612 22.499 ;
     RECT  64.5 21.061 65.592 22.499 ;
     RECT  25.92 21.203 27.144 22.741 ;
     RECT  67.2 2.151 67.512 22.741 ;
     RECT  42.768 20.869 43.32 22.789 ;
     RECT  51 21.155 51.312 22.789 ;
     RECT  50.88 22.789 51.312 23.555 ;
     RECT  31.488 22.211 35.256 23.557 ;
     RECT  25.92 22.741 27.192 23.651 ;
     RECT  42.72 22.789 43.32 23.845 ;
     RECT  21.072 22.499 21.612 23.987 ;
     RECT  25.92 23.651 27.144 23.987 ;
     RECT  23.232 22.259 24.312 24.035 ;
     RECT  25.92 23.987 27.012 24.083 ;
     RECT  45.6 17.075 45.912 24.277 ;
     RECT  39.024 23.557 39.048 24.469 ;
     RECT  40.2 22.259 40.512 24.469 ;
     RECT  45.6 24.277 46.152 24.469 ;
     RECT  67.2 22.741 67.992 24.469 ;
     RECT  26.7 24.083 27.012 24.949 ;
     RECT  21.3 23.987 21.612 25.045 ;
     RECT  67.2 24.469 68.856 25.045 ;
     RECT  69.9 22.259 70.212 25.045 ;
     RECT  39.024 24.469 40.512 25.091 ;
     RECT  31.248 23.557 35.256 25.139 ;
     RECT  55.296 24.709 55.32 25.187 ;
     RECT  53.7 21.683 54.012 25.189 ;
     RECT  67.2 25.045 70.212 25.571 ;
     RECT  26.7 24.949 27.912 25.955 ;
     RECT  67.2 25.571 68.856 26.003 ;
     RECT  42.48 23.845 43.32 26.101 ;
     RECT  44.976 24.469 46.152 26.243 ;
     RECT  64.5 22.499 64.92 26.389 ;
     RECT  31.248 25.139 35.112 26.531 ;
     RECT  21.3 25.045 21.72 26.629 ;
     RECT  64.5 26.389 65.832 26.675 ;
     RECT  56.4 21.731 56.712 26.677 ;
     RECT  53.7 25.189 54.84 26.771 ;
     RECT  36.384 20.579 37.812 26.773 ;
     RECT  42.432 26.101 43.32 26.819 ;
     RECT  56.4 26.677 57 27.203 ;
     RECT  21.3 26.629 22.2 27.395 ;
     RECT  59.1 21.155 62.112 27.397 ;
     RECT  68.832 26.003 68.856 27.733 ;
     RECT  69.9 25.571 70.212 27.733 ;
     RECT  39.744 25.091 40.512 27.877 ;
     RECT  39.744 27.877 40.776 28.115 ;
     RECT  45.6 26.243 45.912 28.213 ;
     RECT  58.704 27.397 62.112 28.213 ;
     RECT  26.7 25.955 27.144 28.261 ;
     RECT  45.6 28.213 46.008 28.261 ;
     RECT  36.384 26.773 37.944 28.501 ;
     RECT  58.32 28.213 62.112 28.547 ;
     RECT  36.384 28.501 38.808 28.835 ;
     RECT  39.888 28.115 40.776 28.835 ;
     RECT  39.888 28.835 40.512 28.979 ;
     RECT  45.6 28.261 46.104 28.979 ;
     RECT  26.7 28.261 27.72 29.075 ;
     RECT  36.384 28.835 37.944 29.075 ;
     RECT  53.7 26.771 54.744 29.123 ;
     RECT  31.488 26.531 35.112 29.171 ;
     RECT  58.32 28.547 60.6 29.363 ;
     RECT  65.808 26.675 65.832 29.459 ;
     RECT  59.1 29.363 60.6 29.699 ;
     RECT  42.9 26.819 43.32 30.085 ;
     RECT  40.08 28.979 40.512 30.181 ;
     RECT  61.584 28.547 62.112 30.181 ;
     RECT  63.216 29.605 63.24 30.181 ;
     RECT  64.5 26.675 64.812 30.181 ;
     RECT  36.384 29.075 37.812 30.275 ;
     RECT  49.584 27.877 49.608 30.277 ;
     RECT  49.584 30.277 49.944 30.323 ;
     RECT  61.584 30.181 63.24 30.563 ;
     RECT  59.1 29.699 59.784 30.709 ;
     RECT  61.584 30.563 62.472 30.755 ;
     RECT  68.832 27.733 70.212 30.755 ;
     RECT  67.2 26.003 67.512 30.757 ;
     RECT  40.032 30.181 40.512 30.803 ;
     RECT  42.048 30.085 43.32 30.851 ;
     RECT  66.672 30.757 67.512 30.853 ;
     RECT  53.7 29.123 54.504 31.093 ;
     RECT  64.368 30.181 64.812 31.139 ;
     RECT  31.536 29.171 35.112 31.379 ;
     RECT  59.1 30.709 60.504 31.381 ;
     RECT  66.288 30.853 67.512 31.427 ;
     RECT  61.68 30.755 62.472 31.571 ;
     RECT  49.92 30.323 49.944 31.667 ;
     RECT  40.08 30.803 40.512 32.245 ;
     RECT  42.768 30.851 43.32 32.291 ;
     RECT  31.536 31.379 33.816 32.389 ;
     RECT  61.68 31.571 62.424 32.771 ;
     RECT  67.2 31.427 67.512 32.869 ;
     RECT  66.768 32.869 67.512 32.965 ;
     RECT  58.464 31.381 60.504 33.059 ;
     RECT  40.032 32.245 40.512 33.061 ;
     RECT  53.7 31.093 54.6 33.107 ;
     RECT  47.952 18.947 48.612 33.109 ;
     RECT  24 24.035 24.312 33.589 ;
     RECT  66.72 32.965 67.512 33.683 ;
     RECT  37.104 30.275 37.812 33.733 ;
     RECT  31.392 32.389 33.816 33.779 ;
     RECT  56.4 27.203 56.712 33.829 ;
     RECT  61.8 32.771 62.424 33.829 ;
     RECT  72.6 2.151 72.912 33.877 ;
     RECT  39.36 33.061 40.512 34.115 ;
     RECT  47.952 33.109 49.368 34.259 ;
     RECT  47.952 34.259 48.612 34.309 ;
     RECT  69.264 30.755 70.212 34.595 ;
     RECT  61.8 33.829 63.096 34.739 ;
     RECT  69.36 34.595 70.212 34.739 ;
     RECT  59.1 33.059 60.504 34.787 ;
     RECT  37.056 33.733 37.812 34.835 ;
     RECT  72.6 33.877 73.56 34.835 ;
     RECT  53.7 33.107 54.12 35.027 ;
     RECT  41.712 34.645 41.736 35.363 ;
     RECT  56.4 33.829 56.808 35.363 ;
     RECT  37.104 34.835 37.812 35.411 ;
     RECT  39.456 34.115 40.512 35.605 ;
     RECT  45.6 28.979 46.008 35.701 ;
     RECT  66.768 33.683 67.512 35.747 ;
     RECT  34.8 31.379 35.112 35.845 ;
     RECT  53.7 35.027 54.012 35.845 ;
     RECT  60.48 34.787 60.504 35.845 ;
     RECT  61.8 34.739 62.112 35.845 ;
     RECT  47.616 34.309 48.612 35.893 ;
     RECT  60.48 35.845 62.112 36.035 ;
     RECT  37.5 35.411 37.812 36.133 ;
     RECT  39.168 35.605 40.512 36.133 ;
     RECT  72.6 34.835 72.912 36.421 ;
     RECT  31.392 33.779 33.48 36.515 ;
     RECT  53.568 35.845 54.012 36.515 ;
     RECT  34.8 35.845 35.88 36.517 ;
     RECT  47.52 35.893 48.612 36.517 ;
     RECT  23.568 33.589 24.312 36.563 ;
     RECT  60.816 36.035 62.112 36.563 ;
     RECT  29.4 21.155 29.712 36.805 ;
     RECT  31.536 36.515 33.48 37.043 ;
     RECT  45.6 35.701 46.152 37.043 ;
     RECT  37.5 36.133 40.512 37.091 ;
     RECT  72.6 36.421 73.896 37.091 ;
     RECT  69.9 34.739 70.212 37.093 ;
     RECT  69.9 37.093 70.344 37.427 ;
     RECT  53.7 36.515 54.012 37.573 ;
     RECT  32.1 37.043 33.48 37.667 ;
     RECT  47.424 36.517 48.612 37.667 ;
     RECT  60.624 37.429 60.648 38.243 ;
     RECT  44.448 35.413 44.472 38.339 ;
     RECT  32.1 37.667 33.192 38.533 ;
     RECT  31.92 38.533 33.192 38.677 ;
     RECT  37.5 37.091 37.812 38.725 ;
     RECT  59.1 34.787 59.412 38.773 ;
     RECT  61.8 36.563 62.112 39.061 ;
     RECT  34.8 36.517 35.976 39.203 ;
     RECT  61.8 39.061 62.232 39.253 ;
     RECT  69.9 37.427 70.212 39.301 ;
     RECT  59.1 38.773 60.36 39.347 ;
     RECT  64.5 31.139 64.812 39.877 ;
     RECT  39.168 37.091 40.512 40.067 ;
     RECT  61.68 39.253 62.232 40.163 ;
     RECT  31.344 38.677 33.192 40.165 ;
     RECT  64.5 39.877 65.208 40.211 ;
     RECT  55.296 39.493 55.32 40.259 ;
     RECT  64.5 40.211 65.016 40.403 ;
     RECT  69.9 39.301 70.824 40.549 ;
     RECT  68.976 40.549 70.824 40.595 ;
     RECT  42.9 32.291 43.32 40.693 ;
     RECT  42.768 40.693 43.32 40.837 ;
     RECT  26.7 29.075 27.144 41.125 ;
     RECT  40.2 40.067 40.512 41.125 ;
     RECT  47.616 37.667 48.612 41.171 ;
     RECT  37.392 38.725 37.812 41.267 ;
     RECT  56.4 35.363 56.712 41.413 ;
     RECT  59.1 39.347 59.412 41.461 ;
     RECT  60.576 40.693 60.6 41.461 ;
     RECT  59.1 41.461 60.6 41.603 ;
     RECT  26.7 41.125 27.912 41.651 ;
     RECT  39.168 40.067 39.192 41.651 ;
     RECT  42.624 40.837 43.32 41.939 ;
     RECT  56.304 41.413 56.712 41.939 ;
     RECT  40.2 41.125 40.632 41.941 ;
     RECT  67.2 35.747 67.512 41.989 ;
     RECT  59.1 41.603 60.072 42.227 ;
     RECT  61.8 40.163 62.232 42.323 ;
     RECT  42.768 41.939 43.32 42.515 ;
     RECT  40.2 41.941 41.112 42.755 ;
     RECT  64.5 40.403 64.812 42.805 ;
     RECT  68.976 40.595 70.212 43.045 ;
     RECT  47.856 41.171 48.612 43.139 ;
     RECT  31.296 40.165 33.192 43.141 ;
     RECT  68.976 43.045 70.728 43.187 ;
     RECT  64.5 42.805 65.064 43.235 ;
     RECT  67.2 41.989 67.608 43.909 ;
     RECT  67.2 43.909 67.8 44.291 ;
     RECT  74.208 43.909 74.232 44.293 ;
     RECT  75.3 2.151 75.612 44.293 ;
     RECT  64.5 43.235 64.812 44.389 ;
     RECT  61.8 42.323 62.112 44.437 ;
     RECT  74.208 44.293 75.612 44.627 ;
     RECT  74.208 44.627 74.232 44.723 ;
     RECT  61.008 44.437 62.112 45.059 ;
     RECT  39.168 44.437 39.192 45.299 ;
     RECT  61.8 45.059 62.112 45.541 ;
     RECT  34.8 39.203 35.112 46.021 ;
     RECT  68.976 43.187 70.212 46.259 ;
     RECT  29.28 36.805 29.712 46.501 ;
     RECT  56.4 41.939 56.712 46.837 ;
     RECT  51 23.555 51.312 46.933 ;
     RECT  69.9 46.259 70.212 47.221 ;
     RECT  64.5 44.389 65.016 47.269 ;
     RECT  29.04 46.501 29.712 47.363 ;
     RECT  61.8 45.541 62.52 47.363 ;
     RECT  37.5 41.267 37.812 47.845 ;
     RECT  48.3 43.139 48.612 47.845 ;
     RECT  50.304 46.933 51.312 47.893 ;
     RECT  42.9 42.515 43.32 48.133 ;
     RECT  48.192 47.845 48.612 48.515 ;
     RECT  42.9 48.133 43.368 48.611 ;
     RECT  50.304 47.893 51.672 48.659 ;
     RECT  37.056 47.845 37.812 48.661 ;
     RECT  50.304 48.659 51.312 48.707 ;
     RECT  52.896 37.573 54.012 48.707 ;
     RECT  59.1 42.227 59.412 48.901 ;
     RECT  34.8 46.021 35.88 49.043 ;
     RECT  58.656 48.901 59.412 49.139 ;
     RECT  37.056 48.661 38.76 49.187 ;
     RECT  34.8 49.043 35.352 50.005 ;
     RECT  40.2 42.755 40.512 50.581 ;
     RECT  69.6 47.221 70.212 50.771 ;
     RECT  64.5 47.269 65.304 50.867 ;
     RECT  31.296 43.141 33.432 51.347 ;
     RECT  31.296 51.347 32.412 51.445 ;
     RECT  30.912 51.445 32.412 51.491 ;
     RECT  40.2 50.581 41.256 51.875 ;
     RECT  34.8 50.005 36.312 51.973 ;
     RECT  37.5 49.187 38.76 51.973 ;
     RECT  53.7 48.707 54.012 51.973 ;
     RECT  34.8 51.973 38.76 52.211 ;
     RECT  53.568 51.973 54.012 52.405 ;
     RECT  61.8 47.363 62.424 52.693 ;
     RECT  61.008 52.693 62.424 52.739 ;
     RECT  53.568 52.405 54.168 52.741 ;
     RECT  52.944 52.741 54.168 52.883 ;
     RECT  52.944 52.883 54.012 53.075 ;
     RECT  64.5 50.867 65.016 54.085 ;
     RECT  56.4 46.837 56.808 54.179 ;
     RECT  59.1 49.139 59.412 54.469 ;
     RECT  64.5 54.085 65.112 54.755 ;
     RECT  56.4 54.179 56.712 55.237 ;
     RECT  58.176 54.469 59.412 55.331 ;
     RECT  58.56 55.331 59.412 55.523 ;
     RECT  61.008 52.739 62.112 55.907 ;
     RECT  36.288 52.211 38.76 55.955 ;
     RECT  55.968 55.237 56.712 56.003 ;
     RECT  53.568 53.075 54.012 56.483 ;
     RECT  30.912 51.491 30.936 57.059 ;
     RECT  37.5 55.955 38.76 57.059 ;
     RECT  34.8 52.211 35.112 62.629 ;
     RECT  36.288 55.955 36.312 65.173 ;
     RECT  37.5 57.059 38.712 65.173 ;
     RECT  26.7 41.651 27.144 66.179 ;
     RECT  29.4 47.363 29.712 68.437 ;
     RECT  31.968 51.491 32.412 69.445 ;
     RECT  33.408 51.347 33.432 70.069 ;
     RECT  34.8 62.629 35.208 70.069 ;
     RECT  36.288 65.173 38.712 70.163 ;
     RECT  33.408 70.069 35.208 70.739 ;
     RECT  31.296 69.445 32.412 70.787 ;
     RECT  31.92 70.787 32.412 70.981 ;
     RECT  33.408 70.739 35.112 70.981 ;
     RECT  29.4 68.437 30.024 71.221 ;
     RECT  31.92 70.981 35.112 71.315 ;
     RECT  29.4 71.221 30.264 71.797 ;
     RECT  31.92 71.315 33 71.797 ;
     RECT  33.984 71.315 35.112 71.797 ;
     RECT  36.288 70.163 38.616 71.939 ;
     RECT  29.4 71.797 33 72.229 ;
     RECT  28.176 66.565 28.2 72.325 ;
     RECT  29.28 72.229 33 72.325 ;
     RECT  33.984 71.797 35.208 72.805 ;
     RECT  28.176 72.325 33 72.853 ;
     RECT  33.984 72.805 35.304 72.853 ;
     RECT  28.176 72.853 35.304 72.901 ;
     RECT  36.288 71.939 37.812 72.901 ;
     RECT  28.128 72.901 37.812 74.147 ;
     RECT  42.9 48.611 43.32 74.723 ;
     RECT  28.176 74.147 37.812 74.867 ;
     RECT  28.176 74.867 35.208 74.915 ;
     RECT  36.624 74.867 37.812 75.299 ;
     RECT  28.176 74.915 35.112 75.541 ;
     RECT  2.4 2.151 2.712 75.609 ;
     RECT  5.1 2.151 5.412 75.609 ;
     RECT  7.8 2.151 8.112 75.609 ;
     RECT  10.5 2.151 10.812 75.609 ;
     RECT  13.2 2.151 13.512 75.609 ;
     RECT  15.9 2.151 16.212 75.609 ;
     RECT  18.6 20.003 18.912 75.609 ;
     RECT  21.3 27.395 21.612 75.609 ;
     RECT  24 36.563 24.312 75.609 ;
     RECT  26.7 66.179 27.012 75.609 ;
     RECT  28.032 75.541 35.112 75.609 ;
     RECT  37.5 75.299 37.812 75.609 ;
     RECT  40.2 51.875 40.512 75.609 ;
     RECT  42.9 74.723 43.212 75.609 ;
     RECT  45.6 37.043 45.912 75.609 ;
     RECT  48.3 48.515 48.612 75.609 ;
     RECT  51 48.707 51.312 75.609 ;
     RECT  53.7 56.483 54.012 75.609 ;
     RECT  56.4 56.003 56.712 75.609 ;
     RECT  59.1 55.523 59.412 75.609 ;
     RECT  61.8 55.907 62.112 75.609 ;
     RECT  64.5 54.755 64.812 75.609 ;
     RECT  67.2 44.291 67.512 75.609 ;
     RECT  69.9 50.771 70.212 75.609 ;
     RECT  72.6 37.091 72.912 75.609 ;
     RECT  75.3 44.627 75.612 75.609 ;
     RECT  78 2.151 78.312 75.609 ;
     RECT  80.7 2.151 81.012 75.609 ;
     RECT  83.4 2.151 83.712 75.609 ;
     RECT  2.4 75.609 2.52 75.623 ;
     RECT  5.1 75.609 5.22 75.623 ;
     RECT  7.8 75.609 7.92 75.623 ;
     RECT  10.5 75.609 10.62 75.623 ;
     RECT  13.2 75.609 13.32 75.623 ;
     RECT  15.9 75.609 16.02 75.623 ;
     RECT  18.6 75.609 18.72 75.623 ;
     RECT  21.3 75.609 21.42 75.623 ;
     RECT  24 75.609 24.12 75.623 ;
     RECT  26.7 75.609 26.82 75.623 ;
     RECT  28.032 75.609 34.92 75.623 ;
     RECT  37.5 75.609 37.62 75.623 ;
     RECT  40.2 75.609 40.32 75.623 ;
     RECT  42.9 75.609 43.176 75.623 ;
     RECT  45.6 75.609 45.72 75.623 ;
     RECT  48.3 75.609 48.42 75.623 ;
     RECT  51 75.609 51.12 75.623 ;
     RECT  53.7 75.609 53.82 75.623 ;
     RECT  56.4 75.609 56.52 75.623 ;
     RECT  59.1 75.609 59.22 75.623 ;
     RECT  61.8 75.609 61.92 75.623 ;
     RECT  64.5 75.609 64.62 75.623 ;
     RECT  67.2 75.609 67.32 75.623 ;
     RECT  69.9 75.609 70.02 75.623 ;
     RECT  72.6 75.609 72.72 75.623 ;
     RECT  75.3 75.609 75.42 75.623 ;
     RECT  78 75.609 78.12 75.623 ;
     RECT  80.7 75.609 80.82 75.623 ;
     RECT  83.4 75.609 83.52 75.623 ;
     RECT  28.032 75.623 34.296 77.712 ;
     RECT  28.032 0.611 28.128 1.187 ;
     RECT  28.032 1.187 28.224 1.715 ;
     RECT  28.032 1.715 28.32 1.763 ;
     RECT  28.032 1.763 28.416 2.137 ;
     RECT  52.032 1.763 52.704 2.137 ;
     RECT  26.82 2.137 28.416 2.151 ;
     RECT  51.312 2.137 52.704 4.019 ;
     RECT  27.012 2.151 28.416 2.291 ;
     RECT  27.012 2.291 27.144 3.253 ;
     RECT  45.912 2.485 46.896 3.443 ;
     RECT  46.92 2.485 48.3 3.443 ;
     RECT  36.312 3.637 37.5 5.365 ;
     RECT  49.608 4.117 51 5.171 ;
     RECT  48.612 4.403 49.584 5.171 ;
     RECT  27.144 4.501 28.416 4.979 ;
     RECT  40.512 4.501 41.808 6.323 ;
     RECT  41.832 4.501 42.9 6.323 ;
     RECT  43.212 4.691 43.368 5.749 ;
     RECT  27.012 4.979 28.416 6.419 ;
     RECT  36.408 5.365 37.5 5.461 ;
     RECT  62.112 5.557 63.456 6.563 ;
     RECT  63.48 5.557 64.5 6.563 ;
     RECT  43.212 5.749 44.448 7.381 ;
     RECT  29.712 6.323 30.816 7.765 ;
     RECT  27.012 6.419 29.136 6.613 ;
     RECT  27.012 6.613 27.984 9.925 ;
     RECT  28.008 6.613 29.136 7.957 ;
     RECT  51.312 6.805 52.416 11.459 ;
     RECT  38.472 6.853 39.744 6.901 ;
     RECT  38.568 6.901 39.744 7.187 ;
     RECT  54.12 6.995 55.248 7.475 ;
     RECT  39.696 7.187 39.744 7.957 ;
     RECT  43.368 7.381 44.448 9.107 ;
     RECT  23.904 7.475 24 7.957 ;
     RECT  54.012 7.475 55.392 8.579 ;
     RECT  55.416 7.523 56.4 8.579 ;
     RECT  22.536 7.957 24 8.723 ;
     RECT  28.008 7.957 29.088 8.579 ;
     RECT  57.912 8.003 58.992 11.941 ;
     RECT  52.44 8.051 53.568 8.579 ;
     RECT  49.56 8.341 51 13.619 ;
     RECT  28.008 8.579 29.136 10.307 ;
     RECT  52.44 8.579 53.7 11.459 ;
     RECT  54.012 8.579 54.12 9.061 ;
     RECT  56.712 8.579 57.888 11.941 ;
     RECT  29.712 9.107 30.816 9.155 ;
     RECT  42.192 9.107 42.9 10.453 ;
     RECT  43.212 9.107 44.448 9.155 ;
     RECT  29.712 9.155 30.912 12.517 ;
     RECT  43.212 9.155 44.688 10.835 ;
     RECT  67.512 9.445 69.024 10.355 ;
     RECT  63.936 10.355 64.08 11.797 ;
     RECT  40.512 10.453 42 10.645 ;
     RECT  40.512 10.645 41.904 10.835 ;
     RECT  65.832 10.693 67.2 19.427 ;
     RECT  40.512 10.835 42 11.939 ;
     RECT  43.212 10.835 44.976 12.229 ;
     RECT  53.568 11.459 53.7 11.749 ;
     RECT  35.352 11.651 36.384 14.629 ;
     RECT  62.616 11.797 64.08 11.843 ;
     RECT  27.24 11.893 28.752 12.323 ;
     RECT  54.888 11.941 56.4 13.187 ;
     RECT  43.752 12.229 44.976 13.477 ;
     RECT  67.512 12.517 69.024 17.363 ;
     RECT  24.312 12.611 24.408 13.525 ;
     RECT  54.12 13.187 54.168 14.629 ;
     RECT  29.712 13.235 30.912 15.443 ;
     RECT  45.912 13.285 46.992 13.909 ;
     RECT  47.016 13.285 48.3 14.243 ;
     RECT  56.712 13.427 57.888 15.875 ;
     RECT  24.312 13.525 25.584 14.339 ;
     RECT  25.608 13.525 26.7 14.339 ;
     RECT  57.912 13.619 58.992 15.829 ;
     RECT  43.212 13.667 44.688 16.019 ;
     RECT  46.008 13.909 46.992 14.243 ;
     RECT  23.328 14.147 24 14.773 ;
     RECT  24.312 14.339 26.7 14.773 ;
     RECT  21.612 14.773 22.896 15.587 ;
     RECT  22.92 14.773 24 15.587 ;
     RECT  24.312 14.773 25.68 16.019 ;
     RECT  25.704 14.773 26.7 16.019 ;
     RECT  60.456 14.773 61.584 15.443 ;
     RECT  59.544 15.443 61.584 15.973 ;
     RECT  35.352 15.587 36.384 17.027 ;
     RECT  62.112 15.683 62.616 17.077 ;
     RECT  56.712 15.875 58.128 16.259 ;
     RECT  27.24 15.925 28.752 16.595 ;
     RECT  59.544 15.973 60.672 19.621 ;
     RECT  49.848 16.213 51 16.501 ;
     RECT  56.712 16.259 58.992 17.605 ;
     RECT  35.256 17.027 36.384 18.181 ;
     RECT  29.712 17.029 30.816 17.077 ;
     RECT  62.112 17.077 63.408 17.219 ;
     RECT  63.432 17.077 64.5 17.219 ;
     RECT  62.112 17.219 62.376 17.461 ;
     RECT  56.712 17.605 58.176 20.965 ;
     RECT  38.568 17.653 39.984 18.851 ;
     RECT  49.032 18.419 50.544 18.851 ;
     RECT  69.744 18.803 69.792 19.909 ;
     RECT  29.712 18.851 30.816 21.683 ;
     RECT  62.112 18.947 62.376 19.669 ;
     RECT  24.408 19.237 25.92 21.301 ;
     RECT  62.112 19.669 63.504 21.155 ;
     RECT  63.528 19.669 64.5 21.155 ;
     RECT  67.512 19.909 68.928 20.435 ;
     RECT  48.612 20.485 49.584 21.683 ;
     RECT  35.256 20.579 36.384 25.139 ;
     RECT  56.808 20.965 58.176 21.155 ;
     RECT  49.608 21.155 51 21.683 ;
     RECT  24.792 21.301 25.92 22.259 ;
     RECT  29.712 21.683 31.104 22.211 ;
     RECT  50.88 21.683 51 22.789 ;
     RECT  31.248 22.211 31.488 23.557 ;
     RECT  37.812 23.557 39.024 25.091 ;
     RECT  39.048 23.557 40.2 24.469 ;
     RECT  27.144 23.651 27.192 23.987 ;
     RECT  27.012 23.987 27.192 24.949 ;
     RECT  68.856 24.469 69.9 25.045 ;
     RECT  54.012 24.709 55.296 25.187 ;
     RECT  55.32 24.709 56.4 25.187 ;
     RECT  27.912 24.949 29.4 25.955 ;
     RECT  35.112 25.139 36.384 30.275 ;
     RECT  54.012 25.187 54.84 25.189 ;
     RECT  68.856 25.571 69.9 27.733 ;
     RECT  67.512 26.003 68.832 30.755 ;
     RECT  65.832 26.389 67.2 29.459 ;
     RECT  64.812 26.675 65.808 29.459 ;
     RECT  48.612 27.877 49.584 30.323 ;
     RECT  49.608 27.877 51 30.277 ;
     RECT  39.744 28.115 39.888 28.501 ;
     RECT  38.808 28.501 39.888 28.835 ;
     RECT  60.6 28.547 61.584 29.699 ;
     RECT  40.032 28.979 40.08 30.181 ;
     RECT  64.812 29.459 67.2 30.757 ;
     RECT  62.112 29.605 63.216 30.181 ;
     RECT  63.24 29.605 64.5 30.181 ;
     RECT  59.784 29.699 61.584 30.709 ;
     RECT  63.24 30.181 64.368 30.563 ;
     RECT  49.944 30.277 51 31.667 ;
     RECT  48.612 30.323 49.92 31.667 ;
     RECT  60.504 30.709 61.584 30.755 ;
     RECT  60.504 30.755 61.68 32.771 ;
     RECT  64.812 30.757 66.672 30.853 ;
     RECT  40.032 30.803 40.08 32.245 ;
     RECT  64.812 30.853 66.288 31.427 ;
     RECT  33.816 31.379 34.8 33.779 ;
     RECT  66.768 31.427 67.2 32.869 ;
     RECT  48.612 31.667 49.368 33.109 ;
     RECT  60.504 32.771 61.8 35.845 ;
     RECT  33.48 33.779 34.8 37.667 ;
     RECT  63.096 33.829 64.5 34.739 ;
     RECT  39.36 34.115 39.456 35.605 ;
     RECT  40.512 34.645 41.712 35.363 ;
     RECT  41.736 34.645 42.9 35.363 ;
     RECT  59.412 34.787 60.48 36.035 ;
     RECT  37.056 34.835 37.104 35.411 ;
     RECT  37.056 35.411 37.5 35.845 ;
     RECT  43.32 35.413 44.448 38.339 ;
     RECT  44.472 35.413 45.6 38.339 ;
     RECT  37.812 35.605 39.168 36.133 ;
     RECT  46.152 35.701 47.616 35.893 ;
     RECT  35.88 35.845 37.5 36.517 ;
     RECT  46.152 35.893 47.52 36.517 ;
     RECT  59.412 36.035 60.816 36.563 ;
     RECT  73.896 36.421 75.3 37.091 ;
     RECT  53.568 36.515 53.7 37.573 ;
     RECT  35.976 36.517 37.5 38.725 ;
     RECT  46.152 36.517 47.424 37.043 ;
     RECT  59.412 36.563 61.8 37.429 ;
     RECT  31.92 37.043 32.1 38.533 ;
     RECT  45.912 37.043 47.424 37.667 ;
     RECT  37.812 37.091 39.168 41.651 ;
     RECT  59.412 37.429 60.624 38.243 ;
     RECT  60.648 37.429 61.8 38.243 ;
     RECT  59.412 38.243 61.8 38.773 ;
     RECT  35.976 38.725 37.392 39.203 ;
     RECT  60.36 38.773 61.8 39.253 ;
     RECT  60.36 39.253 61.68 39.347 ;
     RECT  59.412 39.347 61.68 40.163 ;
     RECT  54.012 39.493 55.296 40.259 ;
     RECT  55.32 39.493 56.4 40.259 ;
     RECT  39.192 40.067 40.2 41.651 ;
     RECT  59.412 40.163 61.8 40.693 ;
     RECT  56.304 40.259 56.4 41.413 ;
     RECT  67.512 40.549 68.976 41.989 ;
     RECT  59.412 40.693 60.576 41.461 ;
     RECT  60.6 40.693 61.8 41.603 ;
     RECT  27.912 41.125 29.28 41.651 ;
     RECT  67.608 41.989 68.976 43.909 ;
     RECT  33.432 43.141 34.8 70.069 ;
     RECT  64.812 43.235 65.016 44.389 ;
     RECT  67.8 43.909 68.976 44.291 ;
     RECT  72.912 43.909 74.208 44.723 ;
     RECT  74.232 43.909 75.3 44.293 ;
     RECT  67.512 44.291 68.976 46.259 ;
     RECT  37.812 44.437 39.168 45.299 ;
     RECT  39.192 44.437 40.2 45.299 ;
     RECT  74.232 44.627 75.3 44.723 ;
     RECT  69.6 46.259 69.9 47.221 ;
     RECT  35.88 47.845 37.056 49.043 ;
     RECT  51.672 47.893 52.896 48.659 ;
     RECT  38.76 48.661 40.2 57.059 ;
     RECT  35.352 49.043 37.056 49.187 ;
     RECT  35.352 49.187 37.5 50.005 ;
     RECT  36.312 50.005 37.5 51.973 ;
     RECT  32.412 51.347 33.408 70.981 ;
     RECT  29.712 51.445 30.912 57.059 ;
     RECT  30.936 51.491 31.968 57.059 ;
     RECT  35.112 52.211 36.288 62.629 ;
     RECT  56.712 54.179 56.808 54.469 ;
     RECT  56.712 54.469 58.176 55.331 ;
     RECT  36.312 55.955 37.5 65.173 ;
     RECT  38.712 57.059 40.2 70.163 ;
     RECT  35.208 62.629 36.288 70.739 ;
     RECT  27.012 66.179 27.144 66.565 ;
     RECT  27.012 66.565 28.176 72.901 ;
     RECT  28.2 66.565 29.4 72.229 ;
     RECT  30.024 69.445 31.296 70.787 ;
     RECT  35.112 70.739 36.288 71.797 ;
     RECT  30.024 70.787 31.92 71.221 ;
     RECT  30.264 71.221 31.92 71.797 ;
     RECT  33 71.315 33.984 72.853 ;
     RECT  35.208 71.797 36.288 72.805 ;
     RECT  28.2 72.229 29.28 72.325 ;
     RECT  35.304 72.805 36.288 72.901 ;
     RECT  27.012 72.901 28.128 74.147 ;
     RECT  27.012 74.147 28.176 75.541 ;
     RECT  35.208 74.867 36.624 74.915 ;
     RECT  35.112 74.915 36.624 75.299 ;
     RECT  27.012 75.541 28.032 75.609 ;
     RECT  26.82 75.609 28.032 75.623 ;
  END
END dsfd_node_NNfd
END LIBRARY
